VERSION 5.8 ;
BUSBITCHARS "[]" ;
DIVIDERCHAR "/" ;
UNITS
    DATABASE MICRONS 1000 ;
END UNITS

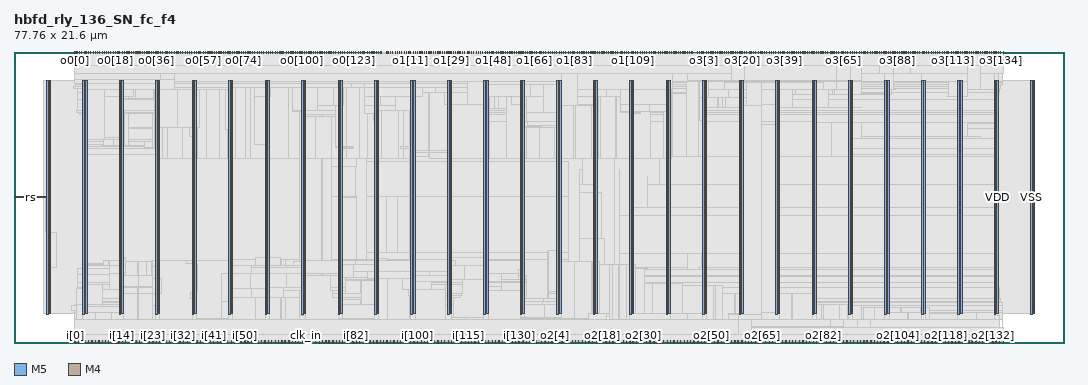
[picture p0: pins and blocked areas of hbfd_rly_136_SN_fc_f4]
MACRO hbfd_rly_136_SN_fc_f4
  FOREIGN hbfd_rly_136_SN_fc_f4 0 0 ;
  CLASS BLOCK ;
  SIZE 77.76 BY 21.6 ;
  PIN clk_in
    DIRECTION INPUT ;
    USE SIGNAL ;
    PORT
      LAYER M5 ;
        RECT  21.6 0 21.624 0.192 ;
    END
  END clk_in
  PIN clk_out0
    DIRECTION OUTPUT ;
    USE SIGNAL ;
    PORT
      LAYER M5 ;
        RECT  15.84 21.408 15.864 21.6 ;
    END
  END clk_out0
  PIN clk_out1
    DIRECTION OUTPUT ;
    USE SIGNAL ;
    PORT
      LAYER M5 ;
        RECT  38.88 21.408 38.904 21.6 ;
    END
  END clk_out1
  PIN clk_out2
    DIRECTION OUTPUT ;
    USE SIGNAL ;
    PORT
      LAYER M5 ;
        RECT  56.16 0 56.184 0.192 ;
    END
  END clk_out2
  PIN clk_out3
    DIRECTION OUTPUT ;
    USE SIGNAL ;
    PORT
      LAYER M5 ;
        RECT  61.92 21.408 61.944 21.6 ;
    END
  END clk_out3
  PIN i[0]
    DIRECTION INPUT ;
    USE SIGNAL ;
    PORT
      LAYER M5 ;
        RECT  4.512 0 4.536 0.192 ;
    END
  END i[0]
  PIN i[100]
    DIRECTION INPUT ;
    USE SIGNAL ;
    PORT
      LAYER M5 ;
        RECT  29.856 0 29.88 0.192 ;
    END
  END i[100]
  PIN i[101]
    DIRECTION INPUT ;
    USE SIGNAL ;
    PORT
      LAYER M5 ;
        RECT  30.144 0 30.168 0.192 ;
    END
  END i[101]
  PIN i[102]
    DIRECTION INPUT ;
    USE SIGNAL ;
    PORT
      LAYER M5 ;
        RECT  30.384 0 30.408 0.192 ;
    END
  END i[102]
  PIN i[103]
    DIRECTION INPUT ;
    USE SIGNAL ;
    PORT
      LAYER M5 ;
        RECT  30.624 0 30.648 0.192 ;
    END
  END i[103]
  PIN i[104]
    DIRECTION INPUT ;
    USE SIGNAL ;
    PORT
      LAYER M5 ;
        RECT  30.864 0 30.888 0.192 ;
    END
  END i[104]
  PIN i[105]
    DIRECTION INPUT ;
    USE SIGNAL ;
    PORT
      LAYER M5 ;
        RECT  31.152 0 31.176 0.192 ;
    END
  END i[105]
  PIN i[106]
    DIRECTION INPUT ;
    USE SIGNAL ;
    PORT
      LAYER M5 ;
        RECT  31.392 0 31.416 0.192 ;
    END
  END i[106]
  PIN i[107]
    DIRECTION INPUT ;
    USE SIGNAL ;
    PORT
      LAYER M5 ;
        RECT  31.632 0 31.656 0.192 ;
    END
  END i[107]
  PIN i[108]
    DIRECTION INPUT ;
    USE SIGNAL ;
    PORT
      LAYER M5 ;
        RECT  31.872 0 31.896 0.192 ;
    END
  END i[108]
  PIN i[109]
    DIRECTION INPUT ;
    USE SIGNAL ;
    PORT
      LAYER M5 ;
        RECT  32.16 0 32.184 0.192 ;
    END
  END i[109]
  PIN i[10]
    DIRECTION INPUT ;
    USE SIGNAL ;
    PORT
      LAYER M5 ;
        RECT  7.008 0 7.032 0.192 ;
    END
  END i[10]
  PIN i[110]
    DIRECTION INPUT ;
    USE SIGNAL ;
    PORT
      LAYER M5 ;
        RECT  32.4 0 32.424 0.192 ;
    END
  END i[110]
  PIN i[111]
    DIRECTION INPUT ;
    USE SIGNAL ;
    PORT
      LAYER M5 ;
        RECT  32.64 0 32.664 0.192 ;
    END
  END i[111]
  PIN i[112]
    DIRECTION INPUT ;
    USE SIGNAL ;
    PORT
      LAYER M5 ;
        RECT  32.88 0 32.904 0.192 ;
    END
  END i[112]
  PIN i[113]
    DIRECTION INPUT ;
    USE SIGNAL ;
    PORT
      LAYER M5 ;
        RECT  33.12 0 33.144 0.192 ;
    END
  END i[113]
  PIN i[114]
    DIRECTION INPUT ;
    USE SIGNAL ;
    PORT
      LAYER M5 ;
        RECT  33.408 0 33.432 0.192 ;
    END
  END i[114]
  PIN i[115]
    DIRECTION INPUT ;
    USE SIGNAL ;
    PORT
      LAYER M5 ;
        RECT  33.648 0 33.672 0.192 ;
    END
  END i[115]
  PIN i[116]
    DIRECTION INPUT ;
    USE SIGNAL ;
    PORT
      LAYER M5 ;
        RECT  33.888 0 33.912 0.192 ;
    END
  END i[116]
  PIN i[117]
    DIRECTION INPUT ;
    USE SIGNAL ;
    PORT
      LAYER M5 ;
        RECT  34.128 0 34.152 0.192 ;
    END
  END i[117]
  PIN i[118]
    DIRECTION INPUT ;
    USE SIGNAL ;
    PORT
      LAYER M5 ;
        RECT  34.416 0 34.44 0.192 ;
    END
  END i[118]
  PIN i[119]
    DIRECTION INPUT ;
    USE SIGNAL ;
    PORT
      LAYER M5 ;
        RECT  34.656 0 34.68 0.192 ;
    END
  END i[119]
  PIN i[11]
    DIRECTION INPUT ;
    USE SIGNAL ;
    PORT
      LAYER M5 ;
        RECT  7.248 0 7.272 0.192 ;
    END
  END i[11]
  PIN i[120]
    DIRECTION INPUT ;
    USE SIGNAL ;
    PORT
      LAYER M5 ;
        RECT  34.896 0 34.92 0.192 ;
    END
  END i[120]
  PIN i[121]
    DIRECTION INPUT ;
    USE SIGNAL ;
    PORT
      LAYER M5 ;
        RECT  35.136 0 35.16 0.192 ;
    END
  END i[121]
  PIN i[122]
    DIRECTION INPUT ;
    USE SIGNAL ;
    PORT
      LAYER M5 ;
        RECT  35.424 0 35.448 0.192 ;
    END
  END i[122]
  PIN i[123]
    DIRECTION INPUT ;
    USE SIGNAL ;
    PORT
      LAYER M5 ;
        RECT  35.664 0 35.688 0.192 ;
    END
  END i[123]
  PIN i[124]
    DIRECTION INPUT ;
    USE SIGNAL ;
    PORT
      LAYER M5 ;
        RECT  35.904 0 35.928 0.192 ;
    END
  END i[124]
  PIN i[125]
    DIRECTION INPUT ;
    USE SIGNAL ;
    PORT
      LAYER M5 ;
        RECT  36.144 0 36.168 0.192 ;
    END
  END i[125]
  PIN i[126]
    DIRECTION INPUT ;
    USE SIGNAL ;
    PORT
      LAYER M5 ;
        RECT  36.384 0 36.408 0.192 ;
    END
  END i[126]
  PIN i[127]
    DIRECTION INPUT ;
    USE SIGNAL ;
    PORT
      LAYER M5 ;
        RECT  36.672 0 36.696 0.192 ;
    END
  END i[127]
  PIN i[128]
    DIRECTION INPUT ;
    USE SIGNAL ;
    PORT
      LAYER M5 ;
        RECT  36.912 0 36.936 0.192 ;
    END
  END i[128]
  PIN i[129]
    DIRECTION INPUT ;
    USE SIGNAL ;
    PORT
      LAYER M5 ;
        RECT  37.152 0 37.176 0.192 ;
    END
  END i[129]
  PIN i[12]
    DIRECTION INPUT ;
    USE SIGNAL ;
    PORT
      LAYER M5 ;
        RECT  7.536 0 7.56 0.192 ;
    END
  END i[12]
  PIN i[130]
    DIRECTION INPUT ;
    USE SIGNAL ;
    PORT
      LAYER M5 ;
        RECT  37.392 0 37.416 0.192 ;
    END
  END i[130]
  PIN i[131]
    DIRECTION INPUT ;
    USE SIGNAL ;
    PORT
      LAYER M5 ;
        RECT  37.68 0 37.704 0.192 ;
    END
  END i[131]
  PIN i[132]
    DIRECTION INPUT ;
    USE SIGNAL ;
    PORT
      LAYER M5 ;
        RECT  37.92 0 37.944 0.192 ;
    END
  END i[132]
  PIN i[133]
    DIRECTION INPUT ;
    USE SIGNAL ;
    PORT
      LAYER M5 ;
        RECT  38.16 0 38.184 0.192 ;
    END
  END i[133]
  PIN i[134]
    DIRECTION INPUT ;
    USE SIGNAL ;
    PORT
      LAYER M5 ;
        RECT  38.4 0 38.424 0.192 ;
    END
  END i[134]
  PIN i[135]
    DIRECTION INPUT ;
    USE SIGNAL ;
    PORT
      LAYER M5 ;
        RECT  38.688 0 38.712 0.192 ;
    END
  END i[135]
  PIN i[13]
    DIRECTION INPUT ;
    USE SIGNAL ;
    PORT
      LAYER M5 ;
        RECT  7.776 0 7.8 0.192 ;
    END
  END i[13]
  PIN i[14]
    DIRECTION INPUT ;
    USE SIGNAL ;
    PORT
      LAYER M5 ;
        RECT  8.016 0 8.04 0.192 ;
    END
  END i[14]
  PIN i[15]
    DIRECTION INPUT ;
    USE SIGNAL ;
    PORT
      LAYER M5 ;
        RECT  8.256 0 8.28 0.192 ;
    END
  END i[15]
  PIN i[16]
    DIRECTION INPUT ;
    USE SIGNAL ;
    PORT
      LAYER M5 ;
        RECT  8.544 0 8.568 0.192 ;
    END
  END i[16]
  PIN i[17]
    DIRECTION INPUT ;
    USE SIGNAL ;
    PORT
      LAYER M5 ;
        RECT  8.784 0 8.808 0.192 ;
    END
  END i[17]
  PIN i[18]
    DIRECTION INPUT ;
    USE SIGNAL ;
    PORT
      LAYER M5 ;
        RECT  9.024 0 9.048 0.192 ;
    END
  END i[18]
  PIN i[19]
    DIRECTION INPUT ;
    USE SIGNAL ;
    PORT
      LAYER M5 ;
        RECT  9.264 0 9.288 0.192 ;
    END
  END i[19]
  PIN i[1]
    DIRECTION INPUT ;
    USE SIGNAL ;
    PORT
      LAYER M5 ;
        RECT  4.752 0 4.776 0.192 ;
    END
  END i[1]
  PIN i[20]
    DIRECTION INPUT ;
    USE SIGNAL ;
    PORT
      LAYER M5 ;
        RECT  9.552 0 9.576 0.192 ;
    END
  END i[20]
  PIN i[21]
    DIRECTION INPUT ;
    USE SIGNAL ;
    PORT
      LAYER M5 ;
        RECT  9.792 0 9.816 0.192 ;
    END
  END i[21]
  PIN i[22]
    DIRECTION INPUT ;
    USE SIGNAL ;
    PORT
      LAYER M5 ;
        RECT  10.032 0 10.056 0.192 ;
    END
  END i[22]
  PIN i[23]
    DIRECTION INPUT ;
    USE SIGNAL ;
    PORT
      LAYER M5 ;
        RECT  10.272 0 10.296 0.192 ;
    END
  END i[23]
  PIN i[24]
    DIRECTION INPUT ;
    USE SIGNAL ;
    PORT
      LAYER M5 ;
        RECT  10.56 0 10.584 0.192 ;
    END
  END i[24]
  PIN i[25]
    DIRECTION INPUT ;
    USE SIGNAL ;
    PORT
      LAYER M5 ;
        RECT  10.8 0 10.824 0.192 ;
    END
  END i[25]
  PIN i[26]
    DIRECTION INPUT ;
    USE SIGNAL ;
    PORT
      LAYER M5 ;
        RECT  11.04 0 11.064 0.192 ;
    END
  END i[26]
  PIN i[27]
    DIRECTION INPUT ;
    USE SIGNAL ;
    PORT
      LAYER M5 ;
        RECT  11.28 0 11.304 0.192 ;
    END
  END i[27]
  PIN i[28]
    DIRECTION INPUT ;
    USE SIGNAL ;
    PORT
      LAYER M5 ;
        RECT  11.52 0 11.544 0.192 ;
    END
  END i[28]
  PIN i[29]
    DIRECTION INPUT ;
    USE SIGNAL ;
    PORT
      LAYER M5 ;
        RECT  11.808 0 11.832 0.192 ;
    END
  END i[29]
  PIN i[2]
    DIRECTION INPUT ;
    USE SIGNAL ;
    PORT
      LAYER M5 ;
        RECT  4.992 0 5.016 0.192 ;
    END
  END i[2]
  PIN i[30]
    DIRECTION INPUT ;
    USE SIGNAL ;
    PORT
      LAYER M5 ;
        RECT  12.048 0 12.072 0.192 ;
    END
  END i[30]
  PIN i[31]
    DIRECTION INPUT ;
    USE SIGNAL ;
    PORT
      LAYER M5 ;
        RECT  12.288 0 12.312 0.192 ;
    END
  END i[31]
  PIN i[32]
    DIRECTION INPUT ;
    USE SIGNAL ;
    PORT
      LAYER M5 ;
        RECT  12.528 0 12.552 0.192 ;
    END
  END i[32]
  PIN i[33]
    DIRECTION INPUT ;
    USE SIGNAL ;
    PORT
      LAYER M5 ;
        RECT  12.816 0 12.84 0.192 ;
    END
  END i[33]
  PIN i[34]
    DIRECTION INPUT ;
    USE SIGNAL ;
    PORT
      LAYER M5 ;
        RECT  13.056 0 13.08 0.192 ;
    END
  END i[34]
  PIN i[35]
    DIRECTION INPUT ;
    USE SIGNAL ;
    PORT
      LAYER M5 ;
        RECT  13.296 0 13.32 0.192 ;
    END
  END i[35]
  PIN i[36]
    DIRECTION INPUT ;
    USE SIGNAL ;
    PORT
      LAYER M5 ;
        RECT  13.536 0 13.56 0.192 ;
    END
  END i[36]
  PIN i[37]
    DIRECTION INPUT ;
    USE SIGNAL ;
    PORT
      LAYER M5 ;
        RECT  13.824 0 13.848 0.192 ;
    END
  END i[37]
  PIN i[38]
    DIRECTION INPUT ;
    USE SIGNAL ;
    PORT
      LAYER M5 ;
        RECT  14.064 0 14.088 0.192 ;
    END
  END i[38]
  PIN i[39]
    DIRECTION INPUT ;
    USE SIGNAL ;
    PORT
      LAYER M5 ;
        RECT  14.304 0 14.328 0.192 ;
    END
  END i[39]
  PIN i[3]
    DIRECTION INPUT ;
    USE SIGNAL ;
    PORT
      LAYER M5 ;
        RECT  5.28 0 5.304 0.192 ;
    END
  END i[3]
  PIN i[40]
    DIRECTION INPUT ;
    USE SIGNAL ;
    PORT
      LAYER M5 ;
        RECT  14.544 0 14.568 0.192 ;
    END
  END i[40]
  PIN i[41]
    DIRECTION INPUT ;
    USE SIGNAL ;
    PORT
      LAYER M5 ;
        RECT  14.784 0 14.808 0.192 ;
    END
  END i[41]
  PIN i[42]
    DIRECTION INPUT ;
    USE SIGNAL ;
    PORT
      LAYER M5 ;
        RECT  15.072 0 15.096 0.192 ;
    END
  END i[42]
  PIN i[43]
    DIRECTION INPUT ;
    USE SIGNAL ;
    PORT
      LAYER M5 ;
        RECT  15.312 0 15.336 0.192 ;
    END
  END i[43]
  PIN i[44]
    DIRECTION INPUT ;
    USE SIGNAL ;
    PORT
      LAYER M5 ;
        RECT  15.552 0 15.576 0.192 ;
    END
  END i[44]
  PIN i[45]
    DIRECTION INPUT ;
    USE SIGNAL ;
    PORT
      LAYER M5 ;
        RECT  15.792 0 15.816 0.192 ;
    END
  END i[45]
  PIN i[46]
    DIRECTION INPUT ;
    USE SIGNAL ;
    PORT
      LAYER M5 ;
        RECT  16.08 0 16.104 0.192 ;
    END
  END i[46]
  PIN i[47]
    DIRECTION INPUT ;
    USE SIGNAL ;
    PORT
      LAYER M5 ;
        RECT  16.32 0 16.344 0.192 ;
    END
  END i[47]
  PIN i[48]
    DIRECTION INPUT ;
    USE SIGNAL ;
    PORT
      LAYER M5 ;
        RECT  16.56 0 16.584 0.192 ;
    END
  END i[48]
  PIN i[49]
    DIRECTION INPUT ;
    USE SIGNAL ;
    PORT
      LAYER M5 ;
        RECT  16.8 0 16.824 0.192 ;
    END
  END i[49]
  PIN i[4]
    DIRECTION INPUT ;
    USE SIGNAL ;
    PORT
      LAYER M5 ;
        RECT  5.52 0 5.544 0.192 ;
    END
  END i[4]
  PIN i[50]
    DIRECTION INPUT ;
    USE SIGNAL ;
    PORT
      LAYER M5 ;
        RECT  17.088 0 17.112 0.192 ;
    END
  END i[50]
  PIN i[51]
    DIRECTION INPUT ;
    USE SIGNAL ;
    PORT
      LAYER M5 ;
        RECT  17.328 0 17.352 0.192 ;
    END
  END i[51]
  PIN i[52]
    DIRECTION INPUT ;
    USE SIGNAL ;
    PORT
      LAYER M5 ;
        RECT  17.568 0 17.592 0.192 ;
    END
  END i[52]
  PIN i[53]
    DIRECTION INPUT ;
    USE SIGNAL ;
    PORT
      LAYER M5 ;
        RECT  17.808 0 17.832 0.192 ;
    END
  END i[53]
  PIN i[54]
    DIRECTION INPUT ;
    USE SIGNAL ;
    PORT
      LAYER M5 ;
        RECT  18.048 0 18.072 0.192 ;
    END
  END i[54]
  PIN i[55]
    DIRECTION INPUT ;
    USE SIGNAL ;
    PORT
      LAYER M5 ;
        RECT  18.336 0 18.36 0.192 ;
    END
  END i[55]
  PIN i[56]
    DIRECTION INPUT ;
    USE SIGNAL ;
    PORT
      LAYER M5 ;
        RECT  18.576 0 18.6 0.192 ;
    END
  END i[56]
  PIN i[57]
    DIRECTION INPUT ;
    USE SIGNAL ;
    PORT
      LAYER M5 ;
        RECT  18.816 0 18.84 0.192 ;
    END
  END i[57]
  PIN i[58]
    DIRECTION INPUT ;
    USE SIGNAL ;
    PORT
      LAYER M5 ;
        RECT  19.056 0 19.08 0.192 ;
    END
  END i[58]
  PIN i[59]
    DIRECTION INPUT ;
    USE SIGNAL ;
    PORT
      LAYER M5 ;
        RECT  19.344 0 19.368 0.192 ;
    END
  END i[59]
  PIN i[5]
    DIRECTION INPUT ;
    USE SIGNAL ;
    PORT
      LAYER M5 ;
        RECT  5.76 0 5.784 0.192 ;
    END
  END i[5]
  PIN i[60]
    DIRECTION INPUT ;
    USE SIGNAL ;
    PORT
      LAYER M5 ;
        RECT  19.584 0 19.608 0.192 ;
    END
  END i[60]
  PIN i[61]
    DIRECTION INPUT ;
    USE SIGNAL ;
    PORT
      LAYER M5 ;
        RECT  19.824 0 19.848 0.192 ;
    END
  END i[61]
  PIN i[62]
    DIRECTION INPUT ;
    USE SIGNAL ;
    PORT
      LAYER M5 ;
        RECT  20.064 0 20.088 0.192 ;
    END
  END i[62]
  PIN i[63]
    DIRECTION INPUT ;
    USE SIGNAL ;
    PORT
      LAYER M5 ;
        RECT  20.352 0 20.376 0.192 ;
    END
  END i[63]
  PIN i[64]
    DIRECTION INPUT ;
    USE SIGNAL ;
    PORT
      LAYER M5 ;
        RECT  20.592 0 20.616 0.192 ;
    END
  END i[64]
  PIN i[65]
    DIRECTION INPUT ;
    USE SIGNAL ;
    PORT
      LAYER M5 ;
        RECT  20.832 0 20.856 0.192 ;
    END
  END i[65]
  PIN i[66]
    DIRECTION INPUT ;
    USE SIGNAL ;
    PORT
      LAYER M5 ;
        RECT  21.072 0 21.096 0.192 ;
    END
  END i[66]
  PIN i[67]
    DIRECTION INPUT ;
    USE SIGNAL ;
    PORT
      LAYER M5 ;
        RECT  21.36 0 21.384 0.192 ;
    END
  END i[67]
  PIN i[68]
    DIRECTION INPUT ;
    USE SIGNAL ;
    PORT
      LAYER M5 ;
        RECT  21.84 0 21.864 0.192 ;
    END
  END i[68]
  PIN i[69]
    DIRECTION INPUT ;
    USE SIGNAL ;
    PORT
      LAYER M5 ;
        RECT  22.08 0 22.104 0.192 ;
    END
  END i[69]
  PIN i[6]
    DIRECTION INPUT ;
    USE SIGNAL ;
    PORT
      LAYER M5 ;
        RECT  6 0 6.024 0.192 ;
    END
  END i[6]
  PIN i[70]
    DIRECTION INPUT ;
    USE SIGNAL ;
    PORT
      LAYER M5 ;
        RECT  22.32 0 22.344 0.192 ;
    END
  END i[70]
  PIN i[71]
    DIRECTION INPUT ;
    USE SIGNAL ;
    PORT
      LAYER M5 ;
        RECT  22.608 0 22.632 0.192 ;
    END
  END i[71]
  PIN i[72]
    DIRECTION INPUT ;
    USE SIGNAL ;
    PORT
      LAYER M5 ;
        RECT  22.848 0 22.872 0.192 ;
    END
  END i[72]
  PIN i[73]
    DIRECTION INPUT ;
    USE SIGNAL ;
    PORT
      LAYER M5 ;
        RECT  23.088 0 23.112 0.192 ;
    END
  END i[73]
  PIN i[74]
    DIRECTION INPUT ;
    USE SIGNAL ;
    PORT
      LAYER M5 ;
        RECT  23.328 0 23.352 0.192 ;
    END
  END i[74]
  PIN i[75]
    DIRECTION INPUT ;
    USE SIGNAL ;
    PORT
      LAYER M5 ;
        RECT  23.616 0 23.64 0.192 ;
    END
  END i[75]
  PIN i[76]
    DIRECTION INPUT ;
    USE SIGNAL ;
    PORT
      LAYER M5 ;
        RECT  23.856 0 23.88 0.192 ;
    END
  END i[76]
  PIN i[77]
    DIRECTION INPUT ;
    USE SIGNAL ;
    PORT
      LAYER M5 ;
        RECT  24.096 0 24.12 0.192 ;
    END
  END i[77]
  PIN i[78]
    DIRECTION INPUT ;
    USE SIGNAL ;
    PORT
      LAYER M5 ;
        RECT  24.336 0 24.36 0.192 ;
    END
  END i[78]
  PIN i[79]
    DIRECTION INPUT ;
    USE SIGNAL ;
    PORT
      LAYER M5 ;
        RECT  24.624 0 24.648 0.192 ;
    END
  END i[79]
  PIN i[7]
    DIRECTION INPUT ;
    USE SIGNAL ;
    PORT
      LAYER M5 ;
        RECT  6.288 0 6.312 0.192 ;
    END
  END i[7]
  PIN i[80]
    DIRECTION INPUT ;
    USE SIGNAL ;
    PORT
      LAYER M5 ;
        RECT  24.864 0 24.888 0.192 ;
    END
  END i[80]
  PIN i[81]
    DIRECTION INPUT ;
    USE SIGNAL ;
    PORT
      LAYER M5 ;
        RECT  25.104 0 25.128 0.192 ;
    END
  END i[81]
  PIN i[82]
    DIRECTION INPUT ;
    USE SIGNAL ;
    PORT
      LAYER M5 ;
        RECT  25.344 0 25.368 0.192 ;
    END
  END i[82]
  PIN i[83]
    DIRECTION INPUT ;
    USE SIGNAL ;
    PORT
      LAYER M5 ;
        RECT  25.584 0 25.608 0.192 ;
    END
  END i[83]
  PIN i[84]
    DIRECTION INPUT ;
    USE SIGNAL ;
    PORT
      LAYER M5 ;
        RECT  25.872 0 25.896 0.192 ;
    END
  END i[84]
  PIN i[85]
    DIRECTION INPUT ;
    USE SIGNAL ;
    PORT
      LAYER M5 ;
        RECT  26.112 0 26.136 0.192 ;
    END
  END i[85]
  PIN i[86]
    DIRECTION INPUT ;
    USE SIGNAL ;
    PORT
      LAYER M5 ;
        RECT  26.352 0 26.376 0.192 ;
    END
  END i[86]
  PIN i[87]
    DIRECTION INPUT ;
    USE SIGNAL ;
    PORT
      LAYER M5 ;
        RECT  26.592 0 26.616 0.192 ;
    END
  END i[87]
  PIN i[88]
    DIRECTION INPUT ;
    USE SIGNAL ;
    PORT
      LAYER M5 ;
        RECT  26.88 0 26.904 0.192 ;
    END
  END i[88]
  PIN i[89]
    DIRECTION INPUT ;
    USE SIGNAL ;
    PORT
      LAYER M5 ;
        RECT  27.12 0 27.144 0.192 ;
    END
  END i[89]
  PIN i[8]
    DIRECTION INPUT ;
    USE SIGNAL ;
    PORT
      LAYER M5 ;
        RECT  6.528 0 6.552 0.192 ;
    END
  END i[8]
  PIN i[90]
    DIRECTION INPUT ;
    USE SIGNAL ;
    PORT
      LAYER M5 ;
        RECT  27.36 0 27.384 0.192 ;
    END
  END i[90]
  PIN i[91]
    DIRECTION INPUT ;
    USE SIGNAL ;
    PORT
      LAYER M5 ;
        RECT  27.6 0 27.624 0.192 ;
    END
  END i[91]
  PIN i[92]
    DIRECTION INPUT ;
    USE SIGNAL ;
    PORT
      LAYER M5 ;
        RECT  27.888 0 27.912 0.192 ;
    END
  END i[92]
  PIN i[93]
    DIRECTION INPUT ;
    USE SIGNAL ;
    PORT
      LAYER M5 ;
        RECT  28.128 0 28.152 0.192 ;
    END
  END i[93]
  PIN i[94]
    DIRECTION INPUT ;
    USE SIGNAL ;
    PORT
      LAYER M5 ;
        RECT  28.368 0 28.392 0.192 ;
    END
  END i[94]
  PIN i[95]
    DIRECTION INPUT ;
    USE SIGNAL ;
    PORT
      LAYER M5 ;
        RECT  28.608 0 28.632 0.192 ;
    END
  END i[95]
  PIN i[96]
    DIRECTION INPUT ;
    USE SIGNAL ;
    PORT
      LAYER M5 ;
        RECT  28.896 0 28.92 0.192 ;
    END
  END i[96]
  PIN i[97]
    DIRECTION INPUT ;
    USE SIGNAL ;
    PORT
      LAYER M5 ;
        RECT  29.136 0 29.16 0.192 ;
    END
  END i[97]
  PIN i[98]
    DIRECTION INPUT ;
    USE SIGNAL ;
    PORT
      LAYER M5 ;
        RECT  29.376 0 29.4 0.192 ;
    END
  END i[98]
  PIN i[99]
    DIRECTION INPUT ;
    USE SIGNAL ;
    PORT
      LAYER M5 ;
        RECT  29.616 0 29.64 0.192 ;
    END
  END i[99]
  PIN i[9]
    DIRECTION INPUT ;
    USE SIGNAL ;
    PORT
      LAYER M5 ;
        RECT  6.768 0 6.792 0.192 ;
    END
  END i[9]
  PIN o0[0]
    DIRECTION OUTPUT ;
    USE SIGNAL ;
    PORT
      LAYER M5 ;
        RECT  4.512 21.408 4.536 21.6 ;
    END
  END o0[0]
  PIN o0[100]
    DIRECTION OUTPUT ;
    USE SIGNAL ;
    PORT
      LAYER M5 ;
        RECT  21.312 21.408 21.336 21.6 ;
    END
  END o0[100]
  PIN o0[101]
    DIRECTION OUTPUT ;
    USE SIGNAL ;
    PORT
      LAYER M5 ;
        RECT  21.504 21.408 21.528 21.6 ;
    END
  END o0[101]
  PIN o0[102]
    DIRECTION OUTPUT ;
    USE SIGNAL ;
    PORT
      LAYER M5 ;
        RECT  21.648 21.408 21.672 21.6 ;
    END
  END o0[102]
  PIN o0[103]
    DIRECTION OUTPUT ;
    USE SIGNAL ;
    PORT
      LAYER M5 ;
        RECT  21.84 21.408 21.864 21.6 ;
    END
  END o0[103]
  PIN o0[104]
    DIRECTION OUTPUT ;
    USE SIGNAL ;
    PORT
      LAYER M5 ;
        RECT  21.984 21.408 22.008 21.6 ;
    END
  END o0[104]
  PIN o0[105]
    DIRECTION OUTPUT ;
    USE SIGNAL ;
    PORT
      LAYER M5 ;
        RECT  22.176 21.408 22.2 21.6 ;
    END
  END o0[105]
  PIN o0[106]
    DIRECTION OUTPUT ;
    USE SIGNAL ;
    PORT
      LAYER M5 ;
        RECT  22.32 21.408 22.344 21.6 ;
    END
  END o0[106]
  PIN o0[107]
    DIRECTION OUTPUT ;
    USE SIGNAL ;
    PORT
      LAYER M5 ;
        RECT  22.464 21.408 22.488 21.6 ;
    END
  END o0[107]
  PIN o0[108]
    DIRECTION OUTPUT ;
    USE SIGNAL ;
    PORT
      LAYER M5 ;
        RECT  22.656 21.408 22.68 21.6 ;
    END
  END o0[108]
  PIN o0[109]
    DIRECTION OUTPUT ;
    USE SIGNAL ;
    PORT
      LAYER M5 ;
        RECT  22.8 21.408 22.824 21.6 ;
    END
  END o0[109]
  PIN o0[10]
    DIRECTION OUTPUT ;
    USE SIGNAL ;
    PORT
      LAYER M5 ;
        RECT  6.192 21.408 6.216 21.6 ;
    END
  END o0[10]
  PIN o0[110]
    DIRECTION OUTPUT ;
    USE SIGNAL ;
    PORT
      LAYER M5 ;
        RECT  22.992 21.408 23.016 21.6 ;
    END
  END o0[110]
  PIN o0[111]
    DIRECTION OUTPUT ;
    USE SIGNAL ;
    PORT
      LAYER M5 ;
        RECT  23.136 21.408 23.16 21.6 ;
    END
  END o0[111]
  PIN o0[112]
    DIRECTION OUTPUT ;
    USE SIGNAL ;
    PORT
      LAYER M5 ;
        RECT  23.328 21.408 23.352 21.6 ;
    END
  END o0[112]
  PIN o0[113]
    DIRECTION OUTPUT ;
    USE SIGNAL ;
    PORT
      LAYER M5 ;
        RECT  23.472 21.408 23.496 21.6 ;
    END
  END o0[113]
  PIN o0[114]
    DIRECTION OUTPUT ;
    USE SIGNAL ;
    PORT
      LAYER M5 ;
        RECT  23.664 21.408 23.688 21.6 ;
    END
  END o0[114]
  PIN o0[115]
    DIRECTION OUTPUT ;
    USE SIGNAL ;
    PORT
      LAYER M5 ;
        RECT  23.808 21.408 23.832 21.6 ;
    END
  END o0[115]
  PIN o0[116]
    DIRECTION OUTPUT ;
    USE SIGNAL ;
    PORT
      LAYER M5 ;
        RECT  24 21.408 24.024 21.6 ;
    END
  END o0[116]
  PIN o0[117]
    DIRECTION OUTPUT ;
    USE SIGNAL ;
    PORT
      LAYER M5 ;
        RECT  24.144 21.408 24.168 21.6 ;
    END
  END o0[117]
  PIN o0[118]
    DIRECTION OUTPUT ;
    USE SIGNAL ;
    PORT
      LAYER M5 ;
        RECT  24.336 21.408 24.36 21.6 ;
    END
  END o0[118]
  PIN o0[119]
    DIRECTION OUTPUT ;
    USE SIGNAL ;
    PORT
      LAYER M5 ;
        RECT  24.48 21.408 24.504 21.6 ;
    END
  END o0[119]
  PIN o0[11]
    DIRECTION OUTPUT ;
    USE SIGNAL ;
    PORT
      LAYER M5 ;
        RECT  6.336 21.408 6.36 21.6 ;
    END
  END o0[11]
  PIN o0[120]
    DIRECTION OUTPUT ;
    USE SIGNAL ;
    PORT
      LAYER M5 ;
        RECT  24.672 21.408 24.696 21.6 ;
    END
  END o0[120]
  PIN o0[121]
    DIRECTION OUTPUT ;
    USE SIGNAL ;
    PORT
      LAYER M5 ;
        RECT  24.816 21.408 24.84 21.6 ;
    END
  END o0[121]
  PIN o0[122]
    DIRECTION OUTPUT ;
    USE SIGNAL ;
    PORT
      LAYER M5 ;
        RECT  24.96 21.408 24.984 21.6 ;
    END
  END o0[122]
  PIN o0[123]
    DIRECTION OUTPUT ;
    USE SIGNAL ;
    PORT
      LAYER M5 ;
        RECT  25.152 21.408 25.176 21.6 ;
    END
  END o0[123]
  PIN o0[124]
    DIRECTION OUTPUT ;
    USE SIGNAL ;
    PORT
      LAYER M5 ;
        RECT  25.296 21.408 25.32 21.6 ;
    END
  END o0[124]
  PIN o0[125]
    DIRECTION OUTPUT ;
    USE SIGNAL ;
    PORT
      LAYER M5 ;
        RECT  25.488 21.408 25.512 21.6 ;
    END
  END o0[125]
  PIN o0[126]
    DIRECTION OUTPUT ;
    USE SIGNAL ;
    PORT
      LAYER M5 ;
        RECT  25.632 21.408 25.656 21.6 ;
    END
  END o0[126]
  PIN o0[127]
    DIRECTION OUTPUT ;
    USE SIGNAL ;
    PORT
      LAYER M5 ;
        RECT  25.824 21.408 25.848 21.6 ;
    END
  END o0[127]
  PIN o0[128]
    DIRECTION OUTPUT ;
    USE SIGNAL ;
    PORT
      LAYER M5 ;
        RECT  25.968 21.408 25.992 21.6 ;
    END
  END o0[128]
  PIN o0[129]
    DIRECTION OUTPUT ;
    USE SIGNAL ;
    PORT
      LAYER M5 ;
        RECT  26.16 21.408 26.184 21.6 ;
    END
  END o0[129]
  PIN o0[12]
    DIRECTION OUTPUT ;
    USE SIGNAL ;
    PORT
      LAYER M5 ;
        RECT  6.528 21.408 6.552 21.6 ;
    END
  END o0[12]
  PIN o0[130]
    DIRECTION OUTPUT ;
    USE SIGNAL ;
    PORT
      LAYER M5 ;
        RECT  26.304 21.408 26.328 21.6 ;
    END
  END o0[130]
  PIN o0[131]
    DIRECTION OUTPUT ;
    USE SIGNAL ;
    PORT
      LAYER M5 ;
        RECT  26.496 21.408 26.52 21.6 ;
    END
  END o0[131]
  PIN o0[132]
    DIRECTION OUTPUT ;
    USE SIGNAL ;
    PORT
      LAYER M5 ;
        RECT  26.64 21.408 26.664 21.6 ;
    END
  END o0[132]
  PIN o0[133]
    DIRECTION OUTPUT ;
    USE SIGNAL ;
    PORT
      LAYER M5 ;
        RECT  26.832 21.408 26.856 21.6 ;
    END
  END o0[133]
  PIN o0[134]
    DIRECTION OUTPUT ;
    USE SIGNAL ;
    PORT
      LAYER M5 ;
        RECT  26.976 21.408 27 21.6 ;
    END
  END o0[134]
  PIN o0[135]
    DIRECTION OUTPUT ;
    USE SIGNAL ;
    PORT
      LAYER M5 ;
        RECT  27.168 21.408 27.192 21.6 ;
    END
  END o0[135]
  PIN o0[13]
    DIRECTION OUTPUT ;
    USE SIGNAL ;
    PORT
      LAYER M5 ;
        RECT  6.672 21.408 6.696 21.6 ;
    END
  END o0[13]
  PIN o0[14]
    DIRECTION OUTPUT ;
    USE SIGNAL ;
    PORT
      LAYER M5 ;
        RECT  6.816 21.408 6.84 21.6 ;
    END
  END o0[14]
  PIN o0[15]
    DIRECTION OUTPUT ;
    USE SIGNAL ;
    PORT
      LAYER M5 ;
        RECT  7.008 21.408 7.032 21.6 ;
    END
  END o0[15]
  PIN o0[16]
    DIRECTION OUTPUT ;
    USE SIGNAL ;
    PORT
      LAYER M5 ;
        RECT  7.152 21.408 7.176 21.6 ;
    END
  END o0[16]
  PIN o0[17]
    DIRECTION OUTPUT ;
    USE SIGNAL ;
    PORT
      LAYER M5 ;
        RECT  7.344 21.408 7.368 21.6 ;
    END
  END o0[17]
  PIN o0[18]
    DIRECTION OUTPUT ;
    USE SIGNAL ;
    PORT
      LAYER M5 ;
        RECT  7.488 21.408 7.512 21.6 ;
    END
  END o0[18]
  PIN o0[19]
    DIRECTION OUTPUT ;
    USE SIGNAL ;
    PORT
      LAYER M5 ;
        RECT  7.68 21.408 7.704 21.6 ;
    END
  END o0[19]
  PIN o0[1]
    DIRECTION OUTPUT ;
    USE SIGNAL ;
    PORT
      LAYER M5 ;
        RECT  4.656 21.408 4.68 21.6 ;
    END
  END o0[1]
  PIN o0[20]
    DIRECTION OUTPUT ;
    USE SIGNAL ;
    PORT
      LAYER M5 ;
        RECT  7.824 21.408 7.848 21.6 ;
    END
  END o0[20]
  PIN o0[21]
    DIRECTION OUTPUT ;
    USE SIGNAL ;
    PORT
      LAYER M5 ;
        RECT  8.016 21.408 8.04 21.6 ;
    END
  END o0[21]
  PIN o0[22]
    DIRECTION OUTPUT ;
    USE SIGNAL ;
    PORT
      LAYER M5 ;
        RECT  8.16 21.408 8.184 21.6 ;
    END
  END o0[22]
  PIN o0[23]
    DIRECTION OUTPUT ;
    USE SIGNAL ;
    PORT
      LAYER M5 ;
        RECT  8.352 21.408 8.376 21.6 ;
    END
  END o0[23]
  PIN o0[24]
    DIRECTION OUTPUT ;
    USE SIGNAL ;
    PORT
      LAYER M5 ;
        RECT  8.496 21.408 8.52 21.6 ;
    END
  END o0[24]
  PIN o0[25]
    DIRECTION OUTPUT ;
    USE SIGNAL ;
    PORT
      LAYER M5 ;
        RECT  8.688 21.408 8.712 21.6 ;
    END
  END o0[25]
  PIN o0[26]
    DIRECTION OUTPUT ;
    USE SIGNAL ;
    PORT
      LAYER M5 ;
        RECT  8.832 21.408 8.856 21.6 ;
    END
  END o0[26]
  PIN o0[27]
    DIRECTION OUTPUT ;
    USE SIGNAL ;
    PORT
      LAYER M5 ;
        RECT  9.024 21.408 9.048 21.6 ;
    END
  END o0[27]
  PIN o0[28]
    DIRECTION OUTPUT ;
    USE SIGNAL ;
    PORT
      LAYER M5 ;
        RECT  9.168 21.408 9.192 21.6 ;
    END
  END o0[28]
  PIN o0[29]
    DIRECTION OUTPUT ;
    USE SIGNAL ;
    PORT
      LAYER M5 ;
        RECT  9.312 21.408 9.336 21.6 ;
    END
  END o0[29]
  PIN o0[2]
    DIRECTION OUTPUT ;
    USE SIGNAL ;
    PORT
      LAYER M5 ;
        RECT  4.848 21.408 4.872 21.6 ;
    END
  END o0[2]
  PIN o0[30]
    DIRECTION OUTPUT ;
    USE SIGNAL ;
    PORT
      LAYER M5 ;
        RECT  9.504 21.408 9.528 21.6 ;
    END
  END o0[30]
  PIN o0[31]
    DIRECTION OUTPUT ;
    USE SIGNAL ;
    PORT
      LAYER M5 ;
        RECT  9.648 21.408 9.672 21.6 ;
    END
  END o0[31]
  PIN o0[32]
    DIRECTION OUTPUT ;
    USE SIGNAL ;
    PORT
      LAYER M5 ;
        RECT  9.84 21.408 9.864 21.6 ;
    END
  END o0[32]
  PIN o0[33]
    DIRECTION OUTPUT ;
    USE SIGNAL ;
    PORT
      LAYER M5 ;
        RECT  9.984 21.408 10.008 21.6 ;
    END
  END o0[33]
  PIN o0[34]
    DIRECTION OUTPUT ;
    USE SIGNAL ;
    PORT
      LAYER M5 ;
        RECT  10.176 21.408 10.2 21.6 ;
    END
  END o0[34]
  PIN o0[35]
    DIRECTION OUTPUT ;
    USE SIGNAL ;
    PORT
      LAYER M5 ;
        RECT  10.32 21.408 10.344 21.6 ;
    END
  END o0[35]
  PIN o0[36]
    DIRECTION OUTPUT ;
    USE SIGNAL ;
    PORT
      LAYER M5 ;
        RECT  10.512 21.408 10.536 21.6 ;
    END
  END o0[36]
  PIN o0[37]
    DIRECTION OUTPUT ;
    USE SIGNAL ;
    PORT
      LAYER M5 ;
        RECT  10.656 21.408 10.68 21.6 ;
    END
  END o0[37]
  PIN o0[38]
    DIRECTION OUTPUT ;
    USE SIGNAL ;
    PORT
      LAYER M5 ;
        RECT  10.848 21.408 10.872 21.6 ;
    END
  END o0[38]
  PIN o0[39]
    DIRECTION OUTPUT ;
    USE SIGNAL ;
    PORT
      LAYER M5 ;
        RECT  10.992 21.408 11.016 21.6 ;
    END
  END o0[39]
  PIN o0[3]
    DIRECTION OUTPUT ;
    USE SIGNAL ;
    PORT
      LAYER M5 ;
        RECT  4.992 21.408 5.016 21.6 ;
    END
  END o0[3]
  PIN o0[40]
    DIRECTION OUTPUT ;
    USE SIGNAL ;
    PORT
      LAYER M5 ;
        RECT  11.184 21.408 11.208 21.6 ;
    END
  END o0[40]
  PIN o0[41]
    DIRECTION OUTPUT ;
    USE SIGNAL ;
    PORT
      LAYER M5 ;
        RECT  11.328 21.408 11.352 21.6 ;
    END
  END o0[41]
  PIN o0[42]
    DIRECTION OUTPUT ;
    USE SIGNAL ;
    PORT
      LAYER M5 ;
        RECT  11.52 21.408 11.544 21.6 ;
    END
  END o0[42]
  PIN o0[43]
    DIRECTION OUTPUT ;
    USE SIGNAL ;
    PORT
      LAYER M5 ;
        RECT  11.664 21.408 11.688 21.6 ;
    END
  END o0[43]
  PIN o0[44]
    DIRECTION OUTPUT ;
    USE SIGNAL ;
    PORT
      LAYER M5 ;
        RECT  11.856 21.408 11.88 21.6 ;
    END
  END o0[44]
  PIN o0[45]
    DIRECTION OUTPUT ;
    USE SIGNAL ;
    PORT
      LAYER M5 ;
        RECT  12 21.408 12.024 21.6 ;
    END
  END o0[45]
  PIN o0[46]
    DIRECTION OUTPUT ;
    USE SIGNAL ;
    PORT
      LAYER M5 ;
        RECT  12.144 21.408 12.168 21.6 ;
    END
  END o0[46]
  PIN o0[47]
    DIRECTION OUTPUT ;
    USE SIGNAL ;
    PORT
      LAYER M5 ;
        RECT  12.336 21.408 12.36 21.6 ;
    END
  END o0[47]
  PIN o0[48]
    DIRECTION OUTPUT ;
    USE SIGNAL ;
    PORT
      LAYER M5 ;
        RECT  12.48 21.408 12.504 21.6 ;
    END
  END o0[48]
  PIN o0[49]
    DIRECTION OUTPUT ;
    USE SIGNAL ;
    PORT
      LAYER M5 ;
        RECT  12.672 21.408 12.696 21.6 ;
    END
  END o0[49]
  PIN o0[4]
    DIRECTION OUTPUT ;
    USE SIGNAL ;
    PORT
      LAYER M5 ;
        RECT  5.184 21.408 5.208 21.6 ;
    END
  END o0[4]
  PIN o0[50]
    DIRECTION OUTPUT ;
    USE SIGNAL ;
    PORT
      LAYER M5 ;
        RECT  12.816 21.408 12.84 21.6 ;
    END
  END o0[50]
  PIN o0[51]
    DIRECTION OUTPUT ;
    USE SIGNAL ;
    PORT
      LAYER M5 ;
        RECT  13.008 21.408 13.032 21.6 ;
    END
  END o0[51]
  PIN o0[52]
    DIRECTION OUTPUT ;
    USE SIGNAL ;
    PORT
      LAYER M5 ;
        RECT  13.152 21.408 13.176 21.6 ;
    END
  END o0[52]
  PIN o0[53]
    DIRECTION OUTPUT ;
    USE SIGNAL ;
    PORT
      LAYER M5 ;
        RECT  13.344 21.408 13.368 21.6 ;
    END
  END o0[53]
  PIN o0[54]
    DIRECTION OUTPUT ;
    USE SIGNAL ;
    PORT
      LAYER M5 ;
        RECT  13.488 21.408 13.512 21.6 ;
    END
  END o0[54]
  PIN o0[55]
    DIRECTION OUTPUT ;
    USE SIGNAL ;
    PORT
      LAYER M5 ;
        RECT  13.68 21.408 13.704 21.6 ;
    END
  END o0[55]
  PIN o0[56]
    DIRECTION OUTPUT ;
    USE SIGNAL ;
    PORT
      LAYER M5 ;
        RECT  13.824 21.408 13.848 21.6 ;
    END
  END o0[56]
  PIN o0[57]
    DIRECTION OUTPUT ;
    USE SIGNAL ;
    PORT
      LAYER M5 ;
        RECT  14.016 21.408 14.04 21.6 ;
    END
  END o0[57]
  PIN o0[58]
    DIRECTION OUTPUT ;
    USE SIGNAL ;
    PORT
      LAYER M5 ;
        RECT  14.16 21.408 14.184 21.6 ;
    END
  END o0[58]
  PIN o0[59]
    DIRECTION OUTPUT ;
    USE SIGNAL ;
    PORT
      LAYER M5 ;
        RECT  14.352 21.408 14.376 21.6 ;
    END
  END o0[59]
  PIN o0[5]
    DIRECTION OUTPUT ;
    USE SIGNAL ;
    PORT
      LAYER M5 ;
        RECT  5.328 21.408 5.352 21.6 ;
    END
  END o0[5]
  PIN o0[60]
    DIRECTION OUTPUT ;
    USE SIGNAL ;
    PORT
      LAYER M5 ;
        RECT  14.496 21.408 14.52 21.6 ;
    END
  END o0[60]
  PIN o0[61]
    DIRECTION OUTPUT ;
    USE SIGNAL ;
    PORT
      LAYER M5 ;
        RECT  14.64 21.408 14.664 21.6 ;
    END
  END o0[61]
  PIN o0[62]
    DIRECTION OUTPUT ;
    USE SIGNAL ;
    PORT
      LAYER M5 ;
        RECT  14.832 21.408 14.856 21.6 ;
    END
  END o0[62]
  PIN o0[63]
    DIRECTION OUTPUT ;
    USE SIGNAL ;
    PORT
      LAYER M5 ;
        RECT  14.976 21.408 15 21.6 ;
    END
  END o0[63]
  PIN o0[64]
    DIRECTION OUTPUT ;
    USE SIGNAL ;
    PORT
      LAYER M5 ;
        RECT  15.168 21.408 15.192 21.6 ;
    END
  END o0[64]
  PIN o0[65]
    DIRECTION OUTPUT ;
    USE SIGNAL ;
    PORT
      LAYER M5 ;
        RECT  15.312 21.408 15.336 21.6 ;
    END
  END o0[65]
  PIN o0[66]
    DIRECTION OUTPUT ;
    USE SIGNAL ;
    PORT
      LAYER M5 ;
        RECT  15.504 21.408 15.528 21.6 ;
    END
  END o0[66]
  PIN o0[67]
    DIRECTION OUTPUT ;
    USE SIGNAL ;
    PORT
      LAYER M5 ;
        RECT  15.648 21.408 15.672 21.6 ;
    END
  END o0[67]
  PIN o0[68]
    DIRECTION OUTPUT ;
    USE SIGNAL ;
    PORT
      LAYER M5 ;
        RECT  15.984 21.408 16.008 21.6 ;
    END
  END o0[68]
  PIN o0[69]
    DIRECTION OUTPUT ;
    USE SIGNAL ;
    PORT
      LAYER M5 ;
        RECT  16.176 21.408 16.2 21.6 ;
    END
  END o0[69]
  PIN o0[6]
    DIRECTION OUTPUT ;
    USE SIGNAL ;
    PORT
      LAYER M5 ;
        RECT  5.52 21.408 5.544 21.6 ;
    END
  END o0[6]
  PIN o0[70]
    DIRECTION OUTPUT ;
    USE SIGNAL ;
    PORT
      LAYER M5 ;
        RECT  16.32 21.408 16.344 21.6 ;
    END
  END o0[70]
  PIN o0[71]
    DIRECTION OUTPUT ;
    USE SIGNAL ;
    PORT
      LAYER M5 ;
        RECT  16.512 21.408 16.536 21.6 ;
    END
  END o0[71]
  PIN o0[72]
    DIRECTION OUTPUT ;
    USE SIGNAL ;
    PORT
      LAYER M5 ;
        RECT  16.656 21.408 16.68 21.6 ;
    END
  END o0[72]
  PIN o0[73]
    DIRECTION OUTPUT ;
    USE SIGNAL ;
    PORT
      LAYER M5 ;
        RECT  16.848 21.408 16.872 21.6 ;
    END
  END o0[73]
  PIN o0[74]
    DIRECTION OUTPUT ;
    USE SIGNAL ;
    PORT
      LAYER M5 ;
        RECT  16.992 21.408 17.016 21.6 ;
    END
  END o0[74]
  PIN o0[75]
    DIRECTION OUTPUT ;
    USE SIGNAL ;
    PORT
      LAYER M5 ;
        RECT  17.136 21.408 17.16 21.6 ;
    END
  END o0[75]
  PIN o0[76]
    DIRECTION OUTPUT ;
    USE SIGNAL ;
    PORT
      LAYER M5 ;
        RECT  17.328 21.408 17.352 21.6 ;
    END
  END o0[76]
  PIN o0[77]
    DIRECTION OUTPUT ;
    USE SIGNAL ;
    PORT
      LAYER M5 ;
        RECT  17.472 21.408 17.496 21.6 ;
    END
  END o0[77]
  PIN o0[78]
    DIRECTION OUTPUT ;
    USE SIGNAL ;
    PORT
      LAYER M5 ;
        RECT  17.664 21.408 17.688 21.6 ;
    END
  END o0[78]
  PIN o0[79]
    DIRECTION OUTPUT ;
    USE SIGNAL ;
    PORT
      LAYER M5 ;
        RECT  17.808 21.408 17.832 21.6 ;
    END
  END o0[79]
  PIN o0[7]
    DIRECTION OUTPUT ;
    USE SIGNAL ;
    PORT
      LAYER M5 ;
        RECT  5.664 21.408 5.688 21.6 ;
    END
  END o0[7]
  PIN o0[80]
    DIRECTION OUTPUT ;
    USE SIGNAL ;
    PORT
      LAYER M5 ;
        RECT  18 21.408 18.024 21.6 ;
    END
  END o0[80]
  PIN o0[81]
    DIRECTION OUTPUT ;
    USE SIGNAL ;
    PORT
      LAYER M5 ;
        RECT  18.144 21.408 18.168 21.6 ;
    END
  END o0[81]
  PIN o0[82]
    DIRECTION OUTPUT ;
    USE SIGNAL ;
    PORT
      LAYER M5 ;
        RECT  18.336 21.408 18.36 21.6 ;
    END
  END o0[82]
  PIN o0[83]
    DIRECTION OUTPUT ;
    USE SIGNAL ;
    PORT
      LAYER M5 ;
        RECT  18.48 21.408 18.504 21.6 ;
    END
  END o0[83]
  PIN o0[84]
    DIRECTION OUTPUT ;
    USE SIGNAL ;
    PORT
      LAYER M5 ;
        RECT  18.672 21.408 18.696 21.6 ;
    END
  END o0[84]
  PIN o0[85]
    DIRECTION OUTPUT ;
    USE SIGNAL ;
    PORT
      LAYER M5 ;
        RECT  18.816 21.408 18.84 21.6 ;
    END
  END o0[85]
  PIN o0[86]
    DIRECTION OUTPUT ;
    USE SIGNAL ;
    PORT
      LAYER M5 ;
        RECT  19.008 21.408 19.032 21.6 ;
    END
  END o0[86]
  PIN o0[87]
    DIRECTION OUTPUT ;
    USE SIGNAL ;
    PORT
      LAYER M5 ;
        RECT  19.152 21.408 19.176 21.6 ;
    END
  END o0[87]
  PIN o0[88]
    DIRECTION OUTPUT ;
    USE SIGNAL ;
    PORT
      LAYER M5 ;
        RECT  19.344 21.408 19.368 21.6 ;
    END
  END o0[88]
  PIN o0[89]
    DIRECTION OUTPUT ;
    USE SIGNAL ;
    PORT
      LAYER M5 ;
        RECT  19.488 21.408 19.512 21.6 ;
    END
  END o0[89]
  PIN o0[8]
    DIRECTION OUTPUT ;
    USE SIGNAL ;
    PORT
      LAYER M5 ;
        RECT  5.856 21.408 5.88 21.6 ;
    END
  END o0[8]
  PIN o0[90]
    DIRECTION OUTPUT ;
    USE SIGNAL ;
    PORT
      LAYER M5 ;
        RECT  19.68 21.408 19.704 21.6 ;
    END
  END o0[90]
  PIN o0[91]
    DIRECTION OUTPUT ;
    USE SIGNAL ;
    PORT
      LAYER M5 ;
        RECT  19.824 21.408 19.848 21.6 ;
    END
  END o0[91]
  PIN o0[92]
    DIRECTION OUTPUT ;
    USE SIGNAL ;
    PORT
      LAYER M5 ;
        RECT  19.968 21.408 19.992 21.6 ;
    END
  END o0[92]
  PIN o0[93]
    DIRECTION OUTPUT ;
    USE SIGNAL ;
    PORT
      LAYER M5 ;
        RECT  20.16 21.408 20.184 21.6 ;
    END
  END o0[93]
  PIN o0[94]
    DIRECTION OUTPUT ;
    USE SIGNAL ;
    PORT
      LAYER M5 ;
        RECT  20.304 21.408 20.328 21.6 ;
    END
  END o0[94]
  PIN o0[95]
    DIRECTION OUTPUT ;
    USE SIGNAL ;
    PORT
      LAYER M5 ;
        RECT  20.496 21.408 20.52 21.6 ;
    END
  END o0[95]
  PIN o0[96]
    DIRECTION OUTPUT ;
    USE SIGNAL ;
    PORT
      LAYER M5 ;
        RECT  20.64 21.408 20.664 21.6 ;
    END
  END o0[96]
  PIN o0[97]
    DIRECTION OUTPUT ;
    USE SIGNAL ;
    PORT
      LAYER M5 ;
        RECT  20.832 21.408 20.856 21.6 ;
    END
  END o0[97]
  PIN o0[98]
    DIRECTION OUTPUT ;
    USE SIGNAL ;
    PORT
      LAYER M5 ;
        RECT  20.976 21.408 21 21.6 ;
    END
  END o0[98]
  PIN o0[99]
    DIRECTION OUTPUT ;
    USE SIGNAL ;
    PORT
      LAYER M5 ;
        RECT  21.168 21.408 21.192 21.6 ;
    END
  END o0[99]
  PIN o0[9]
    DIRECTION OUTPUT ;
    USE SIGNAL ;
    PORT
      LAYER M5 ;
        RECT  6 21.408 6.024 21.6 ;
    END
  END o0[9]
  PIN o1[0]
    DIRECTION OUTPUT ;
    USE SIGNAL ;
    PORT
      LAYER M5 ;
        RECT  27.552 21.408 27.576 21.6 ;
    END
  END o1[0]
  PIN o1[100]
    DIRECTION OUTPUT ;
    USE SIGNAL ;
    PORT
      LAYER M5 ;
        RECT  44.352 21.408 44.376 21.6 ;
    END
  END o1[100]
  PIN o1[101]
    DIRECTION OUTPUT ;
    USE SIGNAL ;
    PORT
      LAYER M5 ;
        RECT  44.544 21.408 44.568 21.6 ;
    END
  END o1[101]
  PIN o1[102]
    DIRECTION OUTPUT ;
    USE SIGNAL ;
    PORT
      LAYER M5 ;
        RECT  44.688 21.408 44.712 21.6 ;
    END
  END o1[102]
  PIN o1[103]
    DIRECTION OUTPUT ;
    USE SIGNAL ;
    PORT
      LAYER M5 ;
        RECT  44.88 21.408 44.904 21.6 ;
    END
  END o1[103]
  PIN o1[104]
    DIRECTION OUTPUT ;
    USE SIGNAL ;
    PORT
      LAYER M5 ;
        RECT  45.024 21.408 45.048 21.6 ;
    END
  END o1[104]
  PIN o1[105]
    DIRECTION OUTPUT ;
    USE SIGNAL ;
    PORT
      LAYER M5 ;
        RECT  45.216 21.408 45.24 21.6 ;
    END
  END o1[105]
  PIN o1[106]
    DIRECTION OUTPUT ;
    USE SIGNAL ;
    PORT
      LAYER M5 ;
        RECT  45.36 21.408 45.384 21.6 ;
    END
  END o1[106]
  PIN o1[107]
    DIRECTION OUTPUT ;
    USE SIGNAL ;
    PORT
      LAYER M5 ;
        RECT  45.504 21.408 45.528 21.6 ;
    END
  END o1[107]
  PIN o1[108]
    DIRECTION OUTPUT ;
    USE SIGNAL ;
    PORT
      LAYER M5 ;
        RECT  45.696 21.408 45.72 21.6 ;
    END
  END o1[108]
  PIN o1[109]
    DIRECTION OUTPUT ;
    USE SIGNAL ;
    PORT
      LAYER M5 ;
        RECT  45.84 21.408 45.864 21.6 ;
    END
  END o1[109]
  PIN o1[10]
    DIRECTION OUTPUT ;
    USE SIGNAL ;
    PORT
      LAYER M5 ;
        RECT  29.232 21.408 29.256 21.6 ;
    END
  END o1[10]
  PIN o1[110]
    DIRECTION OUTPUT ;
    USE SIGNAL ;
    PORT
      LAYER M5 ;
        RECT  46.032 21.408 46.056 21.6 ;
    END
  END o1[110]
  PIN o1[111]
    DIRECTION OUTPUT ;
    USE SIGNAL ;
    PORT
      LAYER M5 ;
        RECT  46.176 21.408 46.2 21.6 ;
    END
  END o1[111]
  PIN o1[112]
    DIRECTION OUTPUT ;
    USE SIGNAL ;
    PORT
      LAYER M5 ;
        RECT  46.368 21.408 46.392 21.6 ;
    END
  END o1[112]
  PIN o1[113]
    DIRECTION OUTPUT ;
    USE SIGNAL ;
    PORT
      LAYER M5 ;
        RECT  46.512 21.408 46.536 21.6 ;
    END
  END o1[113]
  PIN o1[114]
    DIRECTION OUTPUT ;
    USE SIGNAL ;
    PORT
      LAYER M5 ;
        RECT  46.704 21.408 46.728 21.6 ;
    END
  END o1[114]
  PIN o1[115]
    DIRECTION OUTPUT ;
    USE SIGNAL ;
    PORT
      LAYER M5 ;
        RECT  46.848 21.408 46.872 21.6 ;
    END
  END o1[115]
  PIN o1[116]
    DIRECTION OUTPUT ;
    USE SIGNAL ;
    PORT
      LAYER M5 ;
        RECT  47.04 21.408 47.064 21.6 ;
    END
  END o1[116]
  PIN o1[117]
    DIRECTION OUTPUT ;
    USE SIGNAL ;
    PORT
      LAYER M5 ;
        RECT  47.184 21.408 47.208 21.6 ;
    END
  END o1[117]
  PIN o1[118]
    DIRECTION OUTPUT ;
    USE SIGNAL ;
    PORT
      LAYER M5 ;
        RECT  47.376 21.408 47.4 21.6 ;
    END
  END o1[118]
  PIN o1[119]
    DIRECTION OUTPUT ;
    USE SIGNAL ;
    PORT
      LAYER M5 ;
        RECT  47.52 21.408 47.544 21.6 ;
    END
  END o1[119]
  PIN o1[11]
    DIRECTION OUTPUT ;
    USE SIGNAL ;
    PORT
      LAYER M5 ;
        RECT  29.376 21.408 29.4 21.6 ;
    END
  END o1[11]
  PIN o1[120]
    DIRECTION OUTPUT ;
    USE SIGNAL ;
    PORT
      LAYER M5 ;
        RECT  47.712 21.408 47.736 21.6 ;
    END
  END o1[120]
  PIN o1[121]
    DIRECTION OUTPUT ;
    USE SIGNAL ;
    PORT
      LAYER M5 ;
        RECT  47.856 21.408 47.88 21.6 ;
    END
  END o1[121]
  PIN o1[122]
    DIRECTION OUTPUT ;
    USE SIGNAL ;
    PORT
      LAYER M5 ;
        RECT  48 21.408 48.024 21.6 ;
    END
  END o1[122]
  PIN o1[123]
    DIRECTION OUTPUT ;
    USE SIGNAL ;
    PORT
      LAYER M5 ;
        RECT  48.192 21.408 48.216 21.6 ;
    END
  END o1[123]
  PIN o1[124]
    DIRECTION OUTPUT ;
    USE SIGNAL ;
    PORT
      LAYER M5 ;
        RECT  48.336 21.408 48.36 21.6 ;
    END
  END o1[124]
  PIN o1[125]
    DIRECTION OUTPUT ;
    USE SIGNAL ;
    PORT
      LAYER M5 ;
        RECT  48.528 21.408 48.552 21.6 ;
    END
  END o1[125]
  PIN o1[126]
    DIRECTION OUTPUT ;
    USE SIGNAL ;
    PORT
      LAYER M5 ;
        RECT  48.672 21.408 48.696 21.6 ;
    END
  END o1[126]
  PIN o1[127]
    DIRECTION OUTPUT ;
    USE SIGNAL ;
    PORT
      LAYER M5 ;
        RECT  48.864 21.408 48.888 21.6 ;
    END
  END o1[127]
  PIN o1[128]
    DIRECTION OUTPUT ;
    USE SIGNAL ;
    PORT
      LAYER M5 ;
        RECT  49.008 21.408 49.032 21.6 ;
    END
  END o1[128]
  PIN o1[129]
    DIRECTION OUTPUT ;
    USE SIGNAL ;
    PORT
      LAYER M5 ;
        RECT  49.2 21.408 49.224 21.6 ;
    END
  END o1[129]
  PIN o1[12]
    DIRECTION OUTPUT ;
    USE SIGNAL ;
    PORT
      LAYER M5 ;
        RECT  29.568 21.408 29.592 21.6 ;
    END
  END o1[12]
  PIN o1[130]
    DIRECTION OUTPUT ;
    USE SIGNAL ;
    PORT
      LAYER M5 ;
        RECT  49.344 21.408 49.368 21.6 ;
    END
  END o1[130]
  PIN o1[131]
    DIRECTION OUTPUT ;
    USE SIGNAL ;
    PORT
      LAYER M5 ;
        RECT  49.536 21.408 49.56 21.6 ;
    END
  END o1[131]
  PIN o1[132]
    DIRECTION OUTPUT ;
    USE SIGNAL ;
    PORT
      LAYER M5 ;
        RECT  49.68 21.408 49.704 21.6 ;
    END
  END o1[132]
  PIN o1[133]
    DIRECTION OUTPUT ;
    USE SIGNAL ;
    PORT
      LAYER M5 ;
        RECT  49.872 21.408 49.896 21.6 ;
    END
  END o1[133]
  PIN o1[134]
    DIRECTION OUTPUT ;
    USE SIGNAL ;
    PORT
      LAYER M5 ;
        RECT  50.016 21.408 50.04 21.6 ;
    END
  END o1[134]
  PIN o1[135]
    DIRECTION OUTPUT ;
    USE SIGNAL ;
    PORT
      LAYER M5 ;
        RECT  50.208 21.408 50.232 21.6 ;
    END
  END o1[135]
  PIN o1[13]
    DIRECTION OUTPUT ;
    USE SIGNAL ;
    PORT
      LAYER M5 ;
        RECT  29.712 21.408 29.736 21.6 ;
    END
  END o1[13]
  PIN o1[14]
    DIRECTION OUTPUT ;
    USE SIGNAL ;
    PORT
      LAYER M5 ;
        RECT  29.856 21.408 29.88 21.6 ;
    END
  END o1[14]
  PIN o1[15]
    DIRECTION OUTPUT ;
    USE SIGNAL ;
    PORT
      LAYER M5 ;
        RECT  30.048 21.408 30.072 21.6 ;
    END
  END o1[15]
  PIN o1[16]
    DIRECTION OUTPUT ;
    USE SIGNAL ;
    PORT
      LAYER M5 ;
        RECT  30.192 21.408 30.216 21.6 ;
    END
  END o1[16]
  PIN o1[17]
    DIRECTION OUTPUT ;
    USE SIGNAL ;
    PORT
      LAYER M5 ;
        RECT  30.384 21.408 30.408 21.6 ;
    END
  END o1[17]
  PIN o1[18]
    DIRECTION OUTPUT ;
    USE SIGNAL ;
    PORT
      LAYER M5 ;
        RECT  30.528 21.408 30.552 21.6 ;
    END
  END o1[18]
  PIN o1[19]
    DIRECTION OUTPUT ;
    USE SIGNAL ;
    PORT
      LAYER M5 ;
        RECT  30.72 21.408 30.744 21.6 ;
    END
  END o1[19]
  PIN o1[1]
    DIRECTION OUTPUT ;
    USE SIGNAL ;
    PORT
      LAYER M5 ;
        RECT  27.696 21.408 27.72 21.6 ;
    END
  END o1[1]
  PIN o1[20]
    DIRECTION OUTPUT ;
    USE SIGNAL ;
    PORT
      LAYER M5 ;
        RECT  30.864 21.408 30.888 21.6 ;
    END
  END o1[20]
  PIN o1[21]
    DIRECTION OUTPUT ;
    USE SIGNAL ;
    PORT
      LAYER M5 ;
        RECT  31.056 21.408 31.08 21.6 ;
    END
  END o1[21]
  PIN o1[22]
    DIRECTION OUTPUT ;
    USE SIGNAL ;
    PORT
      LAYER M5 ;
        RECT  31.2 21.408 31.224 21.6 ;
    END
  END o1[22]
  PIN o1[23]
    DIRECTION OUTPUT ;
    USE SIGNAL ;
    PORT
      LAYER M5 ;
        RECT  31.392 21.408 31.416 21.6 ;
    END
  END o1[23]
  PIN o1[24]
    DIRECTION OUTPUT ;
    USE SIGNAL ;
    PORT
      LAYER M5 ;
        RECT  31.536 21.408 31.56 21.6 ;
    END
  END o1[24]
  PIN o1[25]
    DIRECTION OUTPUT ;
    USE SIGNAL ;
    PORT
      LAYER M5 ;
        RECT  31.728 21.408 31.752 21.6 ;
    END
  END o1[25]
  PIN o1[26]
    DIRECTION OUTPUT ;
    USE SIGNAL ;
    PORT
      LAYER M5 ;
        RECT  31.872 21.408 31.896 21.6 ;
    END
  END o1[26]
  PIN o1[27]
    DIRECTION OUTPUT ;
    USE SIGNAL ;
    PORT
      LAYER M5 ;
        RECT  32.064 21.408 32.088 21.6 ;
    END
  END o1[27]
  PIN o1[28]
    DIRECTION OUTPUT ;
    USE SIGNAL ;
    PORT
      LAYER M5 ;
        RECT  32.208 21.408 32.232 21.6 ;
    END
  END o1[28]
  PIN o1[29]
    DIRECTION OUTPUT ;
    USE SIGNAL ;
    PORT
      LAYER M5 ;
        RECT  32.352 21.408 32.376 21.6 ;
    END
  END o1[29]
  PIN o1[2]
    DIRECTION OUTPUT ;
    USE SIGNAL ;
    PORT
      LAYER M5 ;
        RECT  27.888 21.408 27.912 21.6 ;
    END
  END o1[2]
  PIN o1[30]
    DIRECTION OUTPUT ;
    USE SIGNAL ;
    PORT
      LAYER M5 ;
        RECT  32.544 21.408 32.568 21.6 ;
    END
  END o1[30]
  PIN o1[31]
    DIRECTION OUTPUT ;
    USE SIGNAL ;
    PORT
      LAYER M5 ;
        RECT  32.688 21.408 32.712 21.6 ;
    END
  END o1[31]
  PIN o1[32]
    DIRECTION OUTPUT ;
    USE SIGNAL ;
    PORT
      LAYER M5 ;
        RECT  32.88 21.408 32.904 21.6 ;
    END
  END o1[32]
  PIN o1[33]
    DIRECTION OUTPUT ;
    USE SIGNAL ;
    PORT
      LAYER M5 ;
        RECT  33.024 21.408 33.048 21.6 ;
    END
  END o1[33]
  PIN o1[34]
    DIRECTION OUTPUT ;
    USE SIGNAL ;
    PORT
      LAYER M5 ;
        RECT  33.216 21.408 33.24 21.6 ;
    END
  END o1[34]
  PIN o1[35]
    DIRECTION OUTPUT ;
    USE SIGNAL ;
    PORT
      LAYER M5 ;
        RECT  33.36 21.408 33.384 21.6 ;
    END
  END o1[35]
  PIN o1[36]
    DIRECTION OUTPUT ;
    USE SIGNAL ;
    PORT
      LAYER M5 ;
        RECT  33.552 21.408 33.576 21.6 ;
    END
  END o1[36]
  PIN o1[37]
    DIRECTION OUTPUT ;
    USE SIGNAL ;
    PORT
      LAYER M5 ;
        RECT  33.696 21.408 33.72 21.6 ;
    END
  END o1[37]
  PIN o1[38]
    DIRECTION OUTPUT ;
    USE SIGNAL ;
    PORT
      LAYER M5 ;
        RECT  33.888 21.408 33.912 21.6 ;
    END
  END o1[38]
  PIN o1[39]
    DIRECTION OUTPUT ;
    USE SIGNAL ;
    PORT
      LAYER M5 ;
        RECT  34.032 21.408 34.056 21.6 ;
    END
  END o1[39]
  PIN o1[3]
    DIRECTION OUTPUT ;
    USE SIGNAL ;
    PORT
      LAYER M5 ;
        RECT  28.032 21.408 28.056 21.6 ;
    END
  END o1[3]
  PIN o1[40]
    DIRECTION OUTPUT ;
    USE SIGNAL ;
    PORT
      LAYER M5 ;
        RECT  34.224 21.408 34.248 21.6 ;
    END
  END o1[40]
  PIN o1[41]
    DIRECTION OUTPUT ;
    USE SIGNAL ;
    PORT
      LAYER M5 ;
        RECT  34.368 21.408 34.392 21.6 ;
    END
  END o1[41]
  PIN o1[42]
    DIRECTION OUTPUT ;
    USE SIGNAL ;
    PORT
      LAYER M5 ;
        RECT  34.56 21.408 34.584 21.6 ;
    END
  END o1[42]
  PIN o1[43]
    DIRECTION OUTPUT ;
    USE SIGNAL ;
    PORT
      LAYER M5 ;
        RECT  34.704 21.408 34.728 21.6 ;
    END
  END o1[43]
  PIN o1[44]
    DIRECTION OUTPUT ;
    USE SIGNAL ;
    PORT
      LAYER M5 ;
        RECT  34.896 21.408 34.92 21.6 ;
    END
  END o1[44]
  PIN o1[45]
    DIRECTION OUTPUT ;
    USE SIGNAL ;
    PORT
      LAYER M5 ;
        RECT  35.04 21.408 35.064 21.6 ;
    END
  END o1[45]
  PIN o1[46]
    DIRECTION OUTPUT ;
    USE SIGNAL ;
    PORT
      LAYER M5 ;
        RECT  35.184 21.408 35.208 21.6 ;
    END
  END o1[46]
  PIN o1[47]
    DIRECTION OUTPUT ;
    USE SIGNAL ;
    PORT
      LAYER M5 ;
        RECT  35.376 21.408 35.4 21.6 ;
    END
  END o1[47]
  PIN o1[48]
    DIRECTION OUTPUT ;
    USE SIGNAL ;
    PORT
      LAYER M5 ;
        RECT  35.52 21.408 35.544 21.6 ;
    END
  END o1[48]
  PIN o1[49]
    DIRECTION OUTPUT ;
    USE SIGNAL ;
    PORT
      LAYER M5 ;
        RECT  35.712 21.408 35.736 21.6 ;
    END
  END o1[49]
  PIN o1[4]
    DIRECTION OUTPUT ;
    USE SIGNAL ;
    PORT
      LAYER M5 ;
        RECT  28.224 21.408 28.248 21.6 ;
    END
  END o1[4]
  PIN o1[50]
    DIRECTION OUTPUT ;
    USE SIGNAL ;
    PORT
      LAYER M5 ;
        RECT  35.856 21.408 35.88 21.6 ;
    END
  END o1[50]
  PIN o1[51]
    DIRECTION OUTPUT ;
    USE SIGNAL ;
    PORT
      LAYER M5 ;
        RECT  36.048 21.408 36.072 21.6 ;
    END
  END o1[51]
  PIN o1[52]
    DIRECTION OUTPUT ;
    USE SIGNAL ;
    PORT
      LAYER M5 ;
        RECT  36.192 21.408 36.216 21.6 ;
    END
  END o1[52]
  PIN o1[53]
    DIRECTION OUTPUT ;
    USE SIGNAL ;
    PORT
      LAYER M5 ;
        RECT  36.384 21.408 36.408 21.6 ;
    END
  END o1[53]
  PIN o1[54]
    DIRECTION OUTPUT ;
    USE SIGNAL ;
    PORT
      LAYER M5 ;
        RECT  36.528 21.408 36.552 21.6 ;
    END
  END o1[54]
  PIN o1[55]
    DIRECTION OUTPUT ;
    USE SIGNAL ;
    PORT
      LAYER M5 ;
        RECT  36.72 21.408 36.744 21.6 ;
    END
  END o1[55]
  PIN o1[56]
    DIRECTION OUTPUT ;
    USE SIGNAL ;
    PORT
      LAYER M5 ;
        RECT  36.864 21.408 36.888 21.6 ;
    END
  END o1[56]
  PIN o1[57]
    DIRECTION OUTPUT ;
    USE SIGNAL ;
    PORT
      LAYER M5 ;
        RECT  37.056 21.408 37.08 21.6 ;
    END
  END o1[57]
  PIN o1[58]
    DIRECTION OUTPUT ;
    USE SIGNAL ;
    PORT
      LAYER M5 ;
        RECT  37.2 21.408 37.224 21.6 ;
    END
  END o1[58]
  PIN o1[59]
    DIRECTION OUTPUT ;
    USE SIGNAL ;
    PORT
      LAYER M5 ;
        RECT  37.392 21.408 37.416 21.6 ;
    END
  END o1[59]
  PIN o1[5]
    DIRECTION OUTPUT ;
    USE SIGNAL ;
    PORT
      LAYER M5 ;
        RECT  28.368 21.408 28.392 21.6 ;
    END
  END o1[5]
  PIN o1[60]
    DIRECTION OUTPUT ;
    USE SIGNAL ;
    PORT
      LAYER M5 ;
        RECT  37.536 21.408 37.56 21.6 ;
    END
  END o1[60]
  PIN o1[61]
    DIRECTION OUTPUT ;
    USE SIGNAL ;
    PORT
      LAYER M5 ;
        RECT  37.68 21.408 37.704 21.6 ;
    END
  END o1[61]
  PIN o1[62]
    DIRECTION OUTPUT ;
    USE SIGNAL ;
    PORT
      LAYER M5 ;
        RECT  37.872 21.408 37.896 21.6 ;
    END
  END o1[62]
  PIN o1[63]
    DIRECTION OUTPUT ;
    USE SIGNAL ;
    PORT
      LAYER M5 ;
        RECT  38.016 21.408 38.04 21.6 ;
    END
  END o1[63]
  PIN o1[64]
    DIRECTION OUTPUT ;
    USE SIGNAL ;
    PORT
      LAYER M5 ;
        RECT  38.208 21.408 38.232 21.6 ;
    END
  END o1[64]
  PIN o1[65]
    DIRECTION OUTPUT ;
    USE SIGNAL ;
    PORT
      LAYER M5 ;
        RECT  38.352 21.408 38.376 21.6 ;
    END
  END o1[65]
  PIN o1[66]
    DIRECTION OUTPUT ;
    USE SIGNAL ;
    PORT
      LAYER M5 ;
        RECT  38.544 21.408 38.568 21.6 ;
    END
  END o1[66]
  PIN o1[67]
    DIRECTION OUTPUT ;
    USE SIGNAL ;
    PORT
      LAYER M5 ;
        RECT  38.688 21.408 38.712 21.6 ;
    END
  END o1[67]
  PIN o1[68]
    DIRECTION OUTPUT ;
    USE SIGNAL ;
    PORT
      LAYER M5 ;
        RECT  39.024 21.408 39.048 21.6 ;
    END
  END o1[68]
  PIN o1[69]
    DIRECTION OUTPUT ;
    USE SIGNAL ;
    PORT
      LAYER M5 ;
        RECT  39.216 21.408 39.24 21.6 ;
    END
  END o1[69]
  PIN o1[6]
    DIRECTION OUTPUT ;
    USE SIGNAL ;
    PORT
      LAYER M5 ;
        RECT  28.56 21.408 28.584 21.6 ;
    END
  END o1[6]
  PIN o1[70]
    DIRECTION OUTPUT ;
    USE SIGNAL ;
    PORT
      LAYER M5 ;
        RECT  39.36 21.408 39.384 21.6 ;
    END
  END o1[70]
  PIN o1[71]
    DIRECTION OUTPUT ;
    USE SIGNAL ;
    PORT
      LAYER M5 ;
        RECT  39.552 21.408 39.576 21.6 ;
    END
  END o1[71]
  PIN o1[72]
    DIRECTION OUTPUT ;
    USE SIGNAL ;
    PORT
      LAYER M5 ;
        RECT  39.696 21.408 39.72 21.6 ;
    END
  END o1[72]
  PIN o1[73]
    DIRECTION OUTPUT ;
    USE SIGNAL ;
    PORT
      LAYER M5 ;
        RECT  39.888 21.408 39.912 21.6 ;
    END
  END o1[73]
  PIN o1[74]
    DIRECTION OUTPUT ;
    USE SIGNAL ;
    PORT
      LAYER M5 ;
        RECT  40.032 21.408 40.056 21.6 ;
    END
  END o1[74]
  PIN o1[75]
    DIRECTION OUTPUT ;
    USE SIGNAL ;
    PORT
      LAYER M5 ;
        RECT  40.176 21.408 40.2 21.6 ;
    END
  END o1[75]
  PIN o1[76]
    DIRECTION OUTPUT ;
    USE SIGNAL ;
    PORT
      LAYER M5 ;
        RECT  40.368 21.408 40.392 21.6 ;
    END
  END o1[76]
  PIN o1[77]
    DIRECTION OUTPUT ;
    USE SIGNAL ;
    PORT
      LAYER M5 ;
        RECT  40.512 21.408 40.536 21.6 ;
    END
  END o1[77]
  PIN o1[78]
    DIRECTION OUTPUT ;
    USE SIGNAL ;
    PORT
      LAYER M5 ;
        RECT  40.704 21.408 40.728 21.6 ;
    END
  END o1[78]
  PIN o1[79]
    DIRECTION OUTPUT ;
    USE SIGNAL ;
    PORT
      LAYER M5 ;
        RECT  40.848 21.408 40.872 21.6 ;
    END
  END o1[79]
  PIN o1[7]
    DIRECTION OUTPUT ;
    USE SIGNAL ;
    PORT
      LAYER M5 ;
        RECT  28.704 21.408 28.728 21.6 ;
    END
  END o1[7]
  PIN o1[80]
    DIRECTION OUTPUT ;
    USE SIGNAL ;
    PORT
      LAYER M5 ;
        RECT  41.04 21.408 41.064 21.6 ;
    END
  END o1[80]
  PIN o1[81]
    DIRECTION OUTPUT ;
    USE SIGNAL ;
    PORT
      LAYER M5 ;
        RECT  41.184 21.408 41.208 21.6 ;
    END
  END o1[81]
  PIN o1[82]
    DIRECTION OUTPUT ;
    USE SIGNAL ;
    PORT
      LAYER M5 ;
        RECT  41.376 21.408 41.4 21.6 ;
    END
  END o1[82]
  PIN o1[83]
    DIRECTION OUTPUT ;
    USE SIGNAL ;
    PORT
      LAYER M5 ;
        RECT  41.52 21.408 41.544 21.6 ;
    END
  END o1[83]
  PIN o1[84]
    DIRECTION OUTPUT ;
    USE SIGNAL ;
    PORT
      LAYER M5 ;
        RECT  41.712 21.408 41.736 21.6 ;
    END
  END o1[84]
  PIN o1[85]
    DIRECTION OUTPUT ;
    USE SIGNAL ;
    PORT
      LAYER M5 ;
        RECT  41.856 21.408 41.88 21.6 ;
    END
  END o1[85]
  PIN o1[86]
    DIRECTION OUTPUT ;
    USE SIGNAL ;
    PORT
      LAYER M5 ;
        RECT  42.048 21.408 42.072 21.6 ;
    END
  END o1[86]
  PIN o1[87]
    DIRECTION OUTPUT ;
    USE SIGNAL ;
    PORT
      LAYER M5 ;
        RECT  42.192 21.408 42.216 21.6 ;
    END
  END o1[87]
  PIN o1[88]
    DIRECTION OUTPUT ;
    USE SIGNAL ;
    PORT
      LAYER M5 ;
        RECT  42.384 21.408 42.408 21.6 ;
    END
  END o1[88]
  PIN o1[89]
    DIRECTION OUTPUT ;
    USE SIGNAL ;
    PORT
      LAYER M5 ;
        RECT  42.528 21.408 42.552 21.6 ;
    END
  END o1[89]
  PIN o1[8]
    DIRECTION OUTPUT ;
    USE SIGNAL ;
    PORT
      LAYER M5 ;
        RECT  28.896 21.408 28.92 21.6 ;
    END
  END o1[8]
  PIN o1[90]
    DIRECTION OUTPUT ;
    USE SIGNAL ;
    PORT
      LAYER M5 ;
        RECT  42.72 21.408 42.744 21.6 ;
    END
  END o1[90]
  PIN o1[91]
    DIRECTION OUTPUT ;
    USE SIGNAL ;
    PORT
      LAYER M5 ;
        RECT  42.864 21.408 42.888 21.6 ;
    END
  END o1[91]
  PIN o1[92]
    DIRECTION OUTPUT ;
    USE SIGNAL ;
    PORT
      LAYER M5 ;
        RECT  43.008 21.408 43.032 21.6 ;
    END
  END o1[92]
  PIN o1[93]
    DIRECTION OUTPUT ;
    USE SIGNAL ;
    PORT
      LAYER M5 ;
        RECT  43.2 21.408 43.224 21.6 ;
    END
  END o1[93]
  PIN o1[94]
    DIRECTION OUTPUT ;
    USE SIGNAL ;
    PORT
      LAYER M5 ;
        RECT  43.344 21.408 43.368 21.6 ;
    END
  END o1[94]
  PIN o1[95]
    DIRECTION OUTPUT ;
    USE SIGNAL ;
    PORT
      LAYER M5 ;
        RECT  43.536 21.408 43.56 21.6 ;
    END
  END o1[95]
  PIN o1[96]
    DIRECTION OUTPUT ;
    USE SIGNAL ;
    PORT
      LAYER M5 ;
        RECT  43.68 21.408 43.704 21.6 ;
    END
  END o1[96]
  PIN o1[97]
    DIRECTION OUTPUT ;
    USE SIGNAL ;
    PORT
      LAYER M5 ;
        RECT  43.872 21.408 43.896 21.6 ;
    END
  END o1[97]
  PIN o1[98]
    DIRECTION OUTPUT ;
    USE SIGNAL ;
    PORT
      LAYER M5 ;
        RECT  44.016 21.408 44.04 21.6 ;
    END
  END o1[98]
  PIN o1[99]
    DIRECTION OUTPUT ;
    USE SIGNAL ;
    PORT
      LAYER M5 ;
        RECT  44.208 21.408 44.232 21.6 ;
    END
  END o1[99]
  PIN o1[9]
    DIRECTION OUTPUT ;
    USE SIGNAL ;
    PORT
      LAYER M5 ;
        RECT  29.04 21.408 29.064 21.6 ;
    END
  END o1[9]
  PIN o2[0]
    DIRECTION OUTPUT ;
    USE SIGNAL ;
    PORT
      LAYER M5 ;
        RECT  39.072 0 39.096 0.192 ;
    END
  END o2[0]
  PIN o2[100]
    DIRECTION OUTPUT ;
    USE SIGNAL ;
    PORT
      LAYER M5 ;
        RECT  64.416 0 64.44 0.192 ;
    END
  END o2[100]
  PIN o2[101]
    DIRECTION OUTPUT ;
    USE SIGNAL ;
    PORT
      LAYER M5 ;
        RECT  64.704 0 64.728 0.192 ;
    END
  END o2[101]
  PIN o2[102]
    DIRECTION OUTPUT ;
    USE SIGNAL ;
    PORT
      LAYER M5 ;
        RECT  64.944 0 64.968 0.192 ;
    END
  END o2[102]
  PIN o2[103]
    DIRECTION OUTPUT ;
    USE SIGNAL ;
    PORT
      LAYER M5 ;
        RECT  65.184 0 65.208 0.192 ;
    END
  END o2[103]
  PIN o2[104]
    DIRECTION OUTPUT ;
    USE SIGNAL ;
    PORT
      LAYER M5 ;
        RECT  65.424 0 65.448 0.192 ;
    END
  END o2[104]
  PIN o2[105]
    DIRECTION OUTPUT ;
    USE SIGNAL ;
    PORT
      LAYER M5 ;
        RECT  65.712 0 65.736 0.192 ;
    END
  END o2[105]
  PIN o2[106]
    DIRECTION OUTPUT ;
    USE SIGNAL ;
    PORT
      LAYER M5 ;
        RECT  65.952 0 65.976 0.192 ;
    END
  END o2[106]
  PIN o2[107]
    DIRECTION OUTPUT ;
    USE SIGNAL ;
    PORT
      LAYER M5 ;
        RECT  66.192 0 66.216 0.192 ;
    END
  END o2[107]
  PIN o2[108]
    DIRECTION OUTPUT ;
    USE SIGNAL ;
    PORT
      LAYER M5 ;
        RECT  66.432 0 66.456 0.192 ;
    END
  END o2[108]
  PIN o2[109]
    DIRECTION OUTPUT ;
    USE SIGNAL ;
    PORT
      LAYER M5 ;
        RECT  66.72 0 66.744 0.192 ;
    END
  END o2[109]
  PIN o2[10]
    DIRECTION OUTPUT ;
    USE SIGNAL ;
    PORT
      LAYER M5 ;
        RECT  41.568 0 41.592 0.192 ;
    END
  END o2[10]
  PIN o2[110]
    DIRECTION OUTPUT ;
    USE SIGNAL ;
    PORT
      LAYER M5 ;
        RECT  66.96 0 66.984 0.192 ;
    END
  END o2[110]
  PIN o2[111]
    DIRECTION OUTPUT ;
    USE SIGNAL ;
    PORT
      LAYER M5 ;
        RECT  67.2 0 67.224 0.192 ;
    END
  END o2[111]
  PIN o2[112]
    DIRECTION OUTPUT ;
    USE SIGNAL ;
    PORT
      LAYER M5 ;
        RECT  67.44 0 67.464 0.192 ;
    END
  END o2[112]
  PIN o2[113]
    DIRECTION OUTPUT ;
    USE SIGNAL ;
    PORT
      LAYER M5 ;
        RECT  67.68 0 67.704 0.192 ;
    END
  END o2[113]
  PIN o2[114]
    DIRECTION OUTPUT ;
    USE SIGNAL ;
    PORT
      LAYER M5 ;
        RECT  67.968 0 67.992 0.192 ;
    END
  END o2[114]
  PIN o2[115]
    DIRECTION OUTPUT ;
    USE SIGNAL ;
    PORT
      LAYER M5 ;
        RECT  68.208 0 68.232 0.192 ;
    END
  END o2[115]
  PIN o2[116]
    DIRECTION OUTPUT ;
    USE SIGNAL ;
    PORT
      LAYER M5 ;
        RECT  68.448 0 68.472 0.192 ;
    END
  END o2[116]
  PIN o2[117]
    DIRECTION OUTPUT ;
    USE SIGNAL ;
    PORT
      LAYER M5 ;
        RECT  68.688 0 68.712 0.192 ;
    END
  END o2[117]
  PIN o2[118]
    DIRECTION OUTPUT ;
    USE SIGNAL ;
    PORT
      LAYER M5 ;
        RECT  68.976 0 69 0.192 ;
    END
  END o2[118]
  PIN o2[119]
    DIRECTION OUTPUT ;
    USE SIGNAL ;
    PORT
      LAYER M5 ;
        RECT  69.216 0 69.24 0.192 ;
    END
  END o2[119]
  PIN o2[11]
    DIRECTION OUTPUT ;
    USE SIGNAL ;
    PORT
      LAYER M5 ;
        RECT  41.808 0 41.832 0.192 ;
    END
  END o2[11]
  PIN o2[120]
    DIRECTION OUTPUT ;
    USE SIGNAL ;
    PORT
      LAYER M5 ;
        RECT  69.456 0 69.48 0.192 ;
    END
  END o2[120]
  PIN o2[121]
    DIRECTION OUTPUT ;
    USE SIGNAL ;
    PORT
      LAYER M5 ;
        RECT  69.696 0 69.72 0.192 ;
    END
  END o2[121]
  PIN o2[122]
    DIRECTION OUTPUT ;
    USE SIGNAL ;
    PORT
      LAYER M5 ;
        RECT  69.984 0 70.008 0.192 ;
    END
  END o2[122]
  PIN o2[123]
    DIRECTION OUTPUT ;
    USE SIGNAL ;
    PORT
      LAYER M5 ;
        RECT  70.224 0 70.248 0.192 ;
    END
  END o2[123]
  PIN o2[124]
    DIRECTION OUTPUT ;
    USE SIGNAL ;
    PORT
      LAYER M5 ;
        RECT  70.464 0 70.488 0.192 ;
    END
  END o2[124]
  PIN o2[125]
    DIRECTION OUTPUT ;
    USE SIGNAL ;
    PORT
      LAYER M5 ;
        RECT  70.704 0 70.728 0.192 ;
    END
  END o2[125]
  PIN o2[126]
    DIRECTION OUTPUT ;
    USE SIGNAL ;
    PORT
      LAYER M5 ;
        RECT  70.944 0 70.968 0.192 ;
    END
  END o2[126]
  PIN o2[127]
    DIRECTION OUTPUT ;
    USE SIGNAL ;
    PORT
      LAYER M5 ;
        RECT  71.232 0 71.256 0.192 ;
    END
  END o2[127]
  PIN o2[128]
    DIRECTION OUTPUT ;
    USE SIGNAL ;
    PORT
      LAYER M5 ;
        RECT  71.472 0 71.496 0.192 ;
    END
  END o2[128]
  PIN o2[129]
    DIRECTION OUTPUT ;
    USE SIGNAL ;
    PORT
      LAYER M5 ;
        RECT  71.712 0 71.736 0.192 ;
    END
  END o2[129]
  PIN o2[12]
    DIRECTION OUTPUT ;
    USE SIGNAL ;
    PORT
      LAYER M5 ;
        RECT  42.096 0 42.12 0.192 ;
    END
  END o2[12]
  PIN o2[130]
    DIRECTION OUTPUT ;
    USE SIGNAL ;
    PORT
      LAYER M5 ;
        RECT  71.952 0 71.976 0.192 ;
    END
  END o2[130]
  PIN o2[131]
    DIRECTION OUTPUT ;
    USE SIGNAL ;
    PORT
      LAYER M5 ;
        RECT  72.24 0 72.264 0.192 ;
    END
  END o2[131]
  PIN o2[132]
    DIRECTION OUTPUT ;
    USE SIGNAL ;
    PORT
      LAYER M5 ;
        RECT  72.48 0 72.504 0.192 ;
    END
  END o2[132]
  PIN o2[133]
    DIRECTION OUTPUT ;
    USE SIGNAL ;
    PORT
      LAYER M5 ;
        RECT  72.72 0 72.744 0.192 ;
    END
  END o2[133]
  PIN o2[134]
    DIRECTION OUTPUT ;
    USE SIGNAL ;
    PORT
      LAYER M5 ;
        RECT  72.96 0 72.984 0.192 ;
    END
  END o2[134]
  PIN o2[135]
    DIRECTION OUTPUT ;
    USE SIGNAL ;
    PORT
      LAYER M5 ;
        RECT  73.248 0 73.272 0.192 ;
    END
  END o2[135]
  PIN o2[13]
    DIRECTION OUTPUT ;
    USE SIGNAL ;
    PORT
      LAYER M5 ;
        RECT  42.336 0 42.36 0.192 ;
    END
  END o2[13]
  PIN o2[14]
    DIRECTION OUTPUT ;
    USE SIGNAL ;
    PORT
      LAYER M5 ;
        RECT  42.576 0 42.6 0.192 ;
    END
  END o2[14]
  PIN o2[15]
    DIRECTION OUTPUT ;
    USE SIGNAL ;
    PORT
      LAYER M5 ;
        RECT  42.816 0 42.84 0.192 ;
    END
  END o2[15]
  PIN o2[16]
    DIRECTION OUTPUT ;
    USE SIGNAL ;
    PORT
      LAYER M5 ;
        RECT  43.104 0 43.128 0.192 ;
    END
  END o2[16]
  PIN o2[17]
    DIRECTION OUTPUT ;
    USE SIGNAL ;
    PORT
      LAYER M5 ;
        RECT  43.344 0 43.368 0.192 ;
    END
  END o2[17]
  PIN o2[18]
    DIRECTION OUTPUT ;
    USE SIGNAL ;
    PORT
      LAYER M5 ;
        RECT  43.584 0 43.608 0.192 ;
    END
  END o2[18]
  PIN o2[19]
    DIRECTION OUTPUT ;
    USE SIGNAL ;
    PORT
      LAYER M5 ;
        RECT  43.824 0 43.848 0.192 ;
    END
  END o2[19]
  PIN o2[1]
    DIRECTION OUTPUT ;
    USE SIGNAL ;
    PORT
      LAYER M5 ;
        RECT  39.312 0 39.336 0.192 ;
    END
  END o2[1]
  PIN o2[20]
    DIRECTION OUTPUT ;
    USE SIGNAL ;
    PORT
      LAYER M5 ;
        RECT  44.112 0 44.136 0.192 ;
    END
  END o2[20]
  PIN o2[21]
    DIRECTION OUTPUT ;
    USE SIGNAL ;
    PORT
      LAYER M5 ;
        RECT  44.352 0 44.376 0.192 ;
    END
  END o2[21]
  PIN o2[22]
    DIRECTION OUTPUT ;
    USE SIGNAL ;
    PORT
      LAYER M5 ;
        RECT  44.592 0 44.616 0.192 ;
    END
  END o2[22]
  PIN o2[23]
    DIRECTION OUTPUT ;
    USE SIGNAL ;
    PORT
      LAYER M5 ;
        RECT  44.832 0 44.856 0.192 ;
    END
  END o2[23]
  PIN o2[24]
    DIRECTION OUTPUT ;
    USE SIGNAL ;
    PORT
      LAYER M5 ;
        RECT  45.12 0 45.144 0.192 ;
    END
  END o2[24]
  PIN o2[25]
    DIRECTION OUTPUT ;
    USE SIGNAL ;
    PORT
      LAYER M5 ;
        RECT  45.36 0 45.384 0.192 ;
    END
  END o2[25]
  PIN o2[26]
    DIRECTION OUTPUT ;
    USE SIGNAL ;
    PORT
      LAYER M5 ;
        RECT  45.6 0 45.624 0.192 ;
    END
  END o2[26]
  PIN o2[27]
    DIRECTION OUTPUT ;
    USE SIGNAL ;
    PORT
      LAYER M5 ;
        RECT  45.84 0 45.864 0.192 ;
    END
  END o2[27]
  PIN o2[28]
    DIRECTION OUTPUT ;
    USE SIGNAL ;
    PORT
      LAYER M5 ;
        RECT  46.08 0 46.104 0.192 ;
    END
  END o2[28]
  PIN o2[29]
    DIRECTION OUTPUT ;
    USE SIGNAL ;
    PORT
      LAYER M5 ;
        RECT  46.368 0 46.392 0.192 ;
    END
  END o2[29]
  PIN o2[2]
    DIRECTION OUTPUT ;
    USE SIGNAL ;
    PORT
      LAYER M5 ;
        RECT  39.552 0 39.576 0.192 ;
    END
  END o2[2]
  PIN o2[30]
    DIRECTION OUTPUT ;
    USE SIGNAL ;
    PORT
      LAYER M5 ;
        RECT  46.608 0 46.632 0.192 ;
    END
  END o2[30]
  PIN o2[31]
    DIRECTION OUTPUT ;
    USE SIGNAL ;
    PORT
      LAYER M5 ;
        RECT  46.848 0 46.872 0.192 ;
    END
  END o2[31]
  PIN o2[32]
    DIRECTION OUTPUT ;
    USE SIGNAL ;
    PORT
      LAYER M5 ;
        RECT  47.088 0 47.112 0.192 ;
    END
  END o2[32]
  PIN o2[33]
    DIRECTION OUTPUT ;
    USE SIGNAL ;
    PORT
      LAYER M5 ;
        RECT  47.376 0 47.4 0.192 ;
    END
  END o2[33]
  PIN o2[34]
    DIRECTION OUTPUT ;
    USE SIGNAL ;
    PORT
      LAYER M5 ;
        RECT  47.616 0 47.64 0.192 ;
    END
  END o2[34]
  PIN o2[35]
    DIRECTION OUTPUT ;
    USE SIGNAL ;
    PORT
      LAYER M5 ;
        RECT  47.856 0 47.88 0.192 ;
    END
  END o2[35]
  PIN o2[36]
    DIRECTION OUTPUT ;
    USE SIGNAL ;
    PORT
      LAYER M5 ;
        RECT  48.096 0 48.12 0.192 ;
    END
  END o2[36]
  PIN o2[37]
    DIRECTION OUTPUT ;
    USE SIGNAL ;
    PORT
      LAYER M5 ;
        RECT  48.384 0 48.408 0.192 ;
    END
  END o2[37]
  PIN o2[38]
    DIRECTION OUTPUT ;
    USE SIGNAL ;
    PORT
      LAYER M5 ;
        RECT  48.624 0 48.648 0.192 ;
    END
  END o2[38]
  PIN o2[39]
    DIRECTION OUTPUT ;
    USE SIGNAL ;
    PORT
      LAYER M5 ;
        RECT  48.864 0 48.888 0.192 ;
    END
  END o2[39]
  PIN o2[3]
    DIRECTION OUTPUT ;
    USE SIGNAL ;
    PORT
      LAYER M5 ;
        RECT  39.84 0 39.864 0.192 ;
    END
  END o2[3]
  PIN o2[40]
    DIRECTION OUTPUT ;
    USE SIGNAL ;
    PORT
      LAYER M5 ;
        RECT  49.104 0 49.128 0.192 ;
    END
  END o2[40]
  PIN o2[41]
    DIRECTION OUTPUT ;
    USE SIGNAL ;
    PORT
      LAYER M5 ;
        RECT  49.344 0 49.368 0.192 ;
    END
  END o2[41]
  PIN o2[42]
    DIRECTION OUTPUT ;
    USE SIGNAL ;
    PORT
      LAYER M5 ;
        RECT  49.632 0 49.656 0.192 ;
    END
  END o2[42]
  PIN o2[43]
    DIRECTION OUTPUT ;
    USE SIGNAL ;
    PORT
      LAYER M5 ;
        RECT  49.872 0 49.896 0.192 ;
    END
  END o2[43]
  PIN o2[44]
    DIRECTION OUTPUT ;
    USE SIGNAL ;
    PORT
      LAYER M5 ;
        RECT  50.112 0 50.136 0.192 ;
    END
  END o2[44]
  PIN o2[45]
    DIRECTION OUTPUT ;
    USE SIGNAL ;
    PORT
      LAYER M5 ;
        RECT  50.352 0 50.376 0.192 ;
    END
  END o2[45]
  PIN o2[46]
    DIRECTION OUTPUT ;
    USE SIGNAL ;
    PORT
      LAYER M5 ;
        RECT  50.64 0 50.664 0.192 ;
    END
  END o2[46]
  PIN o2[47]
    DIRECTION OUTPUT ;
    USE SIGNAL ;
    PORT
      LAYER M5 ;
        RECT  50.88 0 50.904 0.192 ;
    END
  END o2[47]
  PIN o2[48]
    DIRECTION OUTPUT ;
    USE SIGNAL ;
    PORT
      LAYER M5 ;
        RECT  51.12 0 51.144 0.192 ;
    END
  END o2[48]
  PIN o2[49]
    DIRECTION OUTPUT ;
    USE SIGNAL ;
    PORT
      LAYER M5 ;
        RECT  51.36 0 51.384 0.192 ;
    END
  END o2[49]
  PIN o2[4]
    DIRECTION OUTPUT ;
    USE SIGNAL ;
    PORT
      LAYER M5 ;
        RECT  40.08 0 40.104 0.192 ;
    END
  END o2[4]
  PIN o2[50]
    DIRECTION OUTPUT ;
    USE SIGNAL ;
    PORT
      LAYER M5 ;
        RECT  51.648 0 51.672 0.192 ;
    END
  END o2[50]
  PIN o2[51]
    DIRECTION OUTPUT ;
    USE SIGNAL ;
    PORT
      LAYER M5 ;
        RECT  51.888 0 51.912 0.192 ;
    END
  END o2[51]
  PIN o2[52]
    DIRECTION OUTPUT ;
    USE SIGNAL ;
    PORT
      LAYER M5 ;
        RECT  52.128 0 52.152 0.192 ;
    END
  END o2[52]
  PIN o2[53]
    DIRECTION OUTPUT ;
    USE SIGNAL ;
    PORT
      LAYER M5 ;
        RECT  52.368 0 52.392 0.192 ;
    END
  END o2[53]
  PIN o2[54]
    DIRECTION OUTPUT ;
    USE SIGNAL ;
    PORT
      LAYER M5 ;
        RECT  52.608 0 52.632 0.192 ;
    END
  END o2[54]
  PIN o2[55]
    DIRECTION OUTPUT ;
    USE SIGNAL ;
    PORT
      LAYER M5 ;
        RECT  52.896 0 52.92 0.192 ;
    END
  END o2[55]
  PIN o2[56]
    DIRECTION OUTPUT ;
    USE SIGNAL ;
    PORT
      LAYER M5 ;
        RECT  53.136 0 53.16 0.192 ;
    END
  END o2[56]
  PIN o2[57]
    DIRECTION OUTPUT ;
    USE SIGNAL ;
    PORT
      LAYER M5 ;
        RECT  53.376 0 53.4 0.192 ;
    END
  END o2[57]
  PIN o2[58]
    DIRECTION OUTPUT ;
    USE SIGNAL ;
    PORT
      LAYER M5 ;
        RECT  53.616 0 53.64 0.192 ;
    END
  END o2[58]
  PIN o2[59]
    DIRECTION OUTPUT ;
    USE SIGNAL ;
    PORT
      LAYER M5 ;
        RECT  53.904 0 53.928 0.192 ;
    END
  END o2[59]
  PIN o2[5]
    DIRECTION OUTPUT ;
    USE SIGNAL ;
    PORT
      LAYER M5 ;
        RECT  40.32 0 40.344 0.192 ;
    END
  END o2[5]
  PIN o2[60]
    DIRECTION OUTPUT ;
    USE SIGNAL ;
    PORT
      LAYER M5 ;
        RECT  54.144 0 54.168 0.192 ;
    END
  END o2[60]
  PIN o2[61]
    DIRECTION OUTPUT ;
    USE SIGNAL ;
    PORT
      LAYER M5 ;
        RECT  54.384 0 54.408 0.192 ;
    END
  END o2[61]
  PIN o2[62]
    DIRECTION OUTPUT ;
    USE SIGNAL ;
    PORT
      LAYER M5 ;
        RECT  54.624 0 54.648 0.192 ;
    END
  END o2[62]
  PIN o2[63]
    DIRECTION OUTPUT ;
    USE SIGNAL ;
    PORT
      LAYER M5 ;
        RECT  54.912 0 54.936 0.192 ;
    END
  END o2[63]
  PIN o2[64]
    DIRECTION OUTPUT ;
    USE SIGNAL ;
    PORT
      LAYER M5 ;
        RECT  55.152 0 55.176 0.192 ;
    END
  END o2[64]
  PIN o2[65]
    DIRECTION OUTPUT ;
    USE SIGNAL ;
    PORT
      LAYER M5 ;
        RECT  55.392 0 55.416 0.192 ;
    END
  END o2[65]
  PIN o2[66]
    DIRECTION OUTPUT ;
    USE SIGNAL ;
    PORT
      LAYER M5 ;
        RECT  55.632 0 55.656 0.192 ;
    END
  END o2[66]
  PIN o2[67]
    DIRECTION OUTPUT ;
    USE SIGNAL ;
    PORT
      LAYER M5 ;
        RECT  55.92 0 55.944 0.192 ;
    END
  END o2[67]
  PIN o2[68]
    DIRECTION OUTPUT ;
    USE SIGNAL ;
    PORT
      LAYER M5 ;
        RECT  56.4 0 56.424 0.192 ;
    END
  END o2[68]
  PIN o2[69]
    DIRECTION OUTPUT ;
    USE SIGNAL ;
    PORT
      LAYER M5 ;
        RECT  56.64 0 56.664 0.192 ;
    END
  END o2[69]
  PIN o2[6]
    DIRECTION OUTPUT ;
    USE SIGNAL ;
    PORT
      LAYER M5 ;
        RECT  40.56 0 40.584 0.192 ;
    END
  END o2[6]
  PIN o2[70]
    DIRECTION OUTPUT ;
    USE SIGNAL ;
    PORT
      LAYER M5 ;
        RECT  56.88 0 56.904 0.192 ;
    END
  END o2[70]
  PIN o2[71]
    DIRECTION OUTPUT ;
    USE SIGNAL ;
    PORT
      LAYER M5 ;
        RECT  57.168 0 57.192 0.192 ;
    END
  END o2[71]
  PIN o2[72]
    DIRECTION OUTPUT ;
    USE SIGNAL ;
    PORT
      LAYER M5 ;
        RECT  57.408 0 57.432 0.192 ;
    END
  END o2[72]
  PIN o2[73]
    DIRECTION OUTPUT ;
    USE SIGNAL ;
    PORT
      LAYER M5 ;
        RECT  57.648 0 57.672 0.192 ;
    END
  END o2[73]
  PIN o2[74]
    DIRECTION OUTPUT ;
    USE SIGNAL ;
    PORT
      LAYER M5 ;
        RECT  57.888 0 57.912 0.192 ;
    END
  END o2[74]
  PIN o2[75]
    DIRECTION OUTPUT ;
    USE SIGNAL ;
    PORT
      LAYER M5 ;
        RECT  58.176 0 58.2 0.192 ;
    END
  END o2[75]
  PIN o2[76]
    DIRECTION OUTPUT ;
    USE SIGNAL ;
    PORT
      LAYER M5 ;
        RECT  58.416 0 58.44 0.192 ;
    END
  END o2[76]
  PIN o2[77]
    DIRECTION OUTPUT ;
    USE SIGNAL ;
    PORT
      LAYER M5 ;
        RECT  58.656 0 58.68 0.192 ;
    END
  END o2[77]
  PIN o2[78]
    DIRECTION OUTPUT ;
    USE SIGNAL ;
    PORT
      LAYER M5 ;
        RECT  58.896 0 58.92 0.192 ;
    END
  END o2[78]
  PIN o2[79]
    DIRECTION OUTPUT ;
    USE SIGNAL ;
    PORT
      LAYER M5 ;
        RECT  59.184 0 59.208 0.192 ;
    END
  END o2[79]
  PIN o2[7]
    DIRECTION OUTPUT ;
    USE SIGNAL ;
    PORT
      LAYER M5 ;
        RECT  40.848 0 40.872 0.192 ;
    END
  END o2[7]
  PIN o2[80]
    DIRECTION OUTPUT ;
    USE SIGNAL ;
    PORT
      LAYER M5 ;
        RECT  59.424 0 59.448 0.192 ;
    END
  END o2[80]
  PIN o2[81]
    DIRECTION OUTPUT ;
    USE SIGNAL ;
    PORT
      LAYER M5 ;
        RECT  59.664 0 59.688 0.192 ;
    END
  END o2[81]
  PIN o2[82]
    DIRECTION OUTPUT ;
    USE SIGNAL ;
    PORT
      LAYER M5 ;
        RECT  59.904 0 59.928 0.192 ;
    END
  END o2[82]
  PIN o2[83]
    DIRECTION OUTPUT ;
    USE SIGNAL ;
    PORT
      LAYER M5 ;
        RECT  60.144 0 60.168 0.192 ;
    END
  END o2[83]
  PIN o2[84]
    DIRECTION OUTPUT ;
    USE SIGNAL ;
    PORT
      LAYER M5 ;
        RECT  60.432 0 60.456 0.192 ;
    END
  END o2[84]
  PIN o2[85]
    DIRECTION OUTPUT ;
    USE SIGNAL ;
    PORT
      LAYER M5 ;
        RECT  60.672 0 60.696 0.192 ;
    END
  END o2[85]
  PIN o2[86]
    DIRECTION OUTPUT ;
    USE SIGNAL ;
    PORT
      LAYER M5 ;
        RECT  60.912 0 60.936 0.192 ;
    END
  END o2[86]
  PIN o2[87]
    DIRECTION OUTPUT ;
    USE SIGNAL ;
    PORT
      LAYER M5 ;
        RECT  61.152 0 61.176 0.192 ;
    END
  END o2[87]
  PIN o2[88]
    DIRECTION OUTPUT ;
    USE SIGNAL ;
    PORT
      LAYER M5 ;
        RECT  61.44 0 61.464 0.192 ;
    END
  END o2[88]
  PIN o2[89]
    DIRECTION OUTPUT ;
    USE SIGNAL ;
    PORT
      LAYER M5 ;
        RECT  61.68 0 61.704 0.192 ;
    END
  END o2[89]
  PIN o2[8]
    DIRECTION OUTPUT ;
    USE SIGNAL ;
    PORT
      LAYER M5 ;
        RECT  41.088 0 41.112 0.192 ;
    END
  END o2[8]
  PIN o2[90]
    DIRECTION OUTPUT ;
    USE SIGNAL ;
    PORT
      LAYER M5 ;
        RECT  61.92 0 61.944 0.192 ;
    END
  END o2[90]
  PIN o2[91]
    DIRECTION OUTPUT ;
    USE SIGNAL ;
    PORT
      LAYER M5 ;
        RECT  62.16 0 62.184 0.192 ;
    END
  END o2[91]
  PIN o2[92]
    DIRECTION OUTPUT ;
    USE SIGNAL ;
    PORT
      LAYER M5 ;
        RECT  62.448 0 62.472 0.192 ;
    END
  END o2[92]
  PIN o2[93]
    DIRECTION OUTPUT ;
    USE SIGNAL ;
    PORT
      LAYER M5 ;
        RECT  62.688 0 62.712 0.192 ;
    END
  END o2[93]
  PIN o2[94]
    DIRECTION OUTPUT ;
    USE SIGNAL ;
    PORT
      LAYER M5 ;
        RECT  62.928 0 62.952 0.192 ;
    END
  END o2[94]
  PIN o2[95]
    DIRECTION OUTPUT ;
    USE SIGNAL ;
    PORT
      LAYER M5 ;
        RECT  63.168 0 63.192 0.192 ;
    END
  END o2[95]
  PIN o2[96]
    DIRECTION OUTPUT ;
    USE SIGNAL ;
    PORT
      LAYER M5 ;
        RECT  63.456 0 63.48 0.192 ;
    END
  END o2[96]
  PIN o2[97]
    DIRECTION OUTPUT ;
    USE SIGNAL ;
    PORT
      LAYER M5 ;
        RECT  63.696 0 63.72 0.192 ;
    END
  END o2[97]
  PIN o2[98]
    DIRECTION OUTPUT ;
    USE SIGNAL ;
    PORT
      LAYER M5 ;
        RECT  63.936 0 63.96 0.192 ;
    END
  END o2[98]
  PIN o2[99]
    DIRECTION OUTPUT ;
    USE SIGNAL ;
    PORT
      LAYER M5 ;
        RECT  64.176 0 64.2 0.192 ;
    END
  END o2[99]
  PIN o2[9]
    DIRECTION OUTPUT ;
    USE SIGNAL ;
    PORT
      LAYER M5 ;
        RECT  41.328 0 41.352 0.192 ;
    END
  END o2[9]
  PIN o3[0]
    DIRECTION OUTPUT ;
    USE SIGNAL ;
    PORT
      LAYER M5 ;
        RECT  50.592 21.408 50.616 21.6 ;
    END
  END o3[0]
  PIN o3[100]
    DIRECTION OUTPUT ;
    USE SIGNAL ;
    PORT
      LAYER M5 ;
        RECT  67.392 21.408 67.416 21.6 ;
    END
  END o3[100]
  PIN o3[101]
    DIRECTION OUTPUT ;
    USE SIGNAL ;
    PORT
      LAYER M5 ;
        RECT  67.584 21.408 67.608 21.6 ;
    END
  END o3[101]
  PIN o3[102]
    DIRECTION OUTPUT ;
    USE SIGNAL ;
    PORT
      LAYER M5 ;
        RECT  67.728 21.408 67.752 21.6 ;
    END
  END o3[102]
  PIN o3[103]
    DIRECTION OUTPUT ;
    USE SIGNAL ;
    PORT
      LAYER M5 ;
        RECT  67.92 21.408 67.944 21.6 ;
    END
  END o3[103]
  PIN o3[104]
    DIRECTION OUTPUT ;
    USE SIGNAL ;
    PORT
      LAYER M5 ;
        RECT  68.064 21.408 68.088 21.6 ;
    END
  END o3[104]
  PIN o3[105]
    DIRECTION OUTPUT ;
    USE SIGNAL ;
    PORT
      LAYER M5 ;
        RECT  68.256 21.408 68.28 21.6 ;
    END
  END o3[105]
  PIN o3[106]
    DIRECTION OUTPUT ;
    USE SIGNAL ;
    PORT
      LAYER M5 ;
        RECT  68.4 21.408 68.424 21.6 ;
    END
  END o3[106]
  PIN o3[107]
    DIRECTION OUTPUT ;
    USE SIGNAL ;
    PORT
      LAYER M5 ;
        RECT  68.544 21.408 68.568 21.6 ;
    END
  END o3[107]
  PIN o3[108]
    DIRECTION OUTPUT ;
    USE SIGNAL ;
    PORT
      LAYER M5 ;
        RECT  68.736 21.408 68.76 21.6 ;
    END
  END o3[108]
  PIN o3[109]
    DIRECTION OUTPUT ;
    USE SIGNAL ;
    PORT
      LAYER M5 ;
        RECT  68.88 21.408 68.904 21.6 ;
    END
  END o3[109]
  PIN o3[10]
    DIRECTION OUTPUT ;
    USE SIGNAL ;
    PORT
      LAYER M5 ;
        RECT  52.272 21.408 52.296 21.6 ;
    END
  END o3[10]
  PIN o3[110]
    DIRECTION OUTPUT ;
    USE SIGNAL ;
    PORT
      LAYER M5 ;
        RECT  69.072 21.408 69.096 21.6 ;
    END
  END o3[110]
  PIN o3[111]
    DIRECTION OUTPUT ;
    USE SIGNAL ;
    PORT
      LAYER M5 ;
        RECT  69.216 21.408 69.24 21.6 ;
    END
  END o3[111]
  PIN o3[112]
    DIRECTION OUTPUT ;
    USE SIGNAL ;
    PORT
      LAYER M5 ;
        RECT  69.408 21.408 69.432 21.6 ;
    END
  END o3[112]
  PIN o3[113]
    DIRECTION OUTPUT ;
    USE SIGNAL ;
    PORT
      LAYER M5 ;
        RECT  69.552 21.408 69.576 21.6 ;
    END
  END o3[113]
  PIN o3[114]
    DIRECTION OUTPUT ;
    USE SIGNAL ;
    PORT
      LAYER M5 ;
        RECT  69.744 21.408 69.768 21.6 ;
    END
  END o3[114]
  PIN o3[115]
    DIRECTION OUTPUT ;
    USE SIGNAL ;
    PORT
      LAYER M5 ;
        RECT  69.888 21.408 69.912 21.6 ;
    END
  END o3[115]
  PIN o3[116]
    DIRECTION OUTPUT ;
    USE SIGNAL ;
    PORT
      LAYER M5 ;
        RECT  70.08 21.408 70.104 21.6 ;
    END
  END o3[116]
  PIN o3[117]
    DIRECTION OUTPUT ;
    USE SIGNAL ;
    PORT
      LAYER M5 ;
        RECT  70.224 21.408 70.248 21.6 ;
    END
  END o3[117]
  PIN o3[118]
    DIRECTION OUTPUT ;
    USE SIGNAL ;
    PORT
      LAYER M5 ;
        RECT  70.416 21.408 70.44 21.6 ;
    END
  END o3[118]
  PIN o3[119]
    DIRECTION OUTPUT ;
    USE SIGNAL ;
    PORT
      LAYER M5 ;
        RECT  70.56 21.408 70.584 21.6 ;
    END
  END o3[119]
  PIN o3[11]
    DIRECTION OUTPUT ;
    USE SIGNAL ;
    PORT
      LAYER M5 ;
        RECT  52.416 21.408 52.44 21.6 ;
    END
  END o3[11]
  PIN o3[120]
    DIRECTION OUTPUT ;
    USE SIGNAL ;
    PORT
      LAYER M5 ;
        RECT  70.752 21.408 70.776 21.6 ;
    END
  END o3[120]
  PIN o3[121]
    DIRECTION OUTPUT ;
    USE SIGNAL ;
    PORT
      LAYER M5 ;
        RECT  70.896 21.408 70.92 21.6 ;
    END
  END o3[121]
  PIN o3[122]
    DIRECTION OUTPUT ;
    USE SIGNAL ;
    PORT
      LAYER M5 ;
        RECT  71.04 21.408 71.064 21.6 ;
    END
  END o3[122]
  PIN o3[123]
    DIRECTION OUTPUT ;
    USE SIGNAL ;
    PORT
      LAYER M5 ;
        RECT  71.232 21.408 71.256 21.6 ;
    END
  END o3[123]
  PIN o3[124]
    DIRECTION OUTPUT ;
    USE SIGNAL ;
    PORT
      LAYER M5 ;
        RECT  71.376 21.408 71.4 21.6 ;
    END
  END o3[124]
  PIN o3[125]
    DIRECTION OUTPUT ;
    USE SIGNAL ;
    PORT
      LAYER M5 ;
        RECT  71.568 21.408 71.592 21.6 ;
    END
  END o3[125]
  PIN o3[126]
    DIRECTION OUTPUT ;
    USE SIGNAL ;
    PORT
      LAYER M5 ;
        RECT  71.712 21.408 71.736 21.6 ;
    END
  END o3[126]
  PIN o3[127]
    DIRECTION OUTPUT ;
    USE SIGNAL ;
    PORT
      LAYER M5 ;
        RECT  71.904 21.408 71.928 21.6 ;
    END
  END o3[127]
  PIN o3[128]
    DIRECTION OUTPUT ;
    USE SIGNAL ;
    PORT
      LAYER M5 ;
        RECT  72.048 21.408 72.072 21.6 ;
    END
  END o3[128]
  PIN o3[129]
    DIRECTION OUTPUT ;
    USE SIGNAL ;
    PORT
      LAYER M5 ;
        RECT  72.24 21.408 72.264 21.6 ;
    END
  END o3[129]
  PIN o3[12]
    DIRECTION OUTPUT ;
    USE SIGNAL ;
    PORT
      LAYER M5 ;
        RECT  52.608 21.408 52.632 21.6 ;
    END
  END o3[12]
  PIN o3[130]
    DIRECTION OUTPUT ;
    USE SIGNAL ;
    PORT
      LAYER M5 ;
        RECT  72.384 21.408 72.408 21.6 ;
    END
  END o3[130]
  PIN o3[131]
    DIRECTION OUTPUT ;
    USE SIGNAL ;
    PORT
      LAYER M5 ;
        RECT  72.576 21.408 72.6 21.6 ;
    END
  END o3[131]
  PIN o3[132]
    DIRECTION OUTPUT ;
    USE SIGNAL ;
    PORT
      LAYER M5 ;
        RECT  72.72 21.408 72.744 21.6 ;
    END
  END o3[132]
  PIN o3[133]
    DIRECTION OUTPUT ;
    USE SIGNAL ;
    PORT
      LAYER M5 ;
        RECT  72.912 21.408 72.936 21.6 ;
    END
  END o3[133]
  PIN o3[134]
    DIRECTION OUTPUT ;
    USE SIGNAL ;
    PORT
      LAYER M5 ;
        RECT  73.056 21.408 73.08 21.6 ;
    END
  END o3[134]
  PIN o3[135]
    DIRECTION OUTPUT ;
    USE SIGNAL ;
    PORT
      LAYER M5 ;
        RECT  73.248 21.408 73.272 21.6 ;
    END
  END o3[135]
  PIN o3[13]
    DIRECTION OUTPUT ;
    USE SIGNAL ;
    PORT
      LAYER M5 ;
        RECT  52.752 21.408 52.776 21.6 ;
    END
  END o3[13]
  PIN o3[14]
    DIRECTION OUTPUT ;
    USE SIGNAL ;
    PORT
      LAYER M5 ;
        RECT  52.896 21.408 52.92 21.6 ;
    END
  END o3[14]
  PIN o3[15]
    DIRECTION OUTPUT ;
    USE SIGNAL ;
    PORT
      LAYER M5 ;
        RECT  53.088 21.408 53.112 21.6 ;
    END
  END o3[15]
  PIN o3[16]
    DIRECTION OUTPUT ;
    USE SIGNAL ;
    PORT
      LAYER M5 ;
        RECT  53.232 21.408 53.256 21.6 ;
    END
  END o3[16]
  PIN o3[17]
    DIRECTION OUTPUT ;
    USE SIGNAL ;
    PORT
      LAYER M5 ;
        RECT  53.424 21.408 53.448 21.6 ;
    END
  END o3[17]
  PIN o3[18]
    DIRECTION OUTPUT ;
    USE SIGNAL ;
    PORT
      LAYER M5 ;
        RECT  53.568 21.408 53.592 21.6 ;
    END
  END o3[18]
  PIN o3[19]
    DIRECTION OUTPUT ;
    USE SIGNAL ;
    PORT
      LAYER M5 ;
        RECT  53.76 21.408 53.784 21.6 ;
    END
  END o3[19]
  PIN o3[1]
    DIRECTION OUTPUT ;
    USE SIGNAL ;
    PORT
      LAYER M5 ;
        RECT  50.736 21.408 50.76 21.6 ;
    END
  END o3[1]
  PIN o3[20]
    DIRECTION OUTPUT ;
    USE SIGNAL ;
    PORT
      LAYER M5 ;
        RECT  53.904 21.408 53.928 21.6 ;
    END
  END o3[20]
  PIN o3[21]
    DIRECTION OUTPUT ;
    USE SIGNAL ;
    PORT
      LAYER M5 ;
        RECT  54.096 21.408 54.12 21.6 ;
    END
  END o3[21]
  PIN o3[22]
    DIRECTION OUTPUT ;
    USE SIGNAL ;
    PORT
      LAYER M5 ;
        RECT  54.24 21.408 54.264 21.6 ;
    END
  END o3[22]
  PIN o3[23]
    DIRECTION OUTPUT ;
    USE SIGNAL ;
    PORT
      LAYER M5 ;
        RECT  54.432 21.408 54.456 21.6 ;
    END
  END o3[23]
  PIN o3[24]
    DIRECTION OUTPUT ;
    USE SIGNAL ;
    PORT
      LAYER M5 ;
        RECT  54.576 21.408 54.6 21.6 ;
    END
  END o3[24]
  PIN o3[25]
    DIRECTION OUTPUT ;
    USE SIGNAL ;
    PORT
      LAYER M5 ;
        RECT  54.768 21.408 54.792 21.6 ;
    END
  END o3[25]
  PIN o3[26]
    DIRECTION OUTPUT ;
    USE SIGNAL ;
    PORT
      LAYER M5 ;
        RECT  54.912 21.408 54.936 21.6 ;
    END
  END o3[26]
  PIN o3[27]
    DIRECTION OUTPUT ;
    USE SIGNAL ;
    PORT
      LAYER M5 ;
        RECT  55.104 21.408 55.128 21.6 ;
    END
  END o3[27]
  PIN o3[28]
    DIRECTION OUTPUT ;
    USE SIGNAL ;
    PORT
      LAYER M5 ;
        RECT  55.248 21.408 55.272 21.6 ;
    END
  END o3[28]
  PIN o3[29]
    DIRECTION OUTPUT ;
    USE SIGNAL ;
    PORT
      LAYER M5 ;
        RECT  55.392 21.408 55.416 21.6 ;
    END
  END o3[29]
  PIN o3[2]
    DIRECTION OUTPUT ;
    USE SIGNAL ;
    PORT
      LAYER M5 ;
        RECT  50.928 21.408 50.952 21.6 ;
    END
  END o3[2]
  PIN o3[30]
    DIRECTION OUTPUT ;
    USE SIGNAL ;
    PORT
      LAYER M5 ;
        RECT  55.584 21.408 55.608 21.6 ;
    END
  END o3[30]
  PIN o3[31]
    DIRECTION OUTPUT ;
    USE SIGNAL ;
    PORT
      LAYER M5 ;
        RECT  55.728 21.408 55.752 21.6 ;
    END
  END o3[31]
  PIN o3[32]
    DIRECTION OUTPUT ;
    USE SIGNAL ;
    PORT
      LAYER M5 ;
        RECT  55.92 21.408 55.944 21.6 ;
    END
  END o3[32]
  PIN o3[33]
    DIRECTION OUTPUT ;
    USE SIGNAL ;
    PORT
      LAYER M5 ;
        RECT  56.064 21.408 56.088 21.6 ;
    END
  END o3[33]
  PIN o3[34]
    DIRECTION OUTPUT ;
    USE SIGNAL ;
    PORT
      LAYER M5 ;
        RECT  56.256 21.408 56.28 21.6 ;
    END
  END o3[34]
  PIN o3[35]
    DIRECTION OUTPUT ;
    USE SIGNAL ;
    PORT
      LAYER M5 ;
        RECT  56.4 21.408 56.424 21.6 ;
    END
  END o3[35]
  PIN o3[36]
    DIRECTION OUTPUT ;
    USE SIGNAL ;
    PORT
      LAYER M5 ;
        RECT  56.592 21.408 56.616 21.6 ;
    END
  END o3[36]
  PIN o3[37]
    DIRECTION OUTPUT ;
    USE SIGNAL ;
    PORT
      LAYER M5 ;
        RECT  56.736 21.408 56.76 21.6 ;
    END
  END o3[37]
  PIN o3[38]
    DIRECTION OUTPUT ;
    USE SIGNAL ;
    PORT
      LAYER M5 ;
        RECT  56.928 21.408 56.952 21.6 ;
    END
  END o3[38]
  PIN o3[39]
    DIRECTION OUTPUT ;
    USE SIGNAL ;
    PORT
      LAYER M5 ;
        RECT  57.072 21.408 57.096 21.6 ;
    END
  END o3[39]
  PIN o3[3]
    DIRECTION OUTPUT ;
    USE SIGNAL ;
    PORT
      LAYER M5 ;
        RECT  51.072 21.408 51.096 21.6 ;
    END
  END o3[3]
  PIN o3[40]
    DIRECTION OUTPUT ;
    USE SIGNAL ;
    PORT
      LAYER M5 ;
        RECT  57.264 21.408 57.288 21.6 ;
    END
  END o3[40]
  PIN o3[41]
    DIRECTION OUTPUT ;
    USE SIGNAL ;
    PORT
      LAYER M5 ;
        RECT  57.408 21.408 57.432 21.6 ;
    END
  END o3[41]
  PIN o3[42]
    DIRECTION OUTPUT ;
    USE SIGNAL ;
    PORT
      LAYER M5 ;
        RECT  57.6 21.408 57.624 21.6 ;
    END
  END o3[42]
  PIN o3[43]
    DIRECTION OUTPUT ;
    USE SIGNAL ;
    PORT
      LAYER M5 ;
        RECT  57.744 21.408 57.768 21.6 ;
    END
  END o3[43]
  PIN o3[44]
    DIRECTION OUTPUT ;
    USE SIGNAL ;
    PORT
      LAYER M5 ;
        RECT  57.936 21.408 57.96 21.6 ;
    END
  END o3[44]
  PIN o3[45]
    DIRECTION OUTPUT ;
    USE SIGNAL ;
    PORT
      LAYER M5 ;
        RECT  58.08 21.408 58.104 21.6 ;
    END
  END o3[45]
  PIN o3[46]
    DIRECTION OUTPUT ;
    USE SIGNAL ;
    PORT
      LAYER M5 ;
        RECT  58.224 21.408 58.248 21.6 ;
    END
  END o3[46]
  PIN o3[47]
    DIRECTION OUTPUT ;
    USE SIGNAL ;
    PORT
      LAYER M5 ;
        RECT  58.416 21.408 58.44 21.6 ;
    END
  END o3[47]
  PIN o3[48]
    DIRECTION OUTPUT ;
    USE SIGNAL ;
    PORT
      LAYER M5 ;
        RECT  58.56 21.408 58.584 21.6 ;
    END
  END o3[48]
  PIN o3[49]
    DIRECTION OUTPUT ;
    USE SIGNAL ;
    PORT
      LAYER M5 ;
        RECT  58.752 21.408 58.776 21.6 ;
    END
  END o3[49]
  PIN o3[4]
    DIRECTION OUTPUT ;
    USE SIGNAL ;
    PORT
      LAYER M5 ;
        RECT  51.264 21.408 51.288 21.6 ;
    END
  END o3[4]
  PIN o3[50]
    DIRECTION OUTPUT ;
    USE SIGNAL ;
    PORT
      LAYER M5 ;
        RECT  58.896 21.408 58.92 21.6 ;
    END
  END o3[50]
  PIN o3[51]
    DIRECTION OUTPUT ;
    USE SIGNAL ;
    PORT
      LAYER M5 ;
        RECT  59.088 21.408 59.112 21.6 ;
    END
  END o3[51]
  PIN o3[52]
    DIRECTION OUTPUT ;
    USE SIGNAL ;
    PORT
      LAYER M5 ;
        RECT  59.232 21.408 59.256 21.6 ;
    END
  END o3[52]
  PIN o3[53]
    DIRECTION OUTPUT ;
    USE SIGNAL ;
    PORT
      LAYER M5 ;
        RECT  59.424 21.408 59.448 21.6 ;
    END
  END o3[53]
  PIN o3[54]
    DIRECTION OUTPUT ;
    USE SIGNAL ;
    PORT
      LAYER M5 ;
        RECT  59.568 21.408 59.592 21.6 ;
    END
  END o3[54]
  PIN o3[55]
    DIRECTION OUTPUT ;
    USE SIGNAL ;
    PORT
      LAYER M5 ;
        RECT  59.76 21.408 59.784 21.6 ;
    END
  END o3[55]
  PIN o3[56]
    DIRECTION OUTPUT ;
    USE SIGNAL ;
    PORT
      LAYER M5 ;
        RECT  59.904 21.408 59.928 21.6 ;
    END
  END o3[56]
  PIN o3[57]
    DIRECTION OUTPUT ;
    USE SIGNAL ;
    PORT
      LAYER M5 ;
        RECT  60.096 21.408 60.12 21.6 ;
    END
  END o3[57]
  PIN o3[58]
    DIRECTION OUTPUT ;
    USE SIGNAL ;
    PORT
      LAYER M5 ;
        RECT  60.24 21.408 60.264 21.6 ;
    END
  END o3[58]
  PIN o3[59]
    DIRECTION OUTPUT ;
    USE SIGNAL ;
    PORT
      LAYER M5 ;
        RECT  60.432 21.408 60.456 21.6 ;
    END
  END o3[59]
  PIN o3[5]
    DIRECTION OUTPUT ;
    USE SIGNAL ;
    PORT
      LAYER M5 ;
        RECT  51.408 21.408 51.432 21.6 ;
    END
  END o3[5]
  PIN o3[60]
    DIRECTION OUTPUT ;
    USE SIGNAL ;
    PORT
      LAYER M5 ;
        RECT  60.576 21.408 60.6 21.6 ;
    END
  END o3[60]
  PIN o3[61]
    DIRECTION OUTPUT ;
    USE SIGNAL ;
    PORT
      LAYER M5 ;
        RECT  60.72 21.408 60.744 21.6 ;
    END
  END o3[61]
  PIN o3[62]
    DIRECTION OUTPUT ;
    USE SIGNAL ;
    PORT
      LAYER M5 ;
        RECT  60.912 21.408 60.936 21.6 ;
    END
  END o3[62]
  PIN o3[63]
    DIRECTION OUTPUT ;
    USE SIGNAL ;
    PORT
      LAYER M5 ;
        RECT  61.056 21.408 61.08 21.6 ;
    END
  END o3[63]
  PIN o3[64]
    DIRECTION OUTPUT ;
    USE SIGNAL ;
    PORT
      LAYER M5 ;
        RECT  61.248 21.408 61.272 21.6 ;
    END
  END o3[64]
  PIN o3[65]
    DIRECTION OUTPUT ;
    USE SIGNAL ;
    PORT
      LAYER M5 ;
        RECT  61.392 21.408 61.416 21.6 ;
    END
  END o3[65]
  PIN o3[66]
    DIRECTION OUTPUT ;
    USE SIGNAL ;
    PORT
      LAYER M5 ;
        RECT  61.584 21.408 61.608 21.6 ;
    END
  END o3[66]
  PIN o3[67]
    DIRECTION OUTPUT ;
    USE SIGNAL ;
    PORT
      LAYER M5 ;
        RECT  61.728 21.408 61.752 21.6 ;
    END
  END o3[67]
  PIN o3[68]
    DIRECTION OUTPUT ;
    USE SIGNAL ;
    PORT
      LAYER M5 ;
        RECT  62.064 21.408 62.088 21.6 ;
    END
  END o3[68]
  PIN o3[69]
    DIRECTION OUTPUT ;
    USE SIGNAL ;
    PORT
      LAYER M5 ;
        RECT  62.256 21.408 62.28 21.6 ;
    END
  END o3[69]
  PIN o3[6]
    DIRECTION OUTPUT ;
    USE SIGNAL ;
    PORT
      LAYER M5 ;
        RECT  51.6 21.408 51.624 21.6 ;
    END
  END o3[6]
  PIN o3[70]
    DIRECTION OUTPUT ;
    USE SIGNAL ;
    PORT
      LAYER M5 ;
        RECT  62.4 21.408 62.424 21.6 ;
    END
  END o3[70]
  PIN o3[71]
    DIRECTION OUTPUT ;
    USE SIGNAL ;
    PORT
      LAYER M5 ;
        RECT  62.592 21.408 62.616 21.6 ;
    END
  END o3[71]
  PIN o3[72]
    DIRECTION OUTPUT ;
    USE SIGNAL ;
    PORT
      LAYER M5 ;
        RECT  62.736 21.408 62.76 21.6 ;
    END
  END o3[72]
  PIN o3[73]
    DIRECTION OUTPUT ;
    USE SIGNAL ;
    PORT
      LAYER M5 ;
        RECT  62.928 21.408 62.952 21.6 ;
    END
  END o3[73]
  PIN o3[74]
    DIRECTION OUTPUT ;
    USE SIGNAL ;
    PORT
      LAYER M5 ;
        RECT  63.072 21.408 63.096 21.6 ;
    END
  END o3[74]
  PIN o3[75]
    DIRECTION OUTPUT ;
    USE SIGNAL ;
    PORT
      LAYER M5 ;
        RECT  63.216 21.408 63.24 21.6 ;
    END
  END o3[75]
  PIN o3[76]
    DIRECTION OUTPUT ;
    USE SIGNAL ;
    PORT
      LAYER M5 ;
        RECT  63.408 21.408 63.432 21.6 ;
    END
  END o3[76]
  PIN o3[77]
    DIRECTION OUTPUT ;
    USE SIGNAL ;
    PORT
      LAYER M5 ;
        RECT  63.552 21.408 63.576 21.6 ;
    END
  END o3[77]
  PIN o3[78]
    DIRECTION OUTPUT ;
    USE SIGNAL ;
    PORT
      LAYER M5 ;
        RECT  63.744 21.408 63.768 21.6 ;
    END
  END o3[78]
  PIN o3[79]
    DIRECTION OUTPUT ;
    USE SIGNAL ;
    PORT
      LAYER M5 ;
        RECT  63.888 21.408 63.912 21.6 ;
    END
  END o3[79]
  PIN o3[7]
    DIRECTION OUTPUT ;
    USE SIGNAL ;
    PORT
      LAYER M5 ;
        RECT  51.744 21.408 51.768 21.6 ;
    END
  END o3[7]
  PIN o3[80]
    DIRECTION OUTPUT ;
    USE SIGNAL ;
    PORT
      LAYER M5 ;
        RECT  64.08 21.408 64.104 21.6 ;
    END
  END o3[80]
  PIN o3[81]
    DIRECTION OUTPUT ;
    USE SIGNAL ;
    PORT
      LAYER M5 ;
        RECT  64.224 21.408 64.248 21.6 ;
    END
  END o3[81]
  PIN o3[82]
    DIRECTION OUTPUT ;
    USE SIGNAL ;
    PORT
      LAYER M5 ;
        RECT  64.416 21.408 64.44 21.6 ;
    END
  END o3[82]
  PIN o3[83]
    DIRECTION OUTPUT ;
    USE SIGNAL ;
    PORT
      LAYER M5 ;
        RECT  64.56 21.408 64.584 21.6 ;
    END
  END o3[83]
  PIN o3[84]
    DIRECTION OUTPUT ;
    USE SIGNAL ;
    PORT
      LAYER M5 ;
        RECT  64.752 21.408 64.776 21.6 ;
    END
  END o3[84]
  PIN o3[85]
    DIRECTION OUTPUT ;
    USE SIGNAL ;
    PORT
      LAYER M5 ;
        RECT  64.896 21.408 64.92 21.6 ;
    END
  END o3[85]
  PIN o3[86]
    DIRECTION OUTPUT ;
    USE SIGNAL ;
    PORT
      LAYER M5 ;
        RECT  65.088 21.408 65.112 21.6 ;
    END
  END o3[86]
  PIN o3[87]
    DIRECTION OUTPUT ;
    USE SIGNAL ;
    PORT
      LAYER M5 ;
        RECT  65.232 21.408 65.256 21.6 ;
    END
  END o3[87]
  PIN o3[88]
    DIRECTION OUTPUT ;
    USE SIGNAL ;
    PORT
      LAYER M5 ;
        RECT  65.424 21.408 65.448 21.6 ;
    END
  END o3[88]
  PIN o3[89]
    DIRECTION OUTPUT ;
    USE SIGNAL ;
    PORT
      LAYER M5 ;
        RECT  65.568 21.408 65.592 21.6 ;
    END
  END o3[89]
  PIN o3[8]
    DIRECTION OUTPUT ;
    USE SIGNAL ;
    PORT
      LAYER M5 ;
        RECT  51.936 21.408 51.96 21.6 ;
    END
  END o3[8]
  PIN o3[90]
    DIRECTION OUTPUT ;
    USE SIGNAL ;
    PORT
      LAYER M5 ;
        RECT  65.76 21.408 65.784 21.6 ;
    END
  END o3[90]
  PIN o3[91]
    DIRECTION OUTPUT ;
    USE SIGNAL ;
    PORT
      LAYER M5 ;
        RECT  65.904 21.408 65.928 21.6 ;
    END
  END o3[91]
  PIN o3[92]
    DIRECTION OUTPUT ;
    USE SIGNAL ;
    PORT
      LAYER M5 ;
        RECT  66.048 21.408 66.072 21.6 ;
    END
  END o3[92]
  PIN o3[93]
    DIRECTION OUTPUT ;
    USE SIGNAL ;
    PORT
      LAYER M5 ;
        RECT  66.24 21.408 66.264 21.6 ;
    END
  END o3[93]
  PIN o3[94]
    DIRECTION OUTPUT ;
    USE SIGNAL ;
    PORT
      LAYER M5 ;
        RECT  66.384 21.408 66.408 21.6 ;
    END
  END o3[94]
  PIN o3[95]
    DIRECTION OUTPUT ;
    USE SIGNAL ;
    PORT
      LAYER M5 ;
        RECT  66.576 21.408 66.6 21.6 ;
    END
  END o3[95]
  PIN o3[96]
    DIRECTION OUTPUT ;
    USE SIGNAL ;
    PORT
      LAYER M5 ;
        RECT  66.72 21.408 66.744 21.6 ;
    END
  END o3[96]
  PIN o3[97]
    DIRECTION OUTPUT ;
    USE SIGNAL ;
    PORT
      LAYER M5 ;
        RECT  66.912 21.408 66.936 21.6 ;
    END
  END o3[97]
  PIN o3[98]
    DIRECTION OUTPUT ;
    USE SIGNAL ;
    PORT
      LAYER M5 ;
        RECT  67.056 21.408 67.08 21.6 ;
    END
  END o3[98]
  PIN o3[99]
    DIRECTION OUTPUT ;
    USE SIGNAL ;
    PORT
      LAYER M5 ;
        RECT  67.248 21.408 67.272 21.6 ;
    END
  END o3[99]
  PIN o3[9]
    DIRECTION OUTPUT ;
    USE SIGNAL ;
    PORT
      LAYER M5 ;
        RECT  52.08 21.408 52.104 21.6 ;
    END
  END o3[9]
  PIN rs
    DIRECTION INPUT ;
    USE SIGNAL ;
    PORT
      LAYER M4 ;
        RECT  0 10.8 0.192 10.824 ;
    END
    PORT
      LAYER M4 ;
        RECT  0.156 10.8 2.408 10.824 ;
    END
  END rs
  PIN VDD
    DIRECTION INOUT ;
    USE POWER ;
    PORT
      LAYER M5 ;
        RECT  75.492 2.151 75.612 19.449 ;
        RECT  72.792 2.151 72.912 19.449 ;
        RECT  70.092 2.151 70.212 19.449 ;
        RECT  67.392 2.151 67.512 19.449 ;
        RECT  64.692 2.151 64.812 19.449 ;
        RECT  61.992 2.151 62.112 19.449 ;
        RECT  59.292 2.151 59.412 19.449 ;
        RECT  56.592 2.151 56.712 19.449 ;
        RECT  53.892 2.151 54.012 19.449 ;
        RECT  51.192 2.151 51.312 19.449 ;
        RECT  48.492 2.151 48.612 19.449 ;
        RECT  45.792 2.151 45.912 19.449 ;
        RECT  43.092 2.151 43.212 19.449 ;
        RECT  40.392 2.151 40.512 19.449 ;
        RECT  37.692 2.151 37.812 19.449 ;
        RECT  34.992 2.151 35.112 19.449 ;
        RECT  32.292 2.151 32.412 19.449 ;
        RECT  29.592 2.151 29.712 19.449 ;
        RECT  26.892 2.151 27.012 19.449 ;
        RECT  24.192 2.151 24.312 19.449 ;
        RECT  21.492 2.151 21.612 19.449 ;
        RECT  18.792 2.151 18.912 19.449 ;
        RECT  16.092 2.151 16.212 19.449 ;
        RECT  13.392 2.151 13.512 19.449 ;
        RECT  10.692 2.151 10.812 19.449 ;
        RECT  7.992 2.151 8.112 19.449 ;
        RECT  5.292 2.151 5.412 19.449 ;
        RECT  2.592 2.151 2.712 19.449 ;
    END
  END VDD
  PIN VSS
    DIRECTION INOUT ;
    USE GROUND ;
    PORT
      LAYER M5 ;
        RECT  75.3 2.137 75.42 19.463 ;
        RECT  72.6 2.137 72.72 19.463 ;
        RECT  69.9 2.137 70.02 19.463 ;
        RECT  67.2 2.137 67.32 19.463 ;
        RECT  64.5 2.137 64.62 19.463 ;
        RECT  61.8 2.137 61.92 19.463 ;
        RECT  59.1 2.137 59.22 19.463 ;
        RECT  56.4 2.137 56.52 19.463 ;
        RECT  53.7 2.137 53.82 19.463 ;
        RECT  51 2.137 51.12 19.463 ;
        RECT  48.3 2.137 48.42 19.463 ;
        RECT  45.6 2.137 45.72 19.463 ;
        RECT  42.9 2.137 43.02 19.463 ;
        RECT  40.2 2.137 40.32 19.463 ;
        RECT  37.5 2.137 37.62 19.463 ;
        RECT  34.8 2.137 34.92 19.463 ;
        RECT  32.1 2.137 32.22 19.463 ;
        RECT  29.4 2.137 29.52 19.463 ;
        RECT  26.7 2.137 26.82 19.463 ;
        RECT  24 2.137 24.12 19.463 ;
        RECT  21.3 2.137 21.42 19.463 ;
        RECT  18.6 2.137 18.72 19.463 ;
        RECT  15.9 2.137 16.02 19.463 ;
        RECT  13.2 2.137 13.32 19.463 ;
        RECT  10.5 2.137 10.62 19.463 ;
        RECT  7.8 2.137 7.92 19.463 ;
        RECT  5.1 2.137 5.22 19.463 ;
        RECT  2.4 2.137 2.52 19.463 ;
    END
  END VSS
  # OT_OBS_CLOSED layer=M5 d_um=1.536 added=116
  OBS
    LAYER RVTN ;
     RECT  2.16 2.16 75.6 2.295 ;
     RECT  2.16 2.565 75.6 2.835 ;
     RECT  2.16 3.105 75.6 3.375 ;
     RECT  2.16 3.645 75.6 3.915 ;
     RECT  2.16 4.185 75.6 4.455 ;
     RECT  2.16 4.725 75.6 4.995 ;
     RECT  2.16 5.265 75.6 5.535 ;
     RECT  2.16 5.805 75.6 6.075 ;
     RECT  2.16 6.345 75.6 6.615 ;
     RECT  2.16 6.885 75.6 7.155 ;
     RECT  2.16 7.425 75.6 7.695 ;
     RECT  2.16 7.965 75.6 8.235 ;
     RECT  2.16 8.505 75.6 8.775 ;
     RECT  2.16 9.045 75.6 9.315 ;
     RECT  2.16 9.585 75.6 9.855 ;
     RECT  2.16 10.125 75.6 10.395 ;
     RECT  2.16 10.665 75.6 10.935 ;
     RECT  2.16 11.205 75.6 11.475 ;
     RECT  2.16 11.745 75.6 12.015 ;
     RECT  2.16 12.285 75.6 12.555 ;
     RECT  2.16 12.825 75.6 13.095 ;
     RECT  2.16 13.365 75.6 13.635 ;
     RECT  2.16 13.905 75.6 14.175 ;
     RECT  2.16 14.445 75.6 14.715 ;
     RECT  2.16 14.985 75.6 15.255 ;
     RECT  2.16 15.525 75.6 15.795 ;
     RECT  2.16 16.065 75.6 16.335 ;
     RECT  2.16 16.605 75.6 16.875 ;
     RECT  2.16 17.145 75.6 17.415 ;
     RECT  2.16 17.685 75.6 17.955 ;
     RECT  2.16 18.225 75.6 18.495 ;
     RECT  2.16 18.765 75.6 19.035 ;
     RECT  2.16 19.305 75.6 19.44 ;
    LAYER RVTP ;
     RECT  2.16 2.295 75.6 2.565 ;
     RECT  2.16 2.835 75.6 3.105 ;
     RECT  2.16 3.375 75.6 3.645 ;
     RECT  2.16 3.915 75.6 4.185 ;
     RECT  2.16 4.455 75.6 4.725 ;
     RECT  2.16 4.995 75.6 5.265 ;
     RECT  2.16 5.535 75.6 5.805 ;
     RECT  2.16 6.075 75.6 6.345 ;
     RECT  2.16 6.615 75.6 6.885 ;
     RECT  2.16 7.155 75.6 7.425 ;
     RECT  2.16 7.695 75.6 7.965 ;
     RECT  2.16 8.235 75.6 8.505 ;
     RECT  2.16 8.775 75.6 9.045 ;
     RECT  2.16 9.315 75.6 9.585 ;
     RECT  2.16 9.855 75.6 10.125 ;
     RECT  2.16 10.395 75.6 10.665 ;
     RECT  2.16 10.935 75.6 11.205 ;
     RECT  2.16 11.475 75.6 11.745 ;
     RECT  2.16 12.015 75.6 12.285 ;
     RECT  2.16 12.555 75.6 12.825 ;
     RECT  2.16 13.095 75.6 13.365 ;
     RECT  2.16 13.635 75.6 13.905 ;
     RECT  2.16 14.175 75.6 14.445 ;
     RECT  2.16 14.715 75.6 14.985 ;
     RECT  2.16 15.255 75.6 15.525 ;
     RECT  2.16 15.795 75.6 16.065 ;
     RECT  2.16 16.335 75.6 16.605 ;
     RECT  2.16 16.875 75.6 17.145 ;
     RECT  2.16 17.415 75.6 17.685 ;
     RECT  2.16 17.955 75.6 18.225 ;
     RECT  2.16 18.495 75.6 18.765 ;
     RECT  2.16 19.035 75.6 19.305 ;
    LAYER M1 ;
     RECT  2.16 2.151 75.6 19.449 ;
    LAYER M2 ;
     RECT  2.16 2.151 5.323 19.449 ;
     RECT  5.323 2.106 5.567 19.449 ;
     RECT  5.567 2.151 12.343 19.449 ;
     RECT  12.343 2.106 14.827 19.449 ;
     RECT  14.827 2.106 16.519 19.494 ;
     RECT  16.519 2.106 18.859 19.566 ;
     RECT  18.859 1.962 21.119 19.566 ;
     RECT  21.119 2.106 22.567 19.566 ;
     RECT  22.567 2.034 22.819 19.566 ;
     RECT  22.819 2.034 22.855 19.602 ;
     RECT  22.855 2.034 25.159 19.674 ;
     RECT  25.159 1.998 25.223 19.674 ;
     RECT  25.223 1.998 29.083 19.602 ;
     RECT  29.083 1.962 31.523 19.602 ;
     RECT  31.523 1.962 33.079 19.566 ;
     RECT  33.079 1.881 33.287 19.566 ;
     RECT  33.287 1.881 35.375 19.53 ;
     RECT  35.375 1.881 36.743 19.449 ;
     RECT  36.743 1.962 44.483 19.449 ;
     RECT  44.483 2.106 54.527 19.449 ;
     RECT  54.527 2.151 75.6 19.449 ;
     RECT  75.6 2.421 75.612 19.179 ;
    LAYER M3 ;
     RECT  62.64 0.187 62.658 0.523 ;
     RECT  63.972 0.187 63.99 0.523 ;
     RECT  65.196 0.187 65.214 0.523 ;
     RECT  40.608 0.187 40.626 0.571 ;
     RECT  41.4 0.187 41.85 0.571 ;
     RECT  43.344 0.187 43.362 0.571 ;
     RECT  48.888 0.187 48.906 0.571 ;
     RECT  52.02 0.187 52.038 0.571 ;
     RECT  54.396 0.187 55.422 0.571 ;
     RECT  60.156 0.187 60.174 0.571 ;
     RECT  60.948 0.187 60.966 0.571 ;
     RECT  65.988 0.187 66.006 0.571 ;
     RECT  66.924 0.523 66.942 0.571 ;
     RECT  42.588 0.187 42.606 1.099 ;
     RECT  43.344 0.571 43.614 1.099 ;
     RECT  44.82 0.523 44.838 1.099 ;
     RECT  45.936 0.571 46.638 1.099 ;
     RECT  48.888 0.571 52.038 1.099 ;
     RECT  54.036 0.571 55.422 1.099 ;
     RECT  57.924 0.187 57.942 1.099 ;
     RECT  59.256 0.187 59.274 1.099 ;
     RECT  60.156 0.571 60.966 1.099 ;
     RECT  61.776 0.523 63.126 1.099 ;
     RECT  63.972 0.523 65.214 1.099 ;
     RECT  65.988 0.571 66.942 1.099 ;
     RECT  68.22 0.187 68.238 1.099 ;
     RECT  69.012 0.187 69.03 1.099 ;
     RECT  70.308 0.523 70.326 1.099 ;
     RECT  53.352 1.099 55.422 1.147 ;
     RECT  71.46 0.187 71.982 1.147 ;
     RECT  48.276 1.099 52.038 1.675 ;
     RECT  56.844 0.187 56.862 1.675 ;
     RECT  57.636 1.099 57.942 1.675 ;
     RECT  59.256 1.099 66.942 1.675 ;
     RECT  68.22 1.099 70.326 1.675 ;
     RECT  6.264 0.571 6.282 1.723 ;
     RECT  11.592 0.187 11.61 1.723 ;
     RECT  12.564 0.571 12.582 1.723 ;
     RECT  17.1 0.571 17.118 1.723 ;
     RECT  19.8 1.099 19.818 1.723 ;
     RECT  26.604 0.523 26.622 1.723 ;
     RECT  35.928 0.187 35.946 1.723 ;
     RECT  39.564 0.187 39.582 1.723 ;
     RECT  40.608 0.571 41.85 1.723 ;
     RECT  42.588 1.099 43.614 1.723 ;
     RECT  48.276 1.675 52.614 1.723 ;
     RECT  53.352 1.147 55.674 1.723 ;
     RECT  56.556 1.675 56.862 1.723 ;
     RECT  57.636 1.675 67.158 1.723 ;
     RECT  67.968 1.675 70.326 1.723 ;
     RECT  71.46 1.147 72.27 1.723 ;
     RECT  73.224 1.099 73.242 1.723 ;
     RECT  7.74 1.723 43.614 2.155 ;
     RECT  44.352 1.099 47.286 2.155 ;
     RECT  48.06 1.723 52.614 2.155 ;
     RECT  53.352 1.723 70.722 2.155 ;
     RECT  7.74 2.155 70.722 2.227 ;
     RECT  71.46 1.723 73.242 2.227 ;
     RECT  4.464 1.723 7.002 2.251 ;
     RECT  7.74 2.227 73.242 2.251 ;
     RECT  4.464 2.251 73.242 2.371 ;
     RECT  2.415 2.143 2.505 2.413 ;
     RECT  75.315 2.143 75.405 2.413 ;
     RECT  4.284 2.371 73.242 2.795 ;
     RECT  4.608 2.795 73.242 3.029 ;
     RECT  4.608 3.029 73.062 3.065 ;
     RECT  4.716 3.065 73.062 3.299 ;
     RECT  4.716 3.299 72.954 4.109 ;
     RECT  4.716 4.109 72.897 4.495 ;
     RECT  4.68 4.495 72.897 4.496 ;
     RECT  44.316 4.496 72.897 4.919 ;
     RECT  44.676 4.919 72.897 5.027 ;
     RECT  4.68 4.496 43.578 5.063 ;
     RECT  41.724 5.063 43.578 5.227 ;
     RECT  44.784 5.027 72.897 5.459 ;
     RECT  4.68 5.063 40.914 5.531 ;
     RECT  44.784 5.459 49.914 5.567 ;
     RECT  2.415 2.413 2.697 5.575 ;
     RECT  50.688 5.459 72.897 5.603 ;
     RECT  41.724 5.227 43.758 5.729 ;
     RECT  5.076 5.531 40.914 5.801 ;
     RECT  5.115 5.801 40.914 5.881 ;
     RECT  5.115 5.881 41.094 5.909 ;
     RECT  23.544 5.909 41.094 6.179 ;
     RECT  44.856 5.567 49.914 6.619 ;
     RECT  50.94 5.603 72.897 6.619 ;
     RECT  26.1 6.179 41.094 6.683 ;
     RECT  41.868 5.729 43.758 7.727 ;
     RECT  2.415 5.575 3.114 8.159 ;
     RECT  2.415 8.159 2.697 8.275 ;
     RECT  44.856 6.619 72.897 9.419 ;
     RECT  45.615 9.419 72.897 10.049 ;
     RECT  2.304 8.275 2.697 10.829 ;
     RECT  23.544 6.179 25.362 10.829 ;
     RECT  26.1 6.683 27.594 10.831 ;
     RECT  28.368 6.683 41.094 10.831 ;
     RECT  41.868 7.727 43.542 11.129 ;
     RECT  41.868 11.129 43.197 11.705 ;
     RECT  46.908 10.049 72.897 11.741 ;
     RECT  46.908 11.741 46.926 12.317 ;
     RECT  41.868 11.705 42.102 12.821 ;
     RECT  44.856 9.419 44.874 12.857 ;
     RECT  23.544 10.829 25.29 13.099 ;
     RECT  26.1 10.831 41.094 13.433 ;
     RECT  42.084 12.821 42.102 13.675 ;
     RECT  42.915 11.705 43.197 13.675 ;
     RECT  45.615 10.049 45.897 13.801 ;
     RECT  47.772 11.741 72.897 13.801 ;
     RECT  42.876 13.675 43.197 13.837 ;
     RECT  45.615 13.801 72.897 13.837 ;
     RECT  41.76 13.675 42.102 13.909 ;
     RECT  42.84 13.837 43.197 13.909 ;
     RECT  5.115 5.909 22.806 13.945 ;
     RECT  23.544 13.099 25.362 13.945 ;
     RECT  45.036 13.837 72.897 13.945 ;
     RECT  5.115 13.945 25.362 13.981 ;
     RECT  26.1 13.433 40.554 13.981 ;
     RECT  41.76 13.909 43.197 14.099 ;
     RECT  42.156 14.099 43.197 14.107 ;
     RECT  43.956 14.071 43.974 14.107 ;
     RECT  42.156 14.107 43.974 14.207 ;
     RECT  42.3 14.207 43.974 14.405 ;
     RECT  5.115 13.981 40.554 14.413 ;
     RECT  42.444 14.405 43.974 14.413 ;
     RECT  44.892 13.945 72.897 14.413 ;
     RECT  5.115 14.413 40.842 14.521 ;
     RECT  5.115 14.521 40.95 14.683 ;
     RECT  5.115 14.683 41.238 14.917 ;
     RECT  5.115 14.917 41.454 15.061 ;
     RECT  42.444 14.413 72.897 15.151 ;
     RECT  5.115 15.061 41.49 15.871 ;
     RECT  42.408 15.151 72.897 15.871 ;
     RECT  5.115 15.871 72.897 16.951 ;
     RECT  4.86 16.951 72.897 17.077 ;
     RECT  4.644 17.077 72.897 17.249 ;
     RECT  4.716 17.249 72.897 18.031 ;
     RECT  4.68 18.031 72.897 18.571 ;
     RECT  4.68 18.571 72.99 18.841 ;
     RECT  4.392 18.841 73.062 18.995 ;
     RECT  4.572 18.995 73.062 19.111 ;
     RECT  2.415 10.829 2.697 19.187 ;
     RECT  75.315 2.413 75.597 19.187 ;
     RECT  4.572 19.111 73.242 19.265 ;
     RECT  6.768 19.265 73.242 19.379 ;
     RECT  6.768 19.379 52.398 19.409 ;
     RECT  6.768 19.409 13.374 19.421 ;
     RECT  2.415 19.187 2.505 19.457 ;
     RECT  4.716 19.265 6.03 19.457 ;
     RECT  7.815 19.421 9.63 19.457 ;
     RECT  14.112 19.409 52.398 19.457 ;
     RECT  75.315 19.187 75.405 19.457 ;
     RECT  24.48 19.457 52.398 19.469 ;
     RECT  8.172 19.457 9.63 19.565 ;
     RECT  14.112 19.457 23.526 19.571 ;
     RECT  24.48 19.469 47.394 19.613 ;
     RECT  48.204 19.469 52.398 19.613 ;
     RECT  10.44 19.421 13.374 19.661 ;
     RECT  24.48 19.613 37.458 19.679 ;
     RECT  4.716 19.457 5.058 19.997 ;
     RECT  5.868 19.457 6.03 19.997 ;
     RECT  7.056 19.421 7.074 19.997 ;
     RECT  8.208 19.565 9.63 19.997 ;
     RECT  10.476 19.661 13.374 19.997 ;
     RECT  14.112 19.571 16.362 19.997 ;
     RECT  17.244 19.571 23.526 19.997 ;
     RECT  24.48 19.679 24.678 19.997 ;
     RECT  25.812 19.679 37.458 19.997 ;
     RECT  38.268 19.613 47.394 19.997 ;
     RECT  48.204 19.613 50.814 19.997 ;
     RECT  51.624 19.613 52.398 19.997 ;
     RECT  53.136 19.379 73.242 19.997 ;
     RECT  6.012 19.997 6.03 20.045 ;
     RECT  14.508 19.997 16.362 20.045 ;
     RECT  20.052 19.997 23.526 20.045 ;
     RECT  24.588 19.997 24.678 20.045 ;
     RECT  4.716 19.997 4.734 20.573 ;
     RECT  8.46 19.997 8.478 20.573 ;
     RECT  9.576 19.997 9.63 20.573 ;
     RECT  11.232 19.997 13.194 20.573 ;
     RECT  14.508 20.045 14.526 20.573 ;
     RECT  15.84 20.045 16.326 20.573 ;
     RECT  17.244 19.997 17.262 20.573 ;
     RECT  18.18 19.997 19.242 20.573 ;
     RECT  20.052 20.045 20.178 20.573 ;
     RECT  20.952 20.045 21.258 20.573 ;
     RECT  22.536 20.045 23.526 20.573 ;
     RECT  24.66 20.045 24.678 20.573 ;
     RECT  25.812 19.997 26.118 20.573 ;
     RECT  27.504 19.997 28.818 20.573 ;
     RECT  29.736 19.997 30.87 20.573 ;
     RECT  31.644 19.997 35.406 20.573 ;
     RECT  36.18 19.997 37.458 20.573 ;
     RECT  38.268 19.997 38.646 20.573 ;
     RECT  39.456 19.997 41.49 20.573 ;
     RECT  42.588 19.997 44.262 20.573 ;
     RECT  45.108 19.997 47.394 20.573 ;
     RECT  48.204 19.997 49.626 20.573 ;
     RECT  50.724 19.997 50.814 20.573 ;
     RECT  51.624 19.997 52.218 20.573 ;
     RECT  53.172 19.997 55.278 20.573 ;
     RECT  56.052 19.997 67.194 20.573 ;
     RECT  67.932 19.997 72.774 20.573 ;
     RECT  12.168 20.573 12.186 20.621 ;
     RECT  25.812 20.573 25.83 20.621 ;
     RECT  31.752 20.573 32.094 20.621 ;
     RECT  38.268 20.573 38.286 20.621 ;
     RECT  40.068 20.573 40.086 20.621 ;
     RECT  42.588 20.573 43.182 20.621 ;
     RECT  48.96 20.573 49.626 20.621 ;
     RECT  50.724 20.573 50.742 20.621 ;
     RECT  53.316 20.573 53.658 20.621 ;
     RECT  54.9 20.573 55.134 20.621 ;
     RECT  59.436 20.573 59.454 20.621 ;
     RECT  62.928 20.573 63.27 20.621 ;
     RECT  64.404 20.573 65.538 20.621 ;
     RECT  66.996 20.573 67.086 20.621 ;
     RECT  68.04 20.573 68.058 20.621 ;
     RECT  69.264 20.573 69.282 20.621 ;
     RECT  70.308 20.573 71.19 20.621 ;
     RECT  72.468 20.573 72.486 20.621 ;
     RECT  9.576 20.573 9.594 20.669 ;
     RECT  18.504 20.573 18.522 20.669 ;
     RECT  36.612 20.573 36.63 20.669 ;
     RECT  41.472 20.573 41.49 20.669 ;
     RECT  45.144 20.573 45.162 20.669 ;
     RECT  52.092 20.573 52.11 20.669 ;
     RECT  53.568 20.621 53.586 20.669 ;
     RECT  56.952 20.573 56.97 20.669 ;
     RECT  60.408 20.573 61.254 20.669 ;
     RECT  62.172 20.573 62.19 20.669 ;
     RECT  62.964 20.621 63.162 20.669 ;
     RECT  64.404 20.621 64.422 20.669 ;
     RECT  65.34 20.621 65.358 20.669 ;
     RECT  67.068 20.621 67.086 20.669 ;
     RECT  71.172 20.621 71.19 20.669 ;
     RECT  61.236 20.669 61.254 20.717 ;
     RECT  62.964 20.669 62.982 20.717 ;
     RECT  70.344 20.621 70.362 20.717 ;
     RECT  48.96 20.621 48.978 21.389 ;
     RECT  34.704 20.573 34.722 21.485 ;
    LAYER M4 ;
     RECT  2.408 2.148 2.512 19.452 ;
     RECT  2.512 2.418 2.704 19.182 ;
     RECT  4.645 20.544 4.745 20.568 ;
     RECT  4.501 19.2 4.837 19.224 ;
     RECT  4.837 19.2 4.981 19.416 ;
     RECT  4.453 1.728 5.108 1.752 ;
     RECT  4.559 2.832 5.108 2.856 ;
     RECT  4.597 3.984 5.108 4.008 ;
     RECT  4.981 19.2 5.108 20.04 ;
     RECT  5.108 1.728 5.404 20.04 ;
     RECT  5.404 18.144 6.041 20.04 ;
     RECT  6.253 0.576 6.337 0.6 ;
     RECT  5.404 1.728 6.545 4.344 ;
     RECT  5.404 5.76 6.649 5.784 ;
     RECT  6.505 14.64 6.661 14.664 ;
     RECT  6.649 5.76 7.004 6.12 ;
     RECT  6.545 3.936 7.045 4.344 ;
     RECT  7.004 5.712 7.045 6.12 ;
     RECT  6.661 14.64 7.333 15.096 ;
     RECT  5.404 16.08 7.333 16.104 ;
     RECT  6.545 1.728 7.808 2.856 ;
     RECT  7.045 3.936 7.808 6.12 ;
     RECT  7.333 14.64 7.808 16.104 ;
     RECT  7.405 17.088 7.808 17.112 ;
     RECT  6.041 18.144 7.808 19.992 ;
     RECT  7.808 1.728 8.104 19.992 ;
     RECT  8.104 14.64 8.201 17.112 ;
     RECT  8.104 4.752 8.243 6.312 ;
     RECT  8.104 18.144 8.444 19.992 ;
     RECT  8.201 14.64 8.453 16.968 ;
     RECT  8.444 18.144 9.029 20.568 ;
     RECT  8.104 1.728 9.164 3.672 ;
     RECT  8.243 4.752 9.164 6.024 ;
     RECT  9.164 1.728 9.251 6.024 ;
     RECT  9.029 20.544 9.493 20.568 ;
     RECT  9.493 20.544 9.605 20.664 ;
     RECT  8.453 14.64 9.637 14.952 ;
     RECT  9.605 20.544 9.641 20.568 ;
     RECT  9.251 4.752 9.781 6.024 ;
     RECT  9.781 4.752 10.213 6.072 ;
     RECT  9.251 1.728 10.22 3.672 ;
     RECT  10.213 4.752 10.22 6.12 ;
     RECT  9.637 14.448 10.285 14.952 ;
     RECT  8.453 15.984 10.285 16.968 ;
     RECT  9.029 18.144 10.309 19.416 ;
     RECT  10.285 14.448 10.429 16.968 ;
     RECT  10.309 18.144 10.429 19.992 ;
     RECT  10.22 1.728 10.508 6.12 ;
     RECT  10.429 14.448 10.508 19.992 ;
     RECT  10.508 1.728 10.804 19.992 ;
     RECT  10.804 13.68 10.981 19.992 ;
     RECT  10.981 13.68 11.333 20.568 ;
     RECT  11.333 19.968 11.62 20.568 ;
     RECT  11.581 0.192 12.083 0.216 ;
     RECT  11.62 19.968 12.197 20.616 ;
     RECT  11.333 13.68 12.469 18.792 ;
     RECT  12.197 19.968 12.469 20.568 ;
     RECT  12.509 0.576 12.593 0.6 ;
     RECT  10.804 1.728 13.208 6.12 ;
     RECT  12.469 13.68 13.208 20.568 ;
     RECT  13.208 1.728 13.228 20.568 ;
     RECT  13.228 1.728 13.504 19.992 ;
     RECT  13.504 13.68 13.619 19.992 ;
     RECT  13.619 13.68 14.236 18.936 ;
     RECT  13.619 19.968 14.341 19.992 ;
     RECT  14.236 13.68 15.253 18.84 ;
     RECT  15.253 13.68 15.829 18.936 ;
     RECT  14.341 19.968 15.829 20.568 ;
     RECT  13.504 1.728 15.908 6.12 ;
     RECT  15.829 13.68 15.908 20.568 ;
     RECT  15.908 1.728 16.204 20.568 ;
     RECT  16.204 13.68 16.373 20.568 ;
     RECT  17.045 0.576 17.129 0.6 ;
     RECT  16.373 13.68 17.129 19.464 ;
     RECT  17.129 13.68 17.548 18.984 ;
     RECT  16.373 20.544 17.653 20.568 ;
     RECT  16.204 1.728 17.881 6.216 ;
     RECT  17.653 19.968 18.469 20.568 ;
     RECT  18.469 19.968 18.556 20.664 ;
     RECT  17.881 1.728 18.608 6.312 ;
     RECT  17.548 13.68 18.608 18.936 ;
     RECT  18.556 19.968 18.608 20.568 ;
     RECT  18.608 1.728 18.904 20.568 ;
     RECT  18.904 1.728 19.757 6.312 ;
     RECT  19.757 1.728 19.789 6.216 ;
     RECT  19.789 1.104 20.099 6.216 ;
     RECT  18.904 13.68 20.293 18.936 ;
     RECT  18.904 19.968 20.293 20.568 ;
     RECT  20.293 13.68 21.269 20.568 ;
     RECT  20.099 1.728 21.308 6.216 ;
     RECT  21.269 13.68 21.308 20.04 ;
     RECT  21.308 1.728 21.604 20.04 ;
     RECT  21.604 13.68 22.309 20.04 ;
     RECT  22.309 13.68 23.537 20.568 ;
     RECT  21.604 1.728 24.008 6.12 ;
     RECT  23.537 13.68 24.008 20.04 ;
     RECT  24.008 1.728 24.304 20.04 ;
     RECT  24.304 13.68 24.617 20.04 ;
     RECT  24.304 1.728 25.265 6.168 ;
     RECT  24.304 10.8 25.373 10.824 ;
     RECT  24.617 13.68 25.588 19.416 ;
     RECT  24.62 20.544 25.772 20.568 ;
     RECT  25.772 20.544 25.859 20.616 ;
     RECT  25.859 20.544 26.129 20.568 ;
     RECT  25.588 13.68 26.149 19.464 ;
     RECT  25.265 1.728 26.708 6.12 ;
     RECT  26.149 13.68 26.708 19.992 ;
     RECT  26.593 0.528 26.915 0.552 ;
     RECT  26.708 1.728 27.004 19.992 ;
     RECT  27.004 13.68 27.203 19.992 ;
     RECT  27.157 21.36 27.301 21.384 ;
     RECT  27.301 21.36 27.493 21.48 ;
     RECT  27.004 1.728 27.641 6.264 ;
     RECT  27.203 13.68 28.501 19.224 ;
     RECT  28.501 13.68 28.844 19.272 ;
     RECT  27.493 20.544 28.844 21.48 ;
     RECT  27.641 1.728 29.408 6.168 ;
     RECT  28.844 13.68 29.408 21.48 ;
     RECT  29.408 1.728 29.411 21.48 ;
     RECT  29.411 1.728 29.603 19.56 ;
     RECT  29.603 1.728 29.704 19.368 ;
     RECT  29.704 13.824 30.709 19.368 ;
     RECT  29.411 20.544 30.709 21.48 ;
     RECT  30.709 13.824 30.769 21.48 ;
     RECT  29.704 1.728 32.108 6.168 ;
     RECT  30.769 13.68 32.108 21.48 ;
     RECT  32.108 1.728 32.404 21.48 ;
     RECT  32.404 13.68 34.733 21.48 ;
     RECT  32.404 1.728 34.808 6.312 ;
     RECT  34.733 13.68 34.808 20.568 ;
     RECT  34.808 1.728 35.104 20.568 ;
     RECT  35.104 13.68 35.201 20.568 ;
     RECT  35.201 17.376 35.596 20.568 ;
     RECT  35.596 17.376 35.891 19.512 ;
     RECT  35.873 0.192 35.957 0.216 ;
     RECT  35.201 13.68 36.457 16.392 ;
     RECT  35.891 17.376 36.457 19.368 ;
     RECT  36.457 13.68 36.497 19.368 ;
     RECT  35.596 20.544 36.601 20.568 ;
     RECT  36.601 20.544 36.755 20.664 ;
     RECT  35.104 1.728 37.508 6.12 ;
     RECT  36.497 13.68 37.508 19.272 ;
     RECT  37.508 1.728 37.525 19.452 ;
     RECT  36.755 20.544 37.525 20.568 ;
     RECT  37.525 1.728 37.804 20.568 ;
     RECT  37.804 13.68 37.948 20.568 ;
     RECT  37.948 20.544 38.257 20.568 ;
     RECT  38.257 20.544 38.579 20.616 ;
     RECT  37.948 13.68 38.941 19.512 ;
     RECT  38.579 20.544 38.941 20.568 ;
     RECT  37.804 1.728 39.517 6.168 ;
     RECT  39.517 1.728 39.589 6.792 ;
     RECT  38.941 13.68 40.057 20.568 ;
     RECT  39.589 1.728 40.208 6.84 ;
     RECT  40.057 13.68 40.208 20.616 ;
     RECT  40.208 1.728 40.403 20.616 ;
     RECT  40.403 1.728 40.421 20.568 ;
     RECT  40.421 1.776 40.504 20.568 ;
     RECT  39.509 0.192 40.837 0.216 ;
     RECT  40.837 0.192 40.925 0.6 ;
     RECT  40.504 13.68 41.461 20.568 ;
     RECT  40.504 1.776 41.525 6.072 ;
     RECT  41.461 13.68 41.555 20.664 ;
     RECT  41.555 13.68 41.573 19.992 ;
     RECT  41.573 19.968 42.577 19.992 ;
     RECT  41.573 13.68 42.757 18.84 ;
     RECT  42.577 19.968 42.757 20.616 ;
     RECT  40.925 0.192 42.764 0.216 ;
     RECT  41.525 1.728 42.764 6.072 ;
     RECT  42.764 0.192 42.851 6.072 ;
     RECT  42.851 1.728 42.908 6.072 ;
     RECT  42.757 13.68 42.908 20.616 ;
     RECT  42.908 1.728 43.043 20.616 ;
     RECT  43.043 1.728 43.139 19.182 ;
     RECT  43.139 2.16 43.204 19.182 ;
     RECT  43.204 13.68 43.301 18.552 ;
     RECT  43.204 2.16 43.337 6.024 ;
     RECT  43.043 20.544 43.379 20.616 ;
     RECT  43.301 13.68 43.409 18.504 ;
     RECT  42.851 0.192 43.417 0.6 ;
     RECT  43.417 0.576 43.625 0.6 ;
     RECT  43.337 2.16 44.101 5.832 ;
     RECT  43.379 20.544 44.161 20.568 ;
     RECT  44.101 1.728 44.3 5.832 ;
     RECT  43.409 13.68 44.521 18.456 ;
     RECT  44.521 13.68 44.605 18.792 ;
     RECT  44.161 19.968 44.723 20.568 ;
     RECT  44.3 1.104 44.78 5.832 ;
     RECT  44.78 0.528 44.867 5.832 ;
     RECT  44.723 20.544 45.133 20.568 ;
     RECT  45.133 20.544 45.251 20.664 ;
     RECT  44.867 1.104 45.395 5.832 ;
     RECT  45.395 1.728 45.608 5.832 ;
     RECT  44.605 13.68 45.608 18.456 ;
     RECT  45.608 1.728 45.829 19.452 ;
     RECT  45.251 20.544 45.829 20.568 ;
     RECT  45.829 1.728 45.904 20.568 ;
     RECT  45.904 1.728 46.001 5.832 ;
     RECT  45.829 0.576 46.649 0.6 ;
     RECT  46.001 1.728 46.685 5.496 ;
     RECT  46.685 5.472 46.937 5.496 ;
     RECT  45.904 13.68 47.116 18.456 ;
     RECT  45.904 19.968 47.219 20.568 ;
     RECT  46.685 1.728 47.257 4.44 ;
     RECT  47.116 17.424 47.66 18.456 ;
     RECT  47.116 13.68 48.121 16.392 ;
     RECT  47.66 17.424 48.121 19.464 ;
     RECT  47.257 1.104 48.308 4.44 ;
     RECT  48.121 13.68 48.308 19.464 ;
     RECT  48.308 1.104 48.325 19.464 ;
     RECT  47.219 20.544 48.325 20.568 ;
     RECT  48.325 1.104 48.419 20.568 ;
     RECT  48.419 1.728 48.604 20.568 ;
     RECT  48.604 13.68 48.665 20.568 ;
     RECT  48.665 13.824 48.755 20.568 ;
     RECT  48.833 0.192 48.917 0.6 ;
     RECT  48.755 19.968 48.949 20.568 ;
     RECT  48.949 19.968 49.043 21.384 ;
     RECT  48.604 1.728 49.493 4.44 ;
     RECT  49.043 19.968 49.715 20.616 ;
     RECT  48.755 13.824 49.82 18.456 ;
     RECT  49.715 19.968 49.82 19.992 ;
     RECT  49.82 13.824 50.713 19.992 ;
     RECT  49.493 1.728 51.008 4.248 ;
     RECT  50.713 13.824 51.008 20.616 ;
     RECT  51.008 1.728 51.304 20.616 ;
     RECT  48.917 0.576 51.836 0.6 ;
     RECT  51.304 1.728 51.836 4.248 ;
     RECT  51.836 0.576 51.923 4.248 ;
     RECT  51.304 17.424 52.069 20.616 ;
     RECT  52.069 17.424 52.156 20.664 ;
     RECT  52.009 0.192 52.163 0.216 ;
     RECT  52.156 17.424 52.445 20.568 ;
     RECT  51.923 1.68 52.481 4.248 ;
     RECT  52.445 17.424 52.669 18.792 ;
     RECT  52.445 19.968 53.165 20.568 ;
     RECT  53.165 20.544 53.266 20.568 ;
     RECT  52.481 1.68 53.324 3.672 ;
     RECT  53.324 1.104 53.411 3.672 ;
     RECT  53.411 1.728 53.417 3.672 ;
     RECT  53.266 20.544 53.557 20.616 ;
     RECT  53.417 2.016 53.708 3.672 ;
     RECT  51.304 13.824 53.708 16.392 ;
     RECT  52.669 17.424 53.708 18.456 ;
     RECT  53.557 20.544 53.795 20.664 ;
     RECT  53.708 2.016 53.812 19.452 ;
     RECT  53.812 2.016 54.004 19.32 ;
     RECT  53.893 0.576 54.217 0.6 ;
     RECT  54.004 2.016 54.572 3.672 ;
     RECT  54.004 13.824 54.857 19.32 ;
     RECT  54.857 17.424 55.177 19.32 ;
     RECT  54.572 1.68 55.187 3.672 ;
     RECT  55.177 17.424 55.393 19.416 ;
     RECT  53.795 20.544 55.393 20.616 ;
     RECT  54.341 0.192 55.433 0.216 ;
     RECT  55.601 1.152 55.685 1.176 ;
     RECT  55.393 17.424 55.955 20.616 ;
     RECT  55.187 2.256 56.149 3.672 ;
     RECT  56.149 1.68 56.408 3.672 ;
     RECT  54.857 13.824 56.408 16.392 ;
     RECT  55.955 17.424 56.408 20.568 ;
     RECT  56.408 1.68 56.435 20.568 ;
     RECT  56.435 1.68 56.512 19.452 ;
     RECT  56.512 1.68 56.704 19.416 ;
     RECT  56.435 20.544 56.941 20.568 ;
     RECT  56.941 20.544 57.443 20.664 ;
     RECT  56.833 0.192 57.596 0.216 ;
     RECT  56.704 1.68 57.596 3.672 ;
     RECT  56.704 17.424 57.629 19.416 ;
     RECT  57.596 0.192 57.683 3.672 ;
     RECT  57.629 18.432 57.877 19.416 ;
     RECT  57.443 20.544 57.877 20.568 ;
     RECT  57.683 0.192 57.953 0.216 ;
     RECT  57.683 1.68 59.108 3.672 ;
     RECT  56.704 13.824 59.108 16.44 ;
     RECT  57.629 17.424 59.108 17.448 ;
     RECT  57.877 18.432 59.108 20.568 ;
     RECT  59.108 1.68 59.267 20.568 ;
     RECT  59.267 1.68 59.404 19.56 ;
     RECT  59.267 20.544 59.425 20.568 ;
     RECT  59.404 17.424 59.459 19.56 ;
     RECT  59.173 0.192 59.821 0.216 ;
     RECT  59.404 1.68 59.821 2.856 ;
     RECT  59.821 0.192 59.939 2.856 ;
     RECT  59.459 17.424 60.329 19.416 ;
     RECT  59.425 20.544 60.397 20.616 ;
     RECT  59.404 13.824 60.509 16.344 ;
     RECT  60.329 18.432 60.649 19.416 ;
     RECT  60.397 20.544 60.649 20.664 ;
     RECT  60.649 18.432 60.755 20.664 ;
     RECT  59.939 0.192 60.977 0.6 ;
     RECT  60.977 0.528 61.109 0.6 ;
     RECT  59.939 1.728 61.109 2.856 ;
     RECT  60.755 20.544 61.225 20.664 ;
     RECT  61.109 0.528 61.715 2.856 ;
     RECT  61.715 1.728 61.808 2.856 ;
     RECT  60.509 13.824 61.808 16.296 ;
     RECT  60.329 17.424 61.808 17.448 ;
     RECT  60.755 18.432 61.808 19.08 ;
     RECT  61.808 1.728 61.909 19.452 ;
     RECT  61.225 20.544 61.909 20.712 ;
     RECT  61.909 1.728 62.021 20.712 ;
     RECT  62.021 1.728 62.104 19.416 ;
     RECT  62.104 13.824 62.129 16.296 ;
     RECT  61.715 0.528 62.629 0.552 ;
     RECT  62.629 0.192 62.723 0.552 ;
     RECT  62.104 1.728 62.741 2.76 ;
     RECT  62.129 15.168 62.741 16.296 ;
     RECT  62.104 17.424 62.741 17.448 ;
     RECT  62.104 18.432 62.771 19.416 ;
     RECT  62.723 0.528 62.876 0.552 ;
     RECT  62.741 1.728 62.876 2.616 ;
     RECT  62.021 20.544 63.443 20.712 ;
     RECT  62.876 0.528 63.731 2.616 ;
     RECT  63.443 20.544 63.889 20.664 ;
     RECT  63.731 0.528 63.917 0.552 ;
     RECT  63.917 0.192 64.001 0.552 ;
     RECT  63.731 1.68 64.508 2.616 ;
     RECT  62.129 13.824 64.508 13.848 ;
     RECT  62.741 15.264 64.508 16.296 ;
     RECT  62.771 18.432 64.508 18.456 ;
     RECT  63.889 19.968 64.508 20.664 ;
     RECT  64.508 1.68 64.804 20.664 ;
     RECT  64.804 19.968 64.931 20.664 ;
     RECT  64.804 18.432 65.009 18.792 ;
     RECT  64.001 0.528 65.141 0.552 ;
     RECT  65.009 18.768 65.297 18.792 ;
     RECT  65.141 0.192 65.653 0.552 ;
     RECT  64.804 1.68 65.653 2.616 ;
     RECT  65.653 0.192 65.747 2.616 ;
     RECT  64.931 20.544 65.939 20.664 ;
     RECT  65.747 0.192 66.017 0.6 ;
     RECT  65.939 20.544 66.301 20.568 ;
     RECT  66.017 0.528 66.755 0.6 ;
     RECT  66.301 19.968 66.946 20.568 ;
     RECT  66.755 0.528 66.995 0.552 ;
     RECT  66.946 19.968 67.057 20.616 ;
     RECT  65.747 1.728 67.129 2.616 ;
     RECT  67.129 1.68 67.208 2.616 ;
     RECT  64.804 13.824 67.208 13.848 ;
     RECT  64.804 15.264 67.208 16.296 ;
     RECT  67.057 19.968 67.208 20.664 ;
     RECT  67.208 1.68 67.283 20.664 ;
     RECT  67.283 1.68 67.504 20.616 ;
     RECT  67.504 19.392 67.763 20.616 ;
     RECT  67.504 1.68 67.817 2.616 ;
     RECT  67.763 20.544 68.099 20.616 ;
     RECT  68.165 0.192 68.396 0.216 ;
     RECT  67.817 1.68 68.396 1.752 ;
     RECT  67.763 19.392 68.749 19.416 ;
     RECT  68.099 20.544 68.749 20.568 ;
     RECT  68.749 19.392 68.771 20.568 ;
     RECT  68.396 0.192 69.041 1.752 ;
     RECT  68.771 19.968 69.253 20.568 ;
     RECT  69.109 18.24 69.613 18.264 ;
     RECT  69.041 1.104 69.908 1.752 ;
     RECT  67.504 13.824 69.908 13.848 ;
     RECT  67.504 15.264 69.908 16.296 ;
     RECT  69.613 18.24 69.908 18.792 ;
     RECT  69.253 19.968 69.908 20.616 ;
     RECT  69.908 1.104 70.085 20.616 ;
     RECT  70.085 1.728 70.115 20.616 ;
     RECT  70.115 1.728 70.204 19.182 ;
     RECT  70.204 13.824 70.265 13.848 ;
     RECT  70.115 20.544 70.333 20.616 ;
     RECT  70.213 0.528 70.337 0.552 ;
     RECT  70.204 18.24 70.595 18.264 ;
     RECT  70.204 15.264 70.625 16.296 ;
     RECT  70.333 20.544 70.787 20.712 ;
     RECT  70.204 1.728 71.267 2.28 ;
     RECT  70.787 20.544 71.411 20.664 ;
     RECT  70.625 15.264 71.597 15.288 ;
     RECT  71.521 18.768 71.605 18.792 ;
     RECT  71.411 20.544 71.773 20.568 ;
     RECT  71.449 0.192 71.993 0.216 ;
     RECT  71.267 1.728 72.197 1.752 ;
     RECT  71.773 19.968 72.418 20.568 ;
     RECT  72.197 1.152 72.608 1.752 ;
     RECT  70.625 16.272 72.608 16.296 ;
     RECT  72.418 19.968 72.608 20.616 ;
     RECT  72.608 1.152 72.611 20.616 ;
     RECT  72.611 1.152 72.904 20.568 ;
     RECT  72.904 19.968 72.947 20.568 ;
     RECT  72.904 1.152 72.995 2.04 ;
     RECT  73.196 1.104 73.283 1.128 ;
     RECT  72.947 19.968 73.283 19.992 ;
     RECT  75.308 2.148 75.412 19.452 ;
     RECT  75.412 2.418 75.604 19.182 ;
    LAYER M5 ;
     RECT  4.536 0.144 4.752 0.192 ;
     RECT  4.776 0.144 4.992 0.192 ;
     RECT  5.016 0.144 5.28 0.192 ;
     RECT  5.304 0.144 5.52 0.192 ;
     RECT  5.544 0.144 5.76 0.192 ;
     RECT  5.784 0.144 6 0.192 ;
     RECT  6.024 0.144 6.288 0.192 ;
     RECT  6.312 0.144 6.528 0.192 ;
     RECT  6.552 0.144 6.768 0.192 ;
     RECT  6.792 0.144 7.008 0.192 ;
     RECT  7.032 0.144 7.248 0.192 ;
     RECT  7.272 0.144 7.536 0.192 ;
     RECT  7.56 0.144 7.776 0.192 ;
     RECT  7.8 0.144 8.016 0.192 ;
     RECT  8.04 0.144 8.256 0.192 ;
     RECT  8.28 0.144 8.544 0.192 ;
     RECT  8.568 0.144 8.784 0.192 ;
     RECT  8.808 0.144 9.024 0.192 ;
     RECT  9.048 0.144 9.264 0.192 ;
     RECT  9.288 0.144 9.552 0.192 ;
     RECT  9.576 0.144 9.792 0.192 ;
     RECT  9.816 0.144 10.032 0.192 ;
     RECT  10.056 0.144 10.272 0.192 ;
     RECT  10.296 0.144 10.56 0.192 ;
     RECT  10.584 0.144 10.8 0.192 ;
     RECT  10.824 0.144 11.04 0.192 ;
     RECT  11.064 0.144 11.28 0.192 ;
     RECT  11.304 0.144 11.52 0.192 ;
     RECT  11.544 0.144 11.808 0.192 ;
     RECT  11.832 0.144 12.048 0.192 ;
     RECT  12.072 0.144 12.288 0.192 ;
     RECT  12.312 0.144 12.528 0.192 ;
     RECT  12.552 0.144 12.816 0.192 ;
     RECT  12.84 0.144 13.056 0.192 ;
     RECT  13.08 0.144 13.296 0.192 ;
     RECT  13.32 0.144 13.536 0.192 ;
     RECT  13.56 0.144 13.824 0.192 ;
     RECT  13.848 0.144 14.064 0.192 ;
     RECT  14.088 0.144 14.304 0.192 ;
     RECT  14.328 0.144 14.544 0.192 ;
     RECT  14.568 0.144 14.784 0.192 ;
     RECT  14.808 0.144 15.072 0.192 ;
     RECT  15.096 0.144 15.312 0.192 ;
     RECT  15.336 0.144 15.552 0.192 ;
     RECT  15.576 0.144 15.792 0.192 ;
     RECT  15.816 0.144 16.08 0.192 ;
     RECT  16.104 0.144 16.32 0.192 ;
     RECT  16.344 0.144 16.56 0.192 ;
     RECT  16.584 0.144 16.8 0.192 ;
     RECT  16.824 0.144 17.088 0.192 ;
     RECT  17.112 0.144 17.328 0.192 ;
     RECT  17.352 0.144 17.568 0.192 ;
     RECT  17.592 0.144 17.808 0.192 ;
     RECT  17.832 0.144 18.048 0.192 ;
     RECT  18.072 0.144 18.336 0.192 ;
     RECT  18.36 0.144 18.576 0.192 ;
     RECT  18.6 0.144 18.816 0.192 ;
     RECT  18.84 0.144 19.056 0.192 ;
     RECT  19.08 0.144 19.344 0.192 ;
     RECT  19.368 0.144 19.584 0.192 ;
     RECT  19.608 0.144 19.824 0.192 ;
     RECT  19.848 0.144 20.064 0.192 ;
     RECT  20.088 0.144 20.352 0.192 ;
     RECT  20.376 0.144 20.592 0.192 ;
     RECT  20.616 0.144 20.832 0.192 ;
     RECT  20.856 0.144 21.072 0.192 ;
     RECT  21.096 0.144 21.36 0.192 ;
     RECT  21.384 0.144 21.6 0.192 ;
     RECT  21.624 0.144 21.84 0.192 ;
     RECT  21.864 0.144 22.08 0.192 ;
     RECT  22.104 0.144 22.32 0.192 ;
     RECT  22.344 0.144 22.608 0.192 ;
     RECT  22.632 0.144 22.848 0.192 ;
     RECT  22.872 0.144 23.088 0.192 ;
     RECT  23.112 0.144 23.328 0.192 ;
     RECT  23.352 0.144 23.616 0.192 ;
     RECT  23.64 0.144 23.856 0.192 ;
     RECT  23.88 0.144 24.096 0.192 ;
     RECT  24.12 0.144 24.336 0.192 ;
     RECT  24.36 0.144 24.624 0.192 ;
     RECT  24.648 0.144 24.864 0.192 ;
     RECT  24.888 0.144 25.104 0.192 ;
     RECT  25.128 0.144 25.344 0.192 ;
     RECT  25.368 0.144 25.584 0.192 ;
     RECT  25.608 0.144 25.872 0.192 ;
     RECT  25.896 0.144 26.112 0.192 ;
     RECT  26.136 0.144 26.352 0.192 ;
     RECT  26.376 0.144 26.592 0.192 ;
     RECT  26.616 0.144 26.88 0.192 ;
     RECT  26.904 0.144 27.12 0.192 ;
     RECT  27.144 0.144 27.36 0.192 ;
     RECT  27.384 0.144 27.6 0.192 ;
     RECT  27.624 0.144 27.888 0.192 ;
     RECT  27.912 0.144 28.128 0.192 ;
     RECT  28.152 0.144 28.368 0.192 ;
     RECT  28.392 0.144 28.608 0.192 ;
     RECT  28.632 0.144 28.896 0.192 ;
     RECT  28.92 0.144 29.136 0.192 ;
     RECT  29.16 0.144 29.376 0.192 ;
     RECT  29.4 0.144 29.616 0.192 ;
     RECT  29.64 0.144 29.856 0.192 ;
     RECT  29.88 0.144 30.144 0.192 ;
     RECT  30.168 0.144 30.384 0.192 ;
     RECT  30.408 0.144 30.624 0.192 ;
     RECT  30.648 0.144 30.864 0.192 ;
     RECT  30.888 0.144 31.152 0.192 ;
     RECT  31.176 0.144 31.392 0.192 ;
     RECT  31.416 0.144 31.632 0.192 ;
     RECT  31.656 0.144 31.872 0.192 ;
     RECT  31.896 0.144 32.16 0.192 ;
     RECT  32.184 0.144 32.4 0.192 ;
     RECT  32.424 0.144 32.64 0.192 ;
     RECT  32.664 0.144 32.88 0.192 ;
     RECT  32.904 0.144 33.12 0.192 ;
     RECT  33.144 0.144 33.408 0.192 ;
     RECT  33.432 0.144 33.648 0.192 ;
     RECT  33.672 0.144 33.888 0.192 ;
     RECT  33.912 0.144 34.128 0.192 ;
     RECT  34.152 0.144 34.416 0.192 ;
     RECT  34.44 0.144 34.656 0.192 ;
     RECT  34.68 0.144 34.896 0.192 ;
     RECT  34.92 0.144 35.136 0.192 ;
     RECT  35.16 0.144 35.424 0.192 ;
     RECT  35.448 0.144 35.664 0.192 ;
     RECT  35.688 0.144 35.904 0.192 ;
     RECT  35.928 0.144 36.144 0.192 ;
     RECT  36.168 0.144 36.384 0.192 ;
     RECT  36.408 0.144 36.672 0.192 ;
     RECT  36.696 0.144 36.912 0.192 ;
     RECT  36.936 0.144 37.152 0.192 ;
     RECT  37.176 0.144 37.392 0.192 ;
     RECT  37.416 0.144 37.68 0.192 ;
     RECT  37.704 0.144 37.92 0.192 ;
     RECT  37.944 0.144 38.16 0.192 ;
     RECT  38.184 0.144 38.4 0.192 ;
     RECT  38.424 0.144 38.688 0.192 ;
     RECT  38.712 0.144 39.072 0.192 ;
     RECT  39.096 0.144 39.312 0.192 ;
     RECT  39.336 0.144 39.552 0.192 ;
     RECT  39.576 0.144 39.84 0.192 ;
     RECT  39.864 0.144 40.08 0.192 ;
     RECT  40.104 0.144 40.32 0.192 ;
     RECT  40.344 0.144 40.56 0.192 ;
     RECT  40.584 0.144 40.848 0.192 ;
     RECT  40.872 0.144 41.088 0.192 ;
     RECT  41.112 0.144 41.328 0.192 ;
     RECT  41.352 0.144 41.568 0.192 ;
     RECT  41.592 0.144 41.808 0.192 ;
     RECT  41.832 0.144 42.096 0.192 ;
     RECT  42.12 0.144 42.336 0.192 ;
     RECT  42.36 0.144 42.576 0.192 ;
     RECT  42.6 0.144 42.816 0.192 ;
     RECT  42.84 0.144 43.104 0.192 ;
     RECT  43.128 0.144 43.344 0.192 ;
     RECT  43.368 0.144 43.584 0.192 ;
     RECT  43.608 0.144 43.824 0.192 ;
     RECT  43.848 0.144 44.112 0.192 ;
     RECT  44.136 0.144 44.352 0.192 ;
     RECT  44.376 0.144 44.592 0.192 ;
     RECT  44.616 0.144 44.832 0.192 ;
     RECT  44.856 0.144 45.12 0.192 ;
     RECT  45.144 0.144 45.36 0.192 ;
     RECT  45.384 0.144 45.6 0.192 ;
     RECT  45.624 0.144 45.84 0.192 ;
     RECT  45.864 0.144 46.08 0.192 ;
     RECT  46.104 0.144 46.368 0.192 ;
     RECT  46.392 0.144 46.608 0.192 ;
     RECT  46.632 0.144 46.848 0.192 ;
     RECT  46.872 0.144 47.088 0.192 ;
     RECT  47.112 0.144 47.376 0.192 ;
     RECT  47.4 0.144 47.616 0.192 ;
     RECT  47.64 0.144 47.856 0.192 ;
     RECT  47.88 0.144 48.096 0.192 ;
     RECT  48.12 0.144 48.384 0.192 ;
     RECT  48.408 0.144 48.624 0.192 ;
     RECT  48.648 0.144 48.864 0.192 ;
     RECT  48.888 0.144 49.104 0.192 ;
     RECT  49.128 0.144 49.344 0.192 ;
     RECT  49.368 0.144 49.632 0.192 ;
     RECT  49.656 0.144 49.872 0.192 ;
     RECT  49.896 0.144 50.112 0.192 ;
     RECT  50.136 0.144 50.352 0.192 ;
     RECT  50.376 0.144 50.64 0.192 ;
     RECT  50.664 0.144 50.88 0.192 ;
     RECT  50.904 0.144 51.12 0.192 ;
     RECT  51.144 0.144 51.36 0.192 ;
     RECT  51.384 0.144 51.648 0.192 ;
     RECT  51.672 0.144 51.888 0.192 ;
     RECT  51.912 0.144 52.128 0.192 ;
     RECT  52.152 0.144 52.368 0.192 ;
     RECT  52.392 0.144 52.608 0.192 ;
     RECT  52.632 0.144 52.896 0.192 ;
     RECT  52.92 0.144 53.136 0.192 ;
     RECT  53.16 0.144 53.376 0.192 ;
     RECT  53.4 0.144 53.616 0.192 ;
     RECT  53.64 0.144 53.904 0.192 ;
     RECT  53.928 0.144 54.144 0.192 ;
     RECT  54.168 0.144 54.384 0.192 ;
     RECT  54.408 0.144 54.624 0.192 ;
     RECT  54.648 0.144 54.912 0.192 ;
     RECT  54.936 0.144 55.152 0.192 ;
     RECT  55.176 0.144 55.392 0.192 ;
     RECT  55.416 0.144 55.632 0.192 ;
     RECT  55.656 0.144 55.92 0.192 ;
     RECT  55.944 0.144 56.16 0.192 ;
     RECT  56.184 0.144 56.4 0.192 ;
     RECT  56.424 0.144 56.64 0.192 ;
     RECT  56.664 0.144 56.88 0.192 ;
     RECT  56.904 0.144 57.168 0.192 ;
     RECT  57.192 0.144 57.408 0.192 ;
     RECT  57.432 0.144 57.648 0.192 ;
     RECT  57.672 0.144 57.888 0.192 ;
     RECT  57.912 0.144 58.176 0.192 ;
     RECT  58.2 0.144 58.416 0.192 ;
     RECT  58.44 0.144 58.656 0.192 ;
     RECT  58.68 0.144 58.896 0.192 ;
     RECT  58.92 0.144 59.184 0.192 ;
     RECT  59.208 0.144 59.424 0.192 ;
     RECT  59.448 0.144 59.664 0.192 ;
     RECT  59.688 0.144 59.904 0.192 ;
     RECT  59.928 0.144 60.144 0.192 ;
     RECT  60.168 0.144 60.432 0.192 ;
     RECT  60.456 0.144 60.672 0.192 ;
     RECT  60.696 0.144 60.912 0.192 ;
     RECT  60.936 0.144 61.152 0.192 ;
     RECT  61.176 0.144 61.44 0.192 ;
     RECT  61.464 0.144 61.68 0.192 ;
     RECT  61.704 0.144 61.92 0.192 ;
     RECT  61.944 0.144 62.16 0.192 ;
     RECT  62.184 0.144 62.448 0.192 ;
     RECT  62.472 0.144 62.688 0.192 ;
     RECT  62.712 0.144 62.928 0.192 ;
     RECT  62.952 0.144 63.168 0.192 ;
     RECT  63.192 0.144 63.456 0.192 ;
     RECT  63.48 0.144 63.696 0.192 ;
     RECT  63.72 0.144 63.936 0.192 ;
     RECT  63.96 0.144 64.176 0.192 ;
     RECT  64.2 0.144 64.416 0.192 ;
     RECT  64.44 0.144 64.704 0.192 ;
     RECT  64.728 0.144 64.944 0.192 ;
     RECT  64.968 0.144 65.184 0.192 ;
     RECT  65.208 0.144 65.424 0.192 ;
     RECT  65.448 0.144 65.712 0.192 ;
     RECT  65.736 0.144 65.952 0.192 ;
     RECT  65.976 0.144 66.192 0.192 ;
     RECT  66.216 0.144 66.432 0.192 ;
     RECT  66.456 0.144 66.72 0.192 ;
     RECT  66.744 0.144 66.96 0.192 ;
     RECT  66.984 0.144 67.2 0.192 ;
     RECT  67.224 0.144 67.44 0.192 ;
     RECT  67.464 0.144 67.68 0.192 ;
     RECT  67.704 0.144 67.968 0.192 ;
     RECT  67.992 0.144 68.208 0.192 ;
     RECT  68.232 0.144 68.448 0.192 ;
     RECT  68.472 0.144 68.688 0.192 ;
     RECT  68.712 0.144 68.976 0.192 ;
     RECT  69 0.144 69.216 0.192 ;
     RECT  69.24 0.144 69.456 0.192 ;
     RECT  69.48 0.144 69.696 0.192 ;
     RECT  69.72 0.144 69.984 0.192 ;
     RECT  70.008 0.144 70.224 0.192 ;
     RECT  70.248 0.144 70.464 0.192 ;
     RECT  70.488 0.144 70.704 0.192 ;
     RECT  70.728 0.144 70.944 0.192 ;
     RECT  70.968 0.144 71.232 0.192 ;
     RECT  71.256 0.144 71.472 0.192 ;
     RECT  71.496 0.144 71.712 0.192 ;
     RECT  71.736 0.144 71.952 0.192 ;
     RECT  71.976 0.144 72.24 0.192 ;
     RECT  72.264 0.144 72.48 0.192 ;
     RECT  72.504 0.144 72.72 0.192 ;
     RECT  72.744 0.144 72.96 0.192 ;
     RECT  72.984 0.144 73.248 0.192 ;
     RECT  4.512 0.192 73.272 0.611 ;
     RECT  54.624 0.611 73.272 1.139 ;
     RECT  54.624 1.139 61.464 1.187 ;
     RECT  54.624 1.187 60.456 1.715 ;
     RECT  63.456 1.139 72.984 1.715 ;
     RECT  4.512 0.611 53.64 1.763 ;
     RECT  55.152 1.715 59.448 1.763 ;
     RECT  60.432 1.715 60.456 1.763 ;
     RECT  61.44 1.187 61.464 1.763 ;
     RECT  62.448 1.139 62.472 1.763 ;
     RECT  63.456 1.715 67.704 1.763 ;
     RECT  68.688 1.715 72.984 1.763 ;
     RECT  14.544 1.763 14.568 1.811 ;
     RECT  24 1.763 25.128 1.811 ;
     RECT  37.5 1.763 41.112 1.811 ;
     RECT  33.408 1.763 33.432 1.859 ;
     RECT  37.5 1.811 40.512 1.859 ;
     RECT  21.12 1.763 21.624 2.051 ;
     RECT  72.6 1.763 72.984 2.051 ;
     RECT  52.896 1.763 53.64 2.137 ;
     RECT  2.4 2.137 2.52 2.151 ;
     RECT  75.3 2.137 75.42 2.151 ;
     RECT  42.576 1.763 43.848 2.195 ;
     RECT  45.6 1.763 48.612 2.195 ;
     RECT  49.872 1.763 49.896 2.195 ;
     RECT  52.896 2.137 54.012 2.195 ;
     RECT  5.1 1.763 6.024 2.291 ;
     RECT  7.248 1.763 8.112 2.291 ;
     RECT  55.344 1.763 56.712 2.291 ;
     RECT  66.192 1.763 66.216 2.291 ;
     RECT  69.9 1.763 71.256 2.291 ;
     RECT  10.5 1.763 10.812 2.773 ;
     RECT  5.1 2.291 5.412 2.821 ;
     RECT  6.528 2.725 6.552 2.867 ;
     RECT  31.968 1.763 32.412 2.869 ;
     RECT  39.312 1.859 40.512 2.869 ;
     RECT  15.9 1.763 16.212 3.061 ;
     RECT  29.4 1.763 29.712 3.061 ;
     RECT  39.12 2.869 40.512 3.107 ;
     RECT  24 1.811 24.312 3.205 ;
     RECT  25.68 2.821 25.704 3.205 ;
     RECT  39.216 3.107 40.512 3.299 ;
     RECT  13.2 1.763 13.512 3.301 ;
     RECT  18.6 1.763 18.912 3.349 ;
     RECT  24 3.205 25.704 3.397 ;
     RECT  31.968 2.869 32.52 3.397 ;
     RECT  29.28 3.061 29.712 3.541 ;
     RECT  31.968 3.397 33.048 3.541 ;
     RECT  23.568 3.397 25.704 3.635 ;
     RECT  31.968 3.541 33.144 3.637 ;
     RECT  39.552 3.299 40.512 3.683 ;
     RECT  10.272 2.773 10.812 3.685 ;
     RECT  13.104 3.301 13.512 3.731 ;
     RECT  37.5 1.859 37.812 3.733 ;
     RECT  39.648 3.683 40.512 3.827 ;
     RECT  13.2 3.731 13.512 3.925 ;
     RECT  19.968 3.397 19.992 3.925 ;
     RECT  21.12 2.051 21.612 3.925 ;
     RECT  23.568 3.635 24.552 3.925 ;
     RECT  29.184 3.541 29.712 3.973 ;
     RECT  4.608 2.821 5.412 4.019 ;
     RECT  17.616 3.349 18.912 4.069 ;
     RECT  19.968 3.925 21.612 4.115 ;
     RECT  23.424 3.925 24.552 4.115 ;
     RECT  34.8 1.763 35.112 4.213 ;
     RECT  36.096 3.925 36.12 4.213 ;
     RECT  30.912 3.973 30.936 4.357 ;
     RECT  31.968 3.637 33.24 4.357 ;
     RECT  30.912 4.357 33.24 4.499 ;
     RECT  34.8 4.213 36.12 4.501 ;
     RECT  37.5 3.733 37.944 4.501 ;
     RECT  30.912 4.499 30.936 4.547 ;
     RECT  34.8 4.501 37.944 4.547 ;
     RECT  25.68 3.635 25.704 4.643 ;
     RECT  26.7 1.763 27.012 4.693 ;
     RECT  32.1 4.499 33.24 4.693 ;
     RECT  36.096 4.547 37.944 4.739 ;
     RECT  10.272 3.685 10.92 4.787 ;
     RECT  26.208 4.693 27.012 4.789 ;
     RECT  28.8 3.973 29.712 4.789 ;
     RECT  24 4.115 24.552 4.885 ;
     RECT  9.216 4.165 9.24 4.979 ;
     RECT  37.392 4.739 37.944 5.027 ;
     RECT  36.096 4.739 36.12 5.123 ;
     RECT  15.36 3.061 16.212 5.171 ;
     RECT  17.52 4.069 18.912 5.171 ;
     RECT  22.8 4.981 22.824 5.171 ;
     RECT  7.8 2.291 8.112 5.173 ;
     RECT  17.616 5.171 18.912 5.173 ;
     RECT  20.16 4.115 21.612 5.173 ;
     RECT  30.768 5.029 30.792 5.267 ;
     RECT  26.208 4.789 29.712 5.315 ;
     RECT  37.392 5.027 37.812 5.411 ;
     RECT  17.616 5.173 21.612 5.603 ;
     RECT  10.272 4.787 10.812 5.651 ;
     RECT  7.056 5.173 8.232 5.747 ;
     RECT  17.616 5.603 18.912 5.747 ;
     RECT  20.16 5.603 21.612 5.747 ;
     RECT  32.1 4.693 33.336 5.747 ;
     RECT  13.2 3.925 13.608 5.795 ;
     RECT  24 4.885 25.128 5.845 ;
     RECT  13.2 5.795 13.512 5.893 ;
     RECT  20.688 5.747 21.612 6.035 ;
     RECT  24 5.845 25.32 6.083 ;
     RECT  26.7 5.315 29.712 6.083 ;
     RECT  12.768 5.893 13.512 6.131 ;
     RECT  24 6.083 25.128 6.131 ;
     RECT  28.32 6.083 29.712 6.131 ;
     RECT  32.1 5.747 32.664 6.131 ;
     RECT  7.8 5.747 8.232 6.323 ;
     RECT  30.768 14.101 30.792 14.243 ;
     RECT  24 6.131 24.312 14.389 ;
     RECT  29.28 6.131 29.712 14.389 ;
     RECT  24 14.389 25.128 14.485 ;
     RECT  23.808 14.485 25.128 14.531 ;
     RECT  28.608 14.389 29.712 14.531 ;
     RECT  18.6 5.747 18.912 14.677 ;
     RECT  6.672 15.061 6.696 15.253 ;
     RECT  7.8 6.323 8.112 15.253 ;
     RECT  13.2 6.131 13.512 15.301 ;
     RECT  15.9 5.171 16.212 15.829 ;
     RECT  13.008 15.301 13.512 15.925 ;
     RECT  29.28 14.531 29.712 16.019 ;
     RECT  37.5 5.411 37.812 16.021 ;
     RECT  39.072 15.925 39.096 16.115 ;
     RECT  55.344 2.291 55.368 16.213 ;
     RECT  56.4 2.291 56.712 16.213 ;
     RECT  37.5 16.021 38.04 16.403 ;
     RECT  55.344 16.213 56.712 16.403 ;
     RECT  26.7 6.083 27.012 16.501 ;
     RECT  51 1.763 51.312 16.501 ;
     RECT  22.8 16.789 22.824 16.931 ;
     RECT  26.592 16.501 27.012 17.029 ;
     RECT  45.6 2.195 45.912 17.029 ;
     RECT  40.2 3.827 40.512 17.077 ;
     RECT  45.6 17.029 46.392 17.077 ;
     RECT  21.12 6.035 21.612 17.125 ;
     RECT  44.88 17.077 46.392 17.125 ;
     RECT  20.64 17.125 21.612 17.221 ;
     RECT  23.808 14.531 24.312 17.605 ;
     RECT  25.968 17.029 27.012 17.605 ;
     RECT  53.7 2.195 54.012 17.605 ;
     RECT  32.1 6.131 32.412 17.653 ;
     RECT  37.5 16.403 37.944 17.653 ;
     RECT  41.712 17.605 41.736 17.653 ;
     RECT  42.9 2.195 43.212 17.653 ;
     RECT  44.88 17.125 47.064 17.653 ;
     RECT  48.3 2.195 48.612 17.653 ;
     RECT  55.344 16.403 55.368 17.653 ;
     RECT  56.4 16.403 56.712 17.653 ;
     RECT  50.736 16.501 51.312 18.181 ;
     RECT  53.7 17.605 54.264 18.181 ;
     RECT  6.672 15.253 8.112 18.229 ;
     RECT  17.808 14.677 18.912 18.229 ;
     RECT  25.968 17.605 27.144 18.229 ;
     RECT  28.224 17.221 28.248 18.229 ;
     RECT  29.4 16.019 29.712 18.229 ;
     RECT  34.8 4.547 35.112 18.229 ;
     RECT  36.864 17.653 37.944 18.229 ;
     RECT  41.712 17.653 43.212 18.229 ;
     RECT  69.9 2.291 70.212 18.229 ;
     RECT  31.872 17.653 33.576 18.565 ;
     RECT  12.144 15.925 13.704 18.757 ;
     RECT  15.648 15.829 16.212 18.757 ;
     RECT  41.712 18.229 43.896 18.757 ;
     RECT  44.88 17.653 48.612 18.757 ;
     RECT  52.896 18.181 54.264 18.757 ;
     RECT  59.1 1.763 59.412 18.757 ;
     RECT  64.5 1.763 64.812 18.757 ;
     RECT  5.1 4.019 5.412 18.805 ;
     RECT  6.672 18.229 8.856 18.805 ;
     RECT  10.5 5.651 10.812 18.805 ;
     RECT  11.856 18.757 13.704 18.805 ;
     RECT  15.168 18.757 16.212 18.805 ;
     RECT  55.344 17.653 56.712 18.805 ;
     RECT  57.936 18.757 57.96 18.805 ;
     RECT  59.1 18.757 59.928 18.805 ;
     RECT  61.8 2.137 62.112 18.805 ;
     RECT  11.856 18.805 16.212 18.901 ;
     RECT  17.808 18.229 19.032 18.901 ;
     RECT  20.64 17.221 22.488 18.901 ;
     RECT  23.664 17.605 24.408 18.901 ;
     RECT  25.968 18.229 30.216 18.901 ;
     RECT  31.2 18.565 33.576 18.901 ;
     RECT  11.856 18.901 22.68 18.949 ;
     RECT  23.664 18.901 24.84 18.949 ;
     RECT  34.8 18.229 38.232 19.141 ;
     RECT  39.216 17.077 40.512 19.141 ;
     RECT  5.1 18.805 10.812 19.189 ;
     RECT  11.856 18.949 24.984 19.237 ;
     RECT  25.968 18.901 33.576 19.237 ;
     RECT  52.608 18.757 54.264 19.285 ;
     RECT  55.344 18.805 59.928 19.285 ;
     RECT  50.736 18.181 51.432 19.333 ;
     RECT  52.608 19.285 59.928 19.333 ;
     RECT  11.856 19.237 33.576 19.381 ;
     RECT  34.8 19.141 40.512 19.381 ;
     RECT  50.736 19.333 59.928 19.381 ;
     RECT  60.912 18.805 62.112 19.381 ;
     RECT  67.2 1.763 67.512 19.381 ;
     RECT  69.216 18.229 70.584 19.381 ;
     RECT  2.4 2.151 2.712 19.449 ;
     RECT  75.3 2.151 75.612 19.449 ;
     RECT  2.4 19.449 2.52 19.463 ;
     RECT  49.872 19.381 62.76 19.463 ;
     RECT  75.3 19.449 75.42 19.463 ;
     RECT  4.512 19.189 10.812 19.525 ;
     RECT  4.512 19.525 10.872 19.957 ;
     RECT  11.856 19.381 40.512 19.957 ;
     RECT  41.712 18.757 48.744 19.957 ;
     RECT  49.872 19.463 53.112 19.957 ;
     RECT  64.5 18.757 65.112 19.957 ;
     RECT  67.2 19.381 70.584 19.957 ;
     RECT  71.568 18.757 71.592 19.957 ;
     RECT  72.6 2.051 72.912 19.957 ;
     RECT  4.512 19.957 53.112 20.533 ;
     RECT  54.096 19.463 60.936 20.533 ;
     RECT  61.92 19.463 62.76 20.533 ;
     RECT  64.08 19.957 65.112 20.533 ;
     RECT  66.384 19.957 70.584 20.533 ;
     RECT  71.568 19.957 73.272 20.533 ;
     RECT  4.512 20.533 73.272 21.408 ;
     RECT  4.536 21.408 4.656 21.456 ;
     RECT  4.68 21.408 4.848 21.456 ;
     RECT  4.872 21.408 4.992 21.456 ;
     RECT  5.016 21.408 5.184 21.456 ;
     RECT  5.208 21.408 5.328 21.456 ;
     RECT  5.352 21.408 5.52 21.456 ;
     RECT  5.544 21.408 5.664 21.456 ;
     RECT  5.688 21.408 5.856 21.456 ;
     RECT  5.88 21.408 6 21.456 ;
     RECT  6.024 21.408 6.192 21.456 ;
     RECT  6.216 21.408 6.336 21.456 ;
     RECT  6.36 21.408 6.528 21.456 ;
     RECT  6.552 21.408 6.672 21.456 ;
     RECT  6.696 21.408 6.816 21.456 ;
     RECT  6.84 21.408 7.008 21.456 ;
     RECT  7.032 21.408 7.152 21.456 ;
     RECT  7.176 21.408 7.344 21.456 ;
     RECT  7.368 21.408 7.488 21.456 ;
     RECT  7.512 21.408 7.68 21.456 ;
     RECT  7.704 21.408 7.824 21.456 ;
     RECT  7.848 21.408 8.016 21.456 ;
     RECT  8.04 21.408 8.16 21.456 ;
     RECT  8.184 21.408 8.352 21.456 ;
     RECT  8.376 21.408 8.496 21.456 ;
     RECT  8.52 21.408 8.688 21.456 ;
     RECT  8.712 21.408 8.832 21.456 ;
     RECT  8.856 21.408 9.024 21.456 ;
     RECT  9.048 21.408 9.168 21.456 ;
     RECT  9.192 21.408 9.312 21.456 ;
     RECT  9.336 21.408 9.504 21.456 ;
     RECT  9.528 21.408 9.648 21.456 ;
     RECT  9.672 21.408 9.84 21.456 ;
     RECT  9.864 21.408 9.984 21.456 ;
     RECT  10.008 21.408 10.176 21.456 ;
     RECT  10.2 21.408 10.32 21.456 ;
     RECT  10.344 21.408 10.512 21.456 ;
     RECT  10.536 21.408 10.656 21.456 ;
     RECT  10.68 21.408 10.848 21.456 ;
     RECT  10.872 21.408 10.992 21.456 ;
     RECT  11.016 21.408 11.184 21.456 ;
     RECT  11.208 21.408 11.328 21.456 ;
     RECT  11.352 21.408 11.52 21.456 ;
     RECT  11.544 21.408 11.664 21.456 ;
     RECT  11.688 21.408 11.856 21.456 ;
     RECT  11.88 21.408 12 21.456 ;
     RECT  12.024 21.408 12.144 21.456 ;
     RECT  12.168 21.408 12.336 21.456 ;
     RECT  12.36 21.408 12.48 21.456 ;
     RECT  12.504 21.408 12.672 21.456 ;
     RECT  12.696 21.408 12.816 21.456 ;
     RECT  12.84 21.408 13.008 21.456 ;
     RECT  13.032 21.408 13.152 21.456 ;
     RECT  13.176 21.408 13.344 21.456 ;
     RECT  13.368 21.408 13.488 21.456 ;
     RECT  13.512 21.408 13.68 21.456 ;
     RECT  13.704 21.408 13.824 21.456 ;
     RECT  13.848 21.408 14.016 21.456 ;
     RECT  14.04 21.408 14.16 21.456 ;
     RECT  14.184 21.408 14.352 21.456 ;
     RECT  14.376 21.408 14.496 21.456 ;
     RECT  14.52 21.408 14.64 21.456 ;
     RECT  14.664 21.408 14.832 21.456 ;
     RECT  14.856 21.408 14.976 21.456 ;
     RECT  15 21.408 15.168 21.456 ;
     RECT  15.192 21.408 15.312 21.456 ;
     RECT  15.336 21.408 15.504 21.456 ;
     RECT  15.528 21.408 15.648 21.456 ;
     RECT  15.672 21.408 15.84 21.456 ;
     RECT  15.864 21.408 15.984 21.456 ;
     RECT  16.008 21.408 16.176 21.456 ;
     RECT  16.2 21.408 16.32 21.456 ;
     RECT  16.344 21.408 16.512 21.456 ;
     RECT  16.536 21.408 16.656 21.456 ;
     RECT  16.68 21.408 16.848 21.456 ;
     RECT  16.872 21.408 16.992 21.456 ;
     RECT  17.016 21.408 17.136 21.456 ;
     RECT  17.16 21.408 17.328 21.456 ;
     RECT  17.352 21.408 17.472 21.456 ;
     RECT  17.496 21.408 17.664 21.456 ;
     RECT  17.688 21.408 17.808 21.456 ;
     RECT  17.832 21.408 18 21.456 ;
     RECT  18.024 21.408 18.144 21.456 ;
     RECT  18.168 21.408 18.336 21.456 ;
     RECT  18.36 21.408 18.48 21.456 ;
     RECT  18.504 21.408 18.672 21.456 ;
     RECT  18.696 21.408 18.816 21.456 ;
     RECT  18.84 21.408 19.008 21.456 ;
     RECT  19.032 21.408 19.152 21.456 ;
     RECT  19.176 21.408 19.344 21.456 ;
     RECT  19.368 21.408 19.488 21.456 ;
     RECT  19.512 21.408 19.68 21.456 ;
     RECT  19.704 21.408 19.824 21.456 ;
     RECT  19.848 21.408 19.968 21.456 ;
     RECT  19.992 21.408 20.16 21.456 ;
     RECT  20.184 21.408 20.304 21.456 ;
     RECT  20.328 21.408 20.496 21.456 ;
     RECT  20.52 21.408 20.64 21.456 ;
     RECT  20.664 21.408 20.832 21.456 ;
     RECT  20.856 21.408 20.976 21.456 ;
     RECT  21 21.408 21.168 21.456 ;
     RECT  21.192 21.408 21.312 21.456 ;
     RECT  21.336 21.408 21.504 21.456 ;
     RECT  21.528 21.408 21.648 21.456 ;
     RECT  21.672 21.408 21.84 21.456 ;
     RECT  21.864 21.408 21.984 21.456 ;
     RECT  22.008 21.408 22.176 21.456 ;
     RECT  22.2 21.408 22.32 21.456 ;
     RECT  22.344 21.408 22.464 21.456 ;
     RECT  22.488 21.408 22.656 21.456 ;
     RECT  22.68 21.408 22.8 21.456 ;
     RECT  22.824 21.408 22.992 21.456 ;
     RECT  23.016 21.408 23.136 21.456 ;
     RECT  23.16 21.408 23.328 21.456 ;
     RECT  23.352 21.408 23.472 21.456 ;
     RECT  23.496 21.408 23.664 21.456 ;
     RECT  23.688 21.408 23.808 21.456 ;
     RECT  23.832 21.408 24 21.456 ;
     RECT  24.024 21.408 24.144 21.456 ;
     RECT  24.168 21.408 24.336 21.456 ;
     RECT  24.36 21.408 24.48 21.456 ;
     RECT  24.504 21.408 24.672 21.456 ;
     RECT  24.696 21.408 24.816 21.456 ;
     RECT  24.84 21.408 24.96 21.456 ;
     RECT  24.984 21.408 25.152 21.456 ;
     RECT  25.176 21.408 25.296 21.456 ;
     RECT  25.32 21.408 25.488 21.456 ;
     RECT  25.512 21.408 25.632 21.456 ;
     RECT  25.656 21.408 25.824 21.456 ;
     RECT  25.848 21.408 25.968 21.456 ;
     RECT  25.992 21.408 26.16 21.456 ;
     RECT  26.184 21.408 26.304 21.456 ;
     RECT  26.328 21.408 26.496 21.456 ;
     RECT  26.52 21.408 26.64 21.456 ;
     RECT  26.664 21.408 26.832 21.456 ;
     RECT  26.856 21.408 26.976 21.456 ;
     RECT  27 21.408 27.168 21.456 ;
     RECT  27.192 21.408 27.552 21.456 ;
     RECT  27.576 21.408 27.696 21.456 ;
     RECT  27.72 21.408 27.888 21.456 ;
     RECT  27.912 21.408 28.032 21.456 ;
     RECT  28.056 21.408 28.224 21.456 ;
     RECT  28.248 21.408 28.368 21.456 ;
     RECT  28.392 21.408 28.56 21.456 ;
     RECT  28.584 21.408 28.704 21.456 ;
     RECT  28.728 21.408 28.896 21.456 ;
     RECT  28.92 21.408 29.04 21.456 ;
     RECT  29.064 21.408 29.232 21.456 ;
     RECT  29.256 21.408 29.376 21.456 ;
     RECT  29.4 21.408 29.568 21.456 ;
     RECT  29.592 21.408 29.712 21.456 ;
     RECT  29.736 21.408 29.856 21.456 ;
     RECT  29.88 21.408 30.048 21.456 ;
     RECT  30.072 21.408 30.192 21.456 ;
     RECT  30.216 21.408 30.384 21.456 ;
     RECT  30.408 21.408 30.528 21.456 ;
     RECT  30.552 21.408 30.72 21.456 ;
     RECT  30.744 21.408 30.864 21.456 ;
     RECT  30.888 21.408 31.056 21.456 ;
     RECT  31.08 21.408 31.2 21.456 ;
     RECT  31.224 21.408 31.392 21.456 ;
     RECT  31.416 21.408 31.536 21.456 ;
     RECT  31.56 21.408 31.728 21.456 ;
     RECT  31.752 21.408 31.872 21.456 ;
     RECT  31.896 21.408 32.064 21.456 ;
     RECT  32.088 21.408 32.208 21.456 ;
     RECT  32.232 21.408 32.352 21.456 ;
     RECT  32.376 21.408 32.544 21.456 ;
     RECT  32.568 21.408 32.688 21.456 ;
     RECT  32.712 21.408 32.88 21.456 ;
     RECT  32.904 21.408 33.024 21.456 ;
     RECT  33.048 21.408 33.216 21.456 ;
     RECT  33.24 21.408 33.36 21.456 ;
     RECT  33.384 21.408 33.552 21.456 ;
     RECT  33.576 21.408 33.696 21.456 ;
     RECT  33.72 21.408 33.888 21.456 ;
     RECT  33.912 21.408 34.032 21.456 ;
     RECT  34.056 21.408 34.224 21.456 ;
     RECT  34.248 21.408 34.368 21.456 ;
     RECT  34.392 21.408 34.56 21.456 ;
     RECT  34.584 21.408 34.704 21.456 ;
     RECT  34.728 21.408 34.896 21.456 ;
     RECT  34.92 21.408 35.04 21.456 ;
     RECT  35.064 21.408 35.184 21.456 ;
     RECT  35.208 21.408 35.376 21.456 ;
     RECT  35.4 21.408 35.52 21.456 ;
     RECT  35.544 21.408 35.712 21.456 ;
     RECT  35.736 21.408 35.856 21.456 ;
     RECT  35.88 21.408 36.048 21.456 ;
     RECT  36.072 21.408 36.192 21.456 ;
     RECT  36.216 21.408 36.384 21.456 ;
     RECT  36.408 21.408 36.528 21.456 ;
     RECT  36.552 21.408 36.72 21.456 ;
     RECT  36.744 21.408 36.864 21.456 ;
     RECT  36.888 21.408 37.056 21.456 ;
     RECT  37.08 21.408 37.2 21.456 ;
     RECT  37.224 21.408 37.392 21.456 ;
     RECT  37.416 21.408 37.536 21.456 ;
     RECT  37.56 21.408 37.68 21.456 ;
     RECT  37.704 21.408 37.872 21.456 ;
     RECT  37.896 21.408 38.016 21.456 ;
     RECT  38.04 21.408 38.208 21.456 ;
     RECT  38.232 21.408 38.352 21.456 ;
     RECT  38.376 21.408 38.544 21.456 ;
     RECT  38.568 21.408 38.688 21.456 ;
     RECT  38.712 21.408 38.88 21.456 ;
     RECT  38.904 21.408 39.024 21.456 ;
     RECT  39.048 21.408 39.216 21.456 ;
     RECT  39.24 21.408 39.36 21.456 ;
     RECT  39.384 21.408 39.552 21.456 ;
     RECT  39.576 21.408 39.696 21.456 ;
     RECT  39.72 21.408 39.888 21.456 ;
     RECT  39.912 21.408 40.032 21.456 ;
     RECT  40.056 21.408 40.176 21.456 ;
     RECT  40.2 21.408 40.368 21.456 ;
     RECT  40.392 21.408 40.512 21.456 ;
     RECT  40.536 21.408 40.704 21.456 ;
     RECT  40.728 21.408 40.848 21.456 ;
     RECT  40.872 21.408 41.04 21.456 ;
     RECT  41.064 21.408 41.184 21.456 ;
     RECT  41.208 21.408 41.376 21.456 ;
     RECT  41.4 21.408 41.52 21.456 ;
     RECT  41.544 21.408 41.712 21.456 ;
     RECT  41.736 21.408 41.856 21.456 ;
     RECT  41.88 21.408 42.048 21.456 ;
     RECT  42.072 21.408 42.192 21.456 ;
     RECT  42.216 21.408 42.384 21.456 ;
     RECT  42.408 21.408 42.528 21.456 ;
     RECT  42.552 21.408 42.72 21.456 ;
     RECT  42.744 21.408 42.864 21.456 ;
     RECT  42.888 21.408 43.008 21.456 ;
     RECT  43.032 21.408 43.2 21.456 ;
     RECT  43.224 21.408 43.344 21.456 ;
     RECT  43.368 21.408 43.536 21.456 ;
     RECT  43.56 21.408 43.68 21.456 ;
     RECT  43.704 21.408 43.872 21.456 ;
     RECT  43.896 21.408 44.016 21.456 ;
     RECT  44.04 21.408 44.208 21.456 ;
     RECT  44.232 21.408 44.352 21.456 ;
     RECT  44.376 21.408 44.544 21.456 ;
     RECT  44.568 21.408 44.688 21.456 ;
     RECT  44.712 21.408 44.88 21.456 ;
     RECT  44.904 21.408 45.024 21.456 ;
     RECT  45.048 21.408 45.216 21.456 ;
     RECT  45.24 21.408 45.36 21.456 ;
     RECT  45.384 21.408 45.504 21.456 ;
     RECT  45.528 21.408 45.696 21.456 ;
     RECT  45.72 21.408 45.84 21.456 ;
     RECT  45.864 21.408 46.032 21.456 ;
     RECT  46.056 21.408 46.176 21.456 ;
     RECT  46.2 21.408 46.368 21.456 ;
     RECT  46.392 21.408 46.512 21.456 ;
     RECT  46.536 21.408 46.704 21.456 ;
     RECT  46.728 21.408 46.848 21.456 ;
     RECT  46.872 21.408 47.04 21.456 ;
     RECT  47.064 21.408 47.184 21.456 ;
     RECT  47.208 21.408 47.376 21.456 ;
     RECT  47.4 21.408 47.52 21.456 ;
     RECT  47.544 21.408 47.712 21.456 ;
     RECT  47.736 21.408 47.856 21.456 ;
     RECT  47.88 21.408 48 21.456 ;
     RECT  48.024 21.408 48.192 21.456 ;
     RECT  48.216 21.408 48.336 21.456 ;
     RECT  48.36 21.408 48.528 21.456 ;
     RECT  48.552 21.408 48.672 21.456 ;
     RECT  48.696 21.408 48.864 21.456 ;
     RECT  48.888 21.408 49.008 21.456 ;
     RECT  49.032 21.408 49.2 21.456 ;
     RECT  49.224 21.408 49.344 21.456 ;
     RECT  49.368 21.408 49.536 21.456 ;
     RECT  49.56 21.408 49.68 21.456 ;
     RECT  49.704 21.408 49.872 21.456 ;
     RECT  49.896 21.408 50.016 21.456 ;
     RECT  50.04 21.408 50.208 21.456 ;
     RECT  50.232 21.408 50.592 21.456 ;
     RECT  50.616 21.408 50.736 21.456 ;
     RECT  50.76 21.408 50.928 21.456 ;
     RECT  50.952 21.408 51.072 21.456 ;
     RECT  51.096 21.408 51.264 21.456 ;
     RECT  51.288 21.408 51.408 21.456 ;
     RECT  51.432 21.408 51.6 21.456 ;
     RECT  51.624 21.408 51.744 21.456 ;
     RECT  51.768 21.408 51.936 21.456 ;
     RECT  51.96 21.408 52.08 21.456 ;
     RECT  52.104 21.408 52.272 21.456 ;
     RECT  52.296 21.408 52.416 21.456 ;
     RECT  52.44 21.408 52.608 21.456 ;
     RECT  52.632 21.408 52.752 21.456 ;
     RECT  52.776 21.408 52.896 21.456 ;
     RECT  52.92 21.408 53.088 21.456 ;
     RECT  53.112 21.408 53.232 21.456 ;
     RECT  53.256 21.408 53.424 21.456 ;
     RECT  53.448 21.408 53.568 21.456 ;
     RECT  53.592 21.408 53.76 21.456 ;
     RECT  53.784 21.408 53.904 21.456 ;
     RECT  53.928 21.408 54.096 21.456 ;
     RECT  54.12 21.408 54.24 21.456 ;
     RECT  54.264 21.408 54.432 21.456 ;
     RECT  54.456 21.408 54.576 21.456 ;
     RECT  54.6 21.408 54.768 21.456 ;
     RECT  54.792 21.408 54.912 21.456 ;
     RECT  54.936 21.408 55.104 21.456 ;
     RECT  55.128 21.408 55.248 21.456 ;
     RECT  55.272 21.408 55.392 21.456 ;
     RECT  55.416 21.408 55.584 21.456 ;
     RECT  55.608 21.408 55.728 21.456 ;
     RECT  55.752 21.408 55.92 21.456 ;
     RECT  55.944 21.408 56.064 21.456 ;
     RECT  56.088 21.408 56.256 21.456 ;
     RECT  56.28 21.408 56.4 21.456 ;
     RECT  56.424 21.408 56.592 21.456 ;
     RECT  56.616 21.408 56.736 21.456 ;
     RECT  56.76 21.408 56.928 21.456 ;
     RECT  56.952 21.408 57.072 21.456 ;
     RECT  57.096 21.408 57.264 21.456 ;
     RECT  57.288 21.408 57.408 21.456 ;
     RECT  57.432 21.408 57.6 21.456 ;
     RECT  57.624 21.408 57.744 21.456 ;
     RECT  57.768 21.408 57.936 21.456 ;
     RECT  57.96 21.408 58.08 21.456 ;
     RECT  58.104 21.408 58.224 21.456 ;
     RECT  58.248 21.408 58.416 21.456 ;
     RECT  58.44 21.408 58.56 21.456 ;
     RECT  58.584 21.408 58.752 21.456 ;
     RECT  58.776 21.408 58.896 21.456 ;
     RECT  58.92 21.408 59.088 21.456 ;
     RECT  59.112 21.408 59.232 21.456 ;
     RECT  59.256 21.408 59.424 21.456 ;
     RECT  59.448 21.408 59.568 21.456 ;
     RECT  59.592 21.408 59.76 21.456 ;
     RECT  59.784 21.408 59.904 21.456 ;
     RECT  59.928 21.408 60.096 21.456 ;
     RECT  60.12 21.408 60.24 21.456 ;
     RECT  60.264 21.408 60.432 21.456 ;
     RECT  60.456 21.408 60.576 21.456 ;
     RECT  60.6 21.408 60.72 21.456 ;
     RECT  60.744 21.408 60.912 21.456 ;
     RECT  60.936 21.408 61.056 21.456 ;
     RECT  61.08 21.408 61.248 21.456 ;
     RECT  61.272 21.408 61.392 21.456 ;
     RECT  61.416 21.408 61.584 21.456 ;
     RECT  61.608 21.408 61.728 21.456 ;
     RECT  61.752 21.408 61.92 21.456 ;
     RECT  61.944 21.408 62.064 21.456 ;
     RECT  62.088 21.408 62.256 21.456 ;
     RECT  62.28 21.408 62.4 21.456 ;
     RECT  62.424 21.408 62.592 21.456 ;
     RECT  62.616 21.408 62.736 21.456 ;
     RECT  62.76 21.408 62.928 21.456 ;
     RECT  62.952 21.408 63.072 21.456 ;
     RECT  63.096 21.408 63.216 21.456 ;
     RECT  63.24 21.408 63.408 21.456 ;
     RECT  63.432 21.408 63.552 21.456 ;
     RECT  63.576 21.408 63.744 21.456 ;
     RECT  63.768 21.408 63.888 21.456 ;
     RECT  63.912 21.408 64.08 21.456 ;
     RECT  64.104 21.408 64.224 21.456 ;
     RECT  64.248 21.408 64.416 21.456 ;
     RECT  64.44 21.408 64.56 21.456 ;
     RECT  64.584 21.408 64.752 21.456 ;
     RECT  64.776 21.408 64.896 21.456 ;
     RECT  64.92 21.408 65.088 21.456 ;
     RECT  65.112 21.408 65.232 21.456 ;
     RECT  65.256 21.408 65.424 21.456 ;
     RECT  65.448 21.408 65.568 21.456 ;
     RECT  65.592 21.408 65.76 21.456 ;
     RECT  65.784 21.408 65.904 21.456 ;
     RECT  65.928 21.408 66.048 21.456 ;
     RECT  66.072 21.408 66.24 21.456 ;
     RECT  66.264 21.408 66.384 21.456 ;
     RECT  66.408 21.408 66.576 21.456 ;
     RECT  66.6 21.408 66.72 21.456 ;
     RECT  66.744 21.408 66.912 21.456 ;
     RECT  66.936 21.408 67.056 21.456 ;
     RECT  67.08 21.408 67.248 21.456 ;
     RECT  67.272 21.408 67.392 21.456 ;
     RECT  67.416 21.408 67.584 21.456 ;
     RECT  67.608 21.408 67.728 21.456 ;
     RECT  67.752 21.408 67.92 21.456 ;
     RECT  67.944 21.408 68.064 21.456 ;
     RECT  68.088 21.408 68.256 21.456 ;
     RECT  68.28 21.408 68.4 21.456 ;
     RECT  68.424 21.408 68.544 21.456 ;
     RECT  68.568 21.408 68.736 21.456 ;
     RECT  68.76 21.408 68.88 21.456 ;
     RECT  68.904 21.408 69.072 21.456 ;
     RECT  69.096 21.408 69.216 21.456 ;
     RECT  69.24 21.408 69.408 21.456 ;
     RECT  69.432 21.408 69.552 21.456 ;
     RECT  69.576 21.408 69.744 21.456 ;
     RECT  69.768 21.408 69.888 21.456 ;
     RECT  69.912 21.408 70.08 21.456 ;
     RECT  70.104 21.408 70.224 21.456 ;
     RECT  70.248 21.408 70.416 21.456 ;
     RECT  70.44 21.408 70.56 21.456 ;
     RECT  70.584 21.408 70.752 21.456 ;
     RECT  70.776 21.408 70.896 21.456 ;
     RECT  70.92 21.408 71.04 21.456 ;
     RECT  71.064 21.408 71.232 21.456 ;
     RECT  71.256 21.408 71.376 21.456 ;
     RECT  71.4 21.408 71.568 21.456 ;
     RECT  71.592 21.408 71.712 21.456 ;
     RECT  71.736 21.408 71.904 21.456 ;
     RECT  71.928 21.408 72.048 21.456 ;
     RECT  72.072 21.408 72.24 21.456 ;
     RECT  72.264 21.408 72.384 21.456 ;
     RECT  72.408 21.408 72.576 21.456 ;
     RECT  72.6 21.408 72.72 21.456 ;
     RECT  72.744 21.408 72.912 21.456 ;
     RECT  72.936 21.408 73.056 21.456 ;
     RECT  73.08 21.408 73.248 21.456 ;
     RECT  27.312 21.456 27.336 21.491 ;
     RECT  53.64 0.611 54.624 1.715 ;
     RECT  61.464 1.139 62.448 1.763 ;
     RECT  62.472 1.139 63.456 1.763 ;
     RECT  60.456 1.187 61.44 1.763 ;
     RECT  53.64 1.715 55.152 1.763 ;
     RECT  59.448 1.715 60.432 1.763 ;
     RECT  67.704 1.715 68.688 1.763 ;
     RECT  4.608 1.763 5.1 2.821 ;
     RECT  6.024 1.763 7.248 2.291 ;
     RECT  10.272 1.763 10.5 2.773 ;
     RECT  13.512 1.763 14.544 1.811 ;
     RECT  14.568 1.763 15.9 1.811 ;
     RECT  25.128 1.763 26.7 1.811 ;
     RECT  29.28 1.763 29.4 3.061 ;
     RECT  32.412 1.763 33.408 1.859 ;
     RECT  33.432 1.763 34.8 1.859 ;
     RECT  41.112 1.763 42.576 1.811 ;
     RECT  48.612 1.763 49.872 2.195 ;
     RECT  49.896 1.763 51 2.195 ;
     RECT  53.64 1.763 55.344 2.137 ;
     RECT  61.8 1.763 62.112 2.137 ;
     RECT  64.812 1.763 66.192 2.291 ;
     RECT  66.216 1.763 67.2 2.291 ;
     RECT  71.256 1.763 72.6 2.291 ;
     RECT  15.36 1.811 15.9 3.061 ;
     RECT  24.312 1.811 26.7 2.821 ;
     RECT  32.412 1.859 32.52 2.869 ;
     RECT  37.812 1.859 39.312 2.869 ;
     RECT  54.012 2.137 55.344 17.605 ;
     RECT  5.412 2.291 7.8 2.725 ;
     RECT  55.368 2.291 56.4 16.213 ;
     RECT  5.412 2.725 6.528 2.867 ;
     RECT  6.552 2.725 7.8 2.867 ;
     RECT  24.312 2.821 25.68 3.205 ;
     RECT  25.704 2.821 26.7 4.643 ;
     RECT  37.812 2.869 39.12 3.107 ;
     RECT  37.812 3.107 39.216 3.299 ;
     RECT  37.812 3.299 37.944 3.733 ;
     RECT  16.212 3.349 17.616 4.069 ;
     RECT  18.912 3.397 19.968 4.115 ;
     RECT  19.992 3.397 21.12 3.925 ;
     RECT  24.552 3.635 25.68 4.643 ;
     RECT  35.112 3.925 36.096 4.213 ;
     RECT  36.12 3.925 37.5 4.501 ;
     RECT  29.712 3.973 30.912 4.547 ;
     RECT  30.936 3.973 31.968 4.357 ;
     RECT  16.212 4.069 17.52 5.171 ;
     RECT  18.912 4.115 20.16 5.173 ;
     RECT  23.424 4.115 24 4.981 ;
     RECT  8.112 4.165 9.216 4.979 ;
     RECT  9.24 4.165 10.272 4.979 ;
     RECT  30.936 4.499 32.1 4.547 ;
     RECT  29.712 4.547 32.1 5.029 ;
     RECT  35.112 4.547 36.096 5.123 ;
     RECT  24.552 4.643 26.7 4.693 ;
     RECT  24.552 4.693 26.208 4.885 ;
     RECT  33.336 4.693 34.8 5.747 ;
     RECT  36.12 4.739 37.392 5.123 ;
     RECT  25.128 4.885 26.208 5.315 ;
     RECT  8.112 4.979 8.232 5.173 ;
     RECT  21.612 4.981 22.8 5.171 ;
     RECT  22.824 4.981 24 5.171 ;
     RECT  29.712 5.029 30.768 5.267 ;
     RECT  30.792 5.029 32.1 5.267 ;
     RECT  16.212 5.171 17.616 5.747 ;
     RECT  25.128 5.315 26.7 5.845 ;
     RECT  18.912 5.603 20.16 5.747 ;
     RECT  25.32 5.845 26.7 6.083 ;
     RECT  27.012 6.083 28.32 6.131 ;
     RECT  29.712 14.101 30.768 14.243 ;
     RECT  30.792 14.101 32.1 14.243 ;
     RECT  5.412 15.061 6.672 18.805 ;
     RECT  6.696 15.061 7.8 15.253 ;
     RECT  10.812 15.925 12.144 18.757 ;
     RECT  37.812 15.925 39.072 16.021 ;
     RECT  39.096 15.925 40.2 16.115 ;
     RECT  29.28 16.019 29.4 17.221 ;
     RECT  38.04 16.021 39.072 16.115 ;
     RECT  38.04 16.115 40.2 16.403 ;
     RECT  37.944 16.403 40.2 17.077 ;
     RECT  55.368 16.403 56.4 17.653 ;
     RECT  21.612 16.789 22.8 16.931 ;
     RECT  22.824 16.789 23.808 16.931 ;
     RECT  21.612 16.931 23.808 17.221 ;
     RECT  37.944 17.077 39.216 18.229 ;
     RECT  47.064 17.125 48.3 17.653 ;
     RECT  22.488 17.221 23.808 17.605 ;
     RECT  27.012 17.221 28.224 17.605 ;
     RECT  28.248 17.221 29.4 18.229 ;
     RECT  22.488 17.605 23.664 18.901 ;
     RECT  27.144 17.605 28.224 18.229 ;
     RECT  40.512 17.605 41.712 19.957 ;
     RECT  41.736 17.605 42.9 17.653 ;
     RECT  54.264 17.605 55.344 19.285 ;
     RECT  33.576 17.653 34.8 19.381 ;
     RECT  51.432 18.181 52.896 18.757 ;
     RECT  38.232 18.229 39.216 19.141 ;
     RECT  43.896 18.229 44.88 18.757 ;
     RECT  30.216 18.565 31.2 18.901 ;
     RECT  10.812 18.757 11.856 19.525 ;
     RECT  13.704 18.757 15.168 18.805 ;
     RECT  51.432 18.757 52.608 19.333 ;
     RECT  56.712 18.757 57.936 18.805 ;
     RECT  57.96 18.757 59.1 18.805 ;
     RECT  70.584 18.757 71.568 20.533 ;
     RECT  71.592 18.757 72.6 19.957 ;
     RECT  59.928 18.805 60.912 19.381 ;
     RECT  22.68 18.901 23.664 18.949 ;
     RECT  24.84 18.901 25.968 18.949 ;
     RECT  24.984 18.949 25.968 19.237 ;
     RECT  48.744 19.381 49.872 19.957 ;
     RECT  53.112 19.463 54.096 20.533 ;
     RECT  60.936 19.463 61.92 20.533 ;
     RECT  10.872 19.525 11.856 19.957 ;
     RECT  62.76 19.957 64.08 20.533 ;
     RECT  65.112 19.957 66.384 20.533 ;
  END
END hbfd_rly_136_SN_fc_f4
END LIBRARY
